VERSION 5.8 ;
BUSBITCHARS "[]" ;
DIVIDERCHAR "/" ;
UNITS
    DATABASE MICRONS 1000 ;
END UNITS

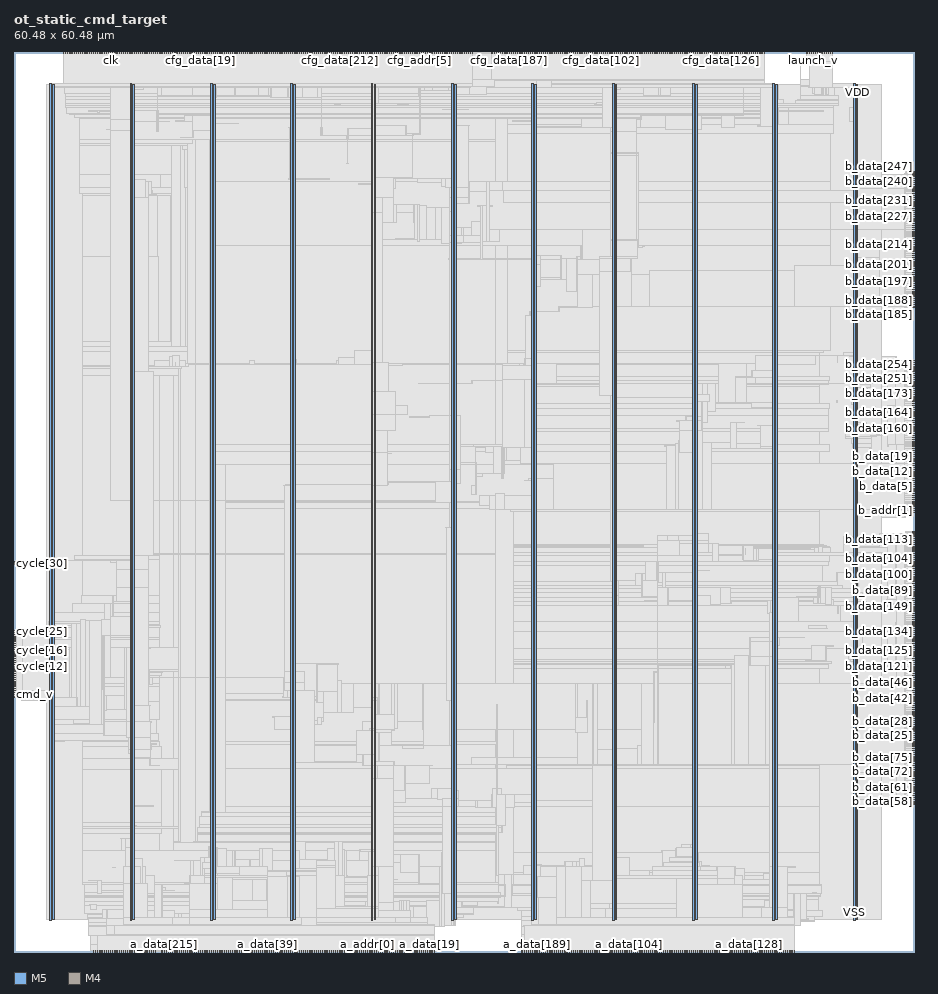
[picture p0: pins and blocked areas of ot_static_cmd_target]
MACRO ot_static_cmd_target
  FOREIGN ot_static_cmd_target 0 0 ;
  CLASS BLOCK ;
  SIZE 60.48 BY 60.48 ;
  PIN a_addr[0]
    DIRECTION OUTPUT ;
    USE SIGNAL ;
    PORT
      LAYER M5 ;
        RECT  23.76 0 23.784 0.084 ;
    END
  END a_addr[0]
  PIN a_addr[1]
    DIRECTION OUTPUT ;
    USE SIGNAL ;
    PORT
      LAYER M5 ;
        RECT  23.904 0 23.928 0.084 ;
    END
  END a_addr[1]
  PIN a_addr[2]
    DIRECTION OUTPUT ;
    USE SIGNAL ;
    PORT
      LAYER M5 ;
        RECT  24.048 0 24.072 0.084 ;
    END
  END a_addr[2]
  PIN a_addr[3]
    DIRECTION OUTPUT ;
    USE SIGNAL ;
    PORT
      LAYER M5 ;
        RECT  24.192 0 24.216 0.084 ;
    END
  END a_addr[3]
  PIN a_addr[4]
    DIRECTION OUTPUT ;
    USE SIGNAL ;
    PORT
      LAYER M5 ;
        RECT  24.336 0 24.36 0.084 ;
    END
  END a_addr[4]
  PIN a_addr[5]
    DIRECTION OUTPUT ;
    USE SIGNAL ;
    PORT
      LAYER M5 ;
        RECT  24.48 0 24.504 0.084 ;
    END
  END a_addr[5]
  PIN a_addr[6]
    DIRECTION OUTPUT ;
    USE SIGNAL ;
    PORT
      LAYER M5 ;
        RECT  24.624 0 24.648 0.084 ;
    END
  END a_addr[6]
  PIN a_addr[7]
    DIRECTION OUTPUT ;
    USE SIGNAL ;
    PORT
      LAYER M5 ;
        RECT  24.768 0 24.792 0.084 ;
    END
  END a_addr[7]
  PIN a_addr[8]
    DIRECTION OUTPUT ;
    USE SIGNAL ;
    PORT
      LAYER M5 ;
        RECT  24.912 0 24.936 0.084 ;
    END
  END a_addr[8]
  PIN a_addr[9]
    DIRECTION OUTPUT ;
    USE SIGNAL ;
    PORT
      LAYER M5 ;
        RECT  25.056 0 25.08 0.084 ;
    END
  END a_addr[9]
  PIN a_data[0]
    DIRECTION OUTPUT ;
    USE SIGNAL ;
    PORT
      LAYER M5 ;
        RECT  25.2 0 25.224 0.084 ;
    END
  END a_data[0]
  PIN a_data[100]
    DIRECTION OUTPUT ;
    USE SIGNAL ;
    PORT
      LAYER M5 ;
        RECT  40.752 0 40.776 0.084 ;
    END
  END a_data[100]
  PIN a_data[101]
    DIRECTION OUTPUT ;
    USE SIGNAL ;
    PORT
      LAYER M5 ;
        RECT  40.896 0 40.92 0.084 ;
    END
  END a_data[101]
  PIN a_data[102]
    DIRECTION OUTPUT ;
    USE SIGNAL ;
    PORT
      LAYER M5 ;
        RECT  41.04 0 41.064 0.084 ;
    END
  END a_data[102]
  PIN a_data[103]
    DIRECTION OUTPUT ;
    USE SIGNAL ;
    PORT
      LAYER M5 ;
        RECT  41.184 0 41.208 0.084 ;
    END
  END a_data[103]
  PIN a_data[104]
    DIRECTION OUTPUT ;
    USE SIGNAL ;
    PORT
      LAYER M5 ;
        RECT  41.328 0 41.352 0.084 ;
    END
  END a_data[104]
  PIN a_data[105]
    DIRECTION OUTPUT ;
    USE SIGNAL ;
    PORT
      LAYER M5 ;
        RECT  41.472 0 41.496 0.084 ;
    END
  END a_data[105]
  PIN a_data[106]
    DIRECTION OUTPUT ;
    USE SIGNAL ;
    PORT
      LAYER M5 ;
        RECT  41.616 0 41.64 0.084 ;
    END
  END a_data[106]
  PIN a_data[107]
    DIRECTION OUTPUT ;
    USE SIGNAL ;
    PORT
      LAYER M5 ;
        RECT  41.76 0 41.784 0.084 ;
    END
  END a_data[107]
  PIN a_data[108]
    DIRECTION OUTPUT ;
    USE SIGNAL ;
    PORT
      LAYER M5 ;
        RECT  41.904 0 41.928 0.084 ;
    END
  END a_data[108]
  PIN a_data[109]
    DIRECTION OUTPUT ;
    USE SIGNAL ;
    PORT
      LAYER M5 ;
        RECT  42.048 0 42.072 0.084 ;
    END
  END a_data[109]
  PIN a_data[10]
    DIRECTION OUTPUT ;
    USE SIGNAL ;
    PORT
      LAYER M5 ;
        RECT  26.64 0 26.664 0.084 ;
    END
  END a_data[10]
  PIN a_data[110]
    DIRECTION OUTPUT ;
    USE SIGNAL ;
    PORT
      LAYER M5 ;
        RECT  42.192 0 42.216 0.084 ;
    END
  END a_data[110]
  PIN a_data[111]
    DIRECTION OUTPUT ;
    USE SIGNAL ;
    PORT
      LAYER M5 ;
        RECT  42.336 0 42.36 0.084 ;
    END
  END a_data[111]
  PIN a_data[112]
    DIRECTION OUTPUT ;
    USE SIGNAL ;
    PORT
      LAYER M5 ;
        RECT  42.48 0 42.504 0.084 ;
    END
  END a_data[112]
  PIN a_data[113]
    DIRECTION OUTPUT ;
    USE SIGNAL ;
    PORT
      LAYER M5 ;
        RECT  42.624 0 42.648 0.084 ;
    END
  END a_data[113]
  PIN a_data[114]
    DIRECTION OUTPUT ;
    USE SIGNAL ;
    PORT
      LAYER M5 ;
        RECT  42.768 0 42.792 0.084 ;
    END
  END a_data[114]
  PIN a_data[115]
    DIRECTION OUTPUT ;
    USE SIGNAL ;
    PORT
      LAYER M5 ;
        RECT  42.912 0 42.936 0.084 ;
    END
  END a_data[115]
  PIN a_data[116]
    DIRECTION OUTPUT ;
    USE SIGNAL ;
    PORT
      LAYER M5 ;
        RECT  43.056 0 43.08 0.084 ;
    END
  END a_data[116]
  PIN a_data[117]
    DIRECTION OUTPUT ;
    USE SIGNAL ;
    PORT
      LAYER M5 ;
        RECT  43.2 0 43.224 0.084 ;
    END
  END a_data[117]
  PIN a_data[118]
    DIRECTION OUTPUT ;
    USE SIGNAL ;
    PORT
      LAYER M5 ;
        RECT  47.952 0 47.976 0.084 ;
    END
  END a_data[118]
  PIN a_data[119]
    DIRECTION OUTPUT ;
    USE SIGNAL ;
    PORT
      LAYER M5 ;
        RECT  48.096 0 48.12 0.084 ;
    END
  END a_data[119]
  PIN a_data[11]
    DIRECTION OUTPUT ;
    USE SIGNAL ;
    PORT
      LAYER M5 ;
        RECT  26.784 0 26.808 0.084 ;
    END
  END a_data[11]
  PIN a_data[120]
    DIRECTION OUTPUT ;
    USE SIGNAL ;
    PORT
      LAYER M5 ;
        RECT  48.24 0 48.264 0.084 ;
    END
  END a_data[120]
  PIN a_data[121]
    DIRECTION OUTPUT ;
    USE SIGNAL ;
    PORT
      LAYER M5 ;
        RECT  48.384 0 48.408 0.084 ;
    END
  END a_data[121]
  PIN a_data[122]
    DIRECTION OUTPUT ;
    USE SIGNAL ;
    PORT
      LAYER M5 ;
        RECT  48.528 0 48.552 0.084 ;
    END
  END a_data[122]
  PIN a_data[123]
    DIRECTION OUTPUT ;
    USE SIGNAL ;
    PORT
      LAYER M5 ;
        RECT  48.672 0 48.696 0.084 ;
    END
  END a_data[123]
  PIN a_data[124]
    DIRECTION OUTPUT ;
    USE SIGNAL ;
    PORT
      LAYER M5 ;
        RECT  48.816 0 48.84 0.084 ;
    END
  END a_data[124]
  PIN a_data[125]
    DIRECTION OUTPUT ;
    USE SIGNAL ;
    PORT
      LAYER M5 ;
        RECT  48.96 0 48.984 0.084 ;
    END
  END a_data[125]
  PIN a_data[126]
    DIRECTION OUTPUT ;
    USE SIGNAL ;
    PORT
      LAYER M5 ;
        RECT  49.104 0 49.128 0.084 ;
    END
  END a_data[126]
  PIN a_data[127]
    DIRECTION OUTPUT ;
    USE SIGNAL ;
    PORT
      LAYER M5 ;
        RECT  49.248 0 49.272 0.084 ;
    END
  END a_data[127]
  PIN a_data[128]
    DIRECTION OUTPUT ;
    USE SIGNAL ;
    PORT
      LAYER M5 ;
        RECT  49.392 0 49.416 0.084 ;
    END
  END a_data[128]
  PIN a_data[129]
    DIRECTION OUTPUT ;
    USE SIGNAL ;
    PORT
      LAYER M5 ;
        RECT  49.536 0 49.56 0.084 ;
    END
  END a_data[129]
  PIN a_data[12]
    DIRECTION OUTPUT ;
    USE SIGNAL ;
    PORT
      LAYER M5 ;
        RECT  26.928 0 26.952 0.084 ;
    END
  END a_data[12]
  PIN a_data[130]
    DIRECTION OUTPUT ;
    USE SIGNAL ;
    PORT
      LAYER M5 ;
        RECT  49.68 0 49.704 0.084 ;
    END
  END a_data[130]
  PIN a_data[131]
    DIRECTION OUTPUT ;
    USE SIGNAL ;
    PORT
      LAYER M5 ;
        RECT  49.824 0 49.848 0.084 ;
    END
  END a_data[131]
  PIN a_data[132]
    DIRECTION OUTPUT ;
    USE SIGNAL ;
    PORT
      LAYER M5 ;
        RECT  49.968 0 49.992 0.084 ;
    END
  END a_data[132]
  PIN a_data[133]
    DIRECTION OUTPUT ;
    USE SIGNAL ;
    PORT
      LAYER M5 ;
        RECT  50.112 0 50.136 0.084 ;
    END
  END a_data[133]
  PIN a_data[134]
    DIRECTION OUTPUT ;
    USE SIGNAL ;
    PORT
      LAYER M5 ;
        RECT  50.256 0 50.28 0.084 ;
    END
  END a_data[134]
  PIN a_data[135]
    DIRECTION OUTPUT ;
    USE SIGNAL ;
    PORT
      LAYER M5 ;
        RECT  50.4 0 50.424 0.084 ;
    END
  END a_data[135]
  PIN a_data[136]
    DIRECTION OUTPUT ;
    USE SIGNAL ;
    PORT
      LAYER M5 ;
        RECT  50.544 0 50.568 0.084 ;
    END
  END a_data[136]
  PIN a_data[137]
    DIRECTION OUTPUT ;
    USE SIGNAL ;
    PORT
      LAYER M5 ;
        RECT  50.688 0 50.712 0.084 ;
    END
  END a_data[137]
  PIN a_data[138]
    DIRECTION OUTPUT ;
    USE SIGNAL ;
    PORT
      LAYER M5 ;
        RECT  50.832 0 50.856 0.084 ;
    END
  END a_data[138]
  PIN a_data[139]
    DIRECTION OUTPUT ;
    USE SIGNAL ;
    PORT
      LAYER M5 ;
        RECT  50.976 0 51 0.084 ;
    END
  END a_data[139]
  PIN a_data[13]
    DIRECTION OUTPUT ;
    USE SIGNAL ;
    PORT
      LAYER M5 ;
        RECT  27.072 0 27.096 0.084 ;
    END
  END a_data[13]
  PIN a_data[140]
    DIRECTION OUTPUT ;
    USE SIGNAL ;
    PORT
      LAYER M5 ;
        RECT  51.12 0 51.144 0.084 ;
    END
  END a_data[140]
  PIN a_data[141]
    DIRECTION OUTPUT ;
    USE SIGNAL ;
    PORT
      LAYER M5 ;
        RECT  51.264 0 51.288 0.084 ;
    END
  END a_data[141]
  PIN a_data[142]
    DIRECTION OUTPUT ;
    USE SIGNAL ;
    PORT
      LAYER M5 ;
        RECT  51.408 0 51.432 0.084 ;
    END
  END a_data[142]
  PIN a_data[143]
    DIRECTION OUTPUT ;
    USE SIGNAL ;
    PORT
      LAYER M5 ;
        RECT  51.552 0 51.576 0.084 ;
    END
  END a_data[143]
  PIN a_data[144]
    DIRECTION OUTPUT ;
    USE SIGNAL ;
    PORT
      LAYER M5 ;
        RECT  51.696 0 51.72 0.084 ;
    END
  END a_data[144]
  PIN a_data[145]
    DIRECTION OUTPUT ;
    USE SIGNAL ;
    PORT
      LAYER M5 ;
        RECT  51.84 0 51.864 0.084 ;
    END
  END a_data[145]
  PIN a_data[146]
    DIRECTION OUTPUT ;
    USE SIGNAL ;
    PORT
      LAYER M5 ;
        RECT  51.984 0 52.008 0.084 ;
    END
  END a_data[146]
  PIN a_data[147]
    DIRECTION OUTPUT ;
    USE SIGNAL ;
    PORT
      LAYER M5 ;
        RECT  52.128 0 52.152 0.084 ;
    END
  END a_data[147]
  PIN a_data[148]
    DIRECTION OUTPUT ;
    USE SIGNAL ;
    PORT
      LAYER M5 ;
        RECT  52.272 0 52.296 0.084 ;
    END
  END a_data[148]
  PIN a_data[149]
    DIRECTION OUTPUT ;
    USE SIGNAL ;
    PORT
      LAYER M5 ;
        RECT  52.416 0 52.44 0.084 ;
    END
  END a_data[149]
  PIN a_data[14]
    DIRECTION OUTPUT ;
    USE SIGNAL ;
    PORT
      LAYER M5 ;
        RECT  27.216 0 27.24 0.084 ;
    END
  END a_data[14]
  PIN a_data[150]
    DIRECTION OUTPUT ;
    USE SIGNAL ;
    PORT
      LAYER M5 ;
        RECT  43.344 0 43.368 0.084 ;
    END
  END a_data[150]
  PIN a_data[151]
    DIRECTION OUTPUT ;
    USE SIGNAL ;
    PORT
      LAYER M5 ;
        RECT  43.488 0 43.512 0.084 ;
    END
  END a_data[151]
  PIN a_data[152]
    DIRECTION OUTPUT ;
    USE SIGNAL ;
    PORT
      LAYER M5 ;
        RECT  43.632 0 43.656 0.084 ;
    END
  END a_data[152]
  PIN a_data[153]
    DIRECTION OUTPUT ;
    USE SIGNAL ;
    PORT
      LAYER M5 ;
        RECT  43.776 0 43.8 0.084 ;
    END
  END a_data[153]
  PIN a_data[154]
    DIRECTION OUTPUT ;
    USE SIGNAL ;
    PORT
      LAYER M5 ;
        RECT  43.92 0 43.944 0.084 ;
    END
  END a_data[154]
  PIN a_data[155]
    DIRECTION OUTPUT ;
    USE SIGNAL ;
    PORT
      LAYER M5 ;
        RECT  44.064 0 44.088 0.084 ;
    END
  END a_data[155]
  PIN a_data[156]
    DIRECTION OUTPUT ;
    USE SIGNAL ;
    PORT
      LAYER M5 ;
        RECT  44.208 0 44.232 0.084 ;
    END
  END a_data[156]
  PIN a_data[157]
    DIRECTION OUTPUT ;
    USE SIGNAL ;
    PORT
      LAYER M5 ;
        RECT  44.352 0 44.376 0.084 ;
    END
  END a_data[157]
  PIN a_data[158]
    DIRECTION OUTPUT ;
    USE SIGNAL ;
    PORT
      LAYER M5 ;
        RECT  44.496 0 44.52 0.084 ;
    END
  END a_data[158]
  PIN a_data[159]
    DIRECTION OUTPUT ;
    USE SIGNAL ;
    PORT
      LAYER M5 ;
        RECT  44.64 0 44.664 0.084 ;
    END
  END a_data[159]
  PIN a_data[15]
    DIRECTION OUTPUT ;
    USE SIGNAL ;
    PORT
      LAYER M5 ;
        RECT  27.36 0 27.384 0.084 ;
    END
  END a_data[15]
  PIN a_data[160]
    DIRECTION OUTPUT ;
    USE SIGNAL ;
    PORT
      LAYER M5 ;
        RECT  44.784 0 44.808 0.084 ;
    END
  END a_data[160]
  PIN a_data[161]
    DIRECTION OUTPUT ;
    USE SIGNAL ;
    PORT
      LAYER M5 ;
        RECT  44.928 0 44.952 0.084 ;
    END
  END a_data[161]
  PIN a_data[162]
    DIRECTION OUTPUT ;
    USE SIGNAL ;
    PORT
      LAYER M5 ;
        RECT  45.072 0 45.096 0.084 ;
    END
  END a_data[162]
  PIN a_data[163]
    DIRECTION OUTPUT ;
    USE SIGNAL ;
    PORT
      LAYER M5 ;
        RECT  45.216 0 45.24 0.084 ;
    END
  END a_data[163]
  PIN a_data[164]
    DIRECTION OUTPUT ;
    USE SIGNAL ;
    PORT
      LAYER M5 ;
        RECT  45.36 0 45.384 0.084 ;
    END
  END a_data[164]
  PIN a_data[165]
    DIRECTION OUTPUT ;
    USE SIGNAL ;
    PORT
      LAYER M5 ;
        RECT  45.504 0 45.528 0.084 ;
    END
  END a_data[165]
  PIN a_data[166]
    DIRECTION OUTPUT ;
    USE SIGNAL ;
    PORT
      LAYER M5 ;
        RECT  45.648 0 45.672 0.084 ;
    END
  END a_data[166]
  PIN a_data[167]
    DIRECTION OUTPUT ;
    USE SIGNAL ;
    PORT
      LAYER M5 ;
        RECT  45.792 0 45.816 0.084 ;
    END
  END a_data[167]
  PIN a_data[168]
    DIRECTION OUTPUT ;
    USE SIGNAL ;
    PORT
      LAYER M5 ;
        RECT  45.936 0 45.96 0.084 ;
    END
  END a_data[168]
  PIN a_data[169]
    DIRECTION OUTPUT ;
    USE SIGNAL ;
    PORT
      LAYER M5 ;
        RECT  46.08 0 46.104 0.084 ;
    END
  END a_data[169]
  PIN a_data[16]
    DIRECTION OUTPUT ;
    USE SIGNAL ;
    PORT
      LAYER M5 ;
        RECT  27.504 0 27.528 0.084 ;
    END
  END a_data[16]
  PIN a_data[170]
    DIRECTION OUTPUT ;
    USE SIGNAL ;
    PORT
      LAYER M5 ;
        RECT  46.224 0 46.248 0.084 ;
    END
  END a_data[170]
  PIN a_data[171]
    DIRECTION OUTPUT ;
    USE SIGNAL ;
    PORT
      LAYER M5 ;
        RECT  46.368 0 46.392 0.084 ;
    END
  END a_data[171]
  PIN a_data[172]
    DIRECTION OUTPUT ;
    USE SIGNAL ;
    PORT
      LAYER M5 ;
        RECT  46.512 0 46.536 0.084 ;
    END
  END a_data[172]
  PIN a_data[173]
    DIRECTION OUTPUT ;
    USE SIGNAL ;
    PORT
      LAYER M5 ;
        RECT  46.656 0 46.68 0.084 ;
    END
  END a_data[173]
  PIN a_data[174]
    DIRECTION OUTPUT ;
    USE SIGNAL ;
    PORT
      LAYER M5 ;
        RECT  46.8 0 46.824 0.084 ;
    END
  END a_data[174]
  PIN a_data[175]
    DIRECTION OUTPUT ;
    USE SIGNAL ;
    PORT
      LAYER M5 ;
        RECT  46.944 0 46.968 0.084 ;
    END
  END a_data[175]
  PIN a_data[176]
    DIRECTION OUTPUT ;
    USE SIGNAL ;
    PORT
      LAYER M5 ;
        RECT  47.088 0 47.112 0.084 ;
    END
  END a_data[176]
  PIN a_data[177]
    DIRECTION OUTPUT ;
    USE SIGNAL ;
    PORT
      LAYER M5 ;
        RECT  47.232 0 47.256 0.084 ;
    END
  END a_data[177]
  PIN a_data[178]
    DIRECTION OUTPUT ;
    USE SIGNAL ;
    PORT
      LAYER M5 ;
        RECT  47.376 0 47.4 0.084 ;
    END
  END a_data[178]
  PIN a_data[179]
    DIRECTION OUTPUT ;
    USE SIGNAL ;
    PORT
      LAYER M5 ;
        RECT  47.52 0 47.544 0.084 ;
    END
  END a_data[179]
  PIN a_data[17]
    DIRECTION OUTPUT ;
    USE SIGNAL ;
    PORT
      LAYER M5 ;
        RECT  27.648 0 27.672 0.084 ;
    END
  END a_data[17]
  PIN a_data[180]
    DIRECTION OUTPUT ;
    USE SIGNAL ;
    PORT
      LAYER M5 ;
        RECT  47.664 0 47.688 0.084 ;
    END
  END a_data[180]
  PIN a_data[181]
    DIRECTION OUTPUT ;
    USE SIGNAL ;
    PORT
      LAYER M5 ;
        RECT  47.808 0 47.832 0.084 ;
    END
  END a_data[181]
  PIN a_data[182]
    DIRECTION OUTPUT ;
    USE SIGNAL ;
    PORT
      LAYER M5 ;
        RECT  34.128 0 34.152 0.084 ;
    END
  END a_data[182]
  PIN a_data[183]
    DIRECTION OUTPUT ;
    USE SIGNAL ;
    PORT
      LAYER M5 ;
        RECT  34.272 0 34.296 0.084 ;
    END
  END a_data[183]
  PIN a_data[184]
    DIRECTION OUTPUT ;
    USE SIGNAL ;
    PORT
      LAYER M5 ;
        RECT  34.416 0 34.44 0.084 ;
    END
  END a_data[184]
  PIN a_data[185]
    DIRECTION OUTPUT ;
    USE SIGNAL ;
    PORT
      LAYER M5 ;
        RECT  34.56 0 34.584 0.084 ;
    END
  END a_data[185]
  PIN a_data[186]
    DIRECTION OUTPUT ;
    USE SIGNAL ;
    PORT
      LAYER M5 ;
        RECT  34.704 0 34.728 0.084 ;
    END
  END a_data[186]
  PIN a_data[187]
    DIRECTION OUTPUT ;
    USE SIGNAL ;
    PORT
      LAYER M5 ;
        RECT  34.848 0 34.872 0.084 ;
    END
  END a_data[187]
  PIN a_data[188]
    DIRECTION OUTPUT ;
    USE SIGNAL ;
    PORT
      LAYER M5 ;
        RECT  34.992 0 35.016 0.084 ;
    END
  END a_data[188]
  PIN a_data[189]
    DIRECTION OUTPUT ;
    USE SIGNAL ;
    PORT
      LAYER M5 ;
        RECT  35.136 0 35.16 0.084 ;
    END
  END a_data[189]
  PIN a_data[18]
    DIRECTION OUTPUT ;
    USE SIGNAL ;
    PORT
      LAYER M5 ;
        RECT  27.792 0 27.816 0.084 ;
    END
  END a_data[18]
  PIN a_data[190]
    DIRECTION OUTPUT ;
    USE SIGNAL ;
    PORT
      LAYER M5 ;
        RECT  35.28 0 35.304 0.084 ;
    END
  END a_data[190]
  PIN a_data[191]
    DIRECTION OUTPUT ;
    USE SIGNAL ;
    PORT
      LAYER M5 ;
        RECT  35.424 0 35.448 0.084 ;
    END
  END a_data[191]
  PIN a_data[192]
    DIRECTION OUTPUT ;
    USE SIGNAL ;
    PORT
      LAYER M5 ;
        RECT  35.568 0 35.592 0.084 ;
    END
  END a_data[192]
  PIN a_data[193]
    DIRECTION OUTPUT ;
    USE SIGNAL ;
    PORT
      LAYER M5 ;
        RECT  35.712 0 35.736 0.084 ;
    END
  END a_data[193]
  PIN a_data[194]
    DIRECTION OUTPUT ;
    USE SIGNAL ;
    PORT
      LAYER M5 ;
        RECT  35.856 0 35.88 0.084 ;
    END
  END a_data[194]
  PIN a_data[195]
    DIRECTION OUTPUT ;
    USE SIGNAL ;
    PORT
      LAYER M5 ;
        RECT  36 0 36.024 0.084 ;
    END
  END a_data[195]
  PIN a_data[196]
    DIRECTION OUTPUT ;
    USE SIGNAL ;
    PORT
      LAYER M5 ;
        RECT  36.144 0 36.168 0.084 ;
    END
  END a_data[196]
  PIN a_data[197]
    DIRECTION OUTPUT ;
    USE SIGNAL ;
    PORT
      LAYER M5 ;
        RECT  36.288 0 36.312 0.084 ;
    END
  END a_data[197]
  PIN a_data[198]
    DIRECTION OUTPUT ;
    USE SIGNAL ;
    PORT
      LAYER M5 ;
        RECT  36.432 0 36.456 0.084 ;
    END
  END a_data[198]
  PIN a_data[199]
    DIRECTION OUTPUT ;
    USE SIGNAL ;
    PORT
      LAYER M5 ;
        RECT  36.576 0 36.6 0.084 ;
    END
  END a_data[199]
  PIN a_data[19]
    DIRECTION OUTPUT ;
    USE SIGNAL ;
    PORT
      LAYER M5 ;
        RECT  27.936 0 27.96 0.084 ;
    END
  END a_data[19]
  PIN a_data[1]
    DIRECTION OUTPUT ;
    USE SIGNAL ;
    PORT
      LAYER M5 ;
        RECT  25.344 0 25.368 0.084 ;
    END
  END a_data[1]
  PIN a_data[200]
    DIRECTION OUTPUT ;
    USE SIGNAL ;
    PORT
      LAYER M5 ;
        RECT  36.72 0 36.744 0.084 ;
    END
  END a_data[200]
  PIN a_data[201]
    DIRECTION OUTPUT ;
    USE SIGNAL ;
    PORT
      LAYER M5 ;
        RECT  36.864 0 36.888 0.084 ;
    END
  END a_data[201]
  PIN a_data[202]
    DIRECTION OUTPUT ;
    USE SIGNAL ;
    PORT
      LAYER M5 ;
        RECT  37.008 0 37.032 0.084 ;
    END
  END a_data[202]
  PIN a_data[203]
    DIRECTION OUTPUT ;
    USE SIGNAL ;
    PORT
      LAYER M5 ;
        RECT  37.152 0 37.176 0.084 ;
    END
  END a_data[203]
  PIN a_data[204]
    DIRECTION OUTPUT ;
    USE SIGNAL ;
    PORT
      LAYER M5 ;
        RECT  37.296 0 37.32 0.084 ;
    END
  END a_data[204]
  PIN a_data[205]
    DIRECTION OUTPUT ;
    USE SIGNAL ;
    PORT
      LAYER M5 ;
        RECT  37.44 0 37.464 0.084 ;
    END
  END a_data[205]
  PIN a_data[206]
    DIRECTION OUTPUT ;
    USE SIGNAL ;
    PORT
      LAYER M5 ;
        RECT  37.584 0 37.608 0.084 ;
    END
  END a_data[206]
  PIN a_data[207]
    DIRECTION OUTPUT ;
    USE SIGNAL ;
    PORT
      LAYER M5 ;
        RECT  37.728 0 37.752 0.084 ;
    END
  END a_data[207]
  PIN a_data[208]
    DIRECTION OUTPUT ;
    USE SIGNAL ;
    PORT
      LAYER M5 ;
        RECT  37.872 0 37.896 0.084 ;
    END
  END a_data[208]
  PIN a_data[209]
    DIRECTION OUTPUT ;
    USE SIGNAL ;
    PORT
      LAYER M5 ;
        RECT  38.016 0 38.04 0.084 ;
    END
  END a_data[209]
  PIN a_data[20]
    DIRECTION OUTPUT ;
    USE SIGNAL ;
    PORT
      LAYER M5 ;
        RECT  28.08 0 28.104 0.084 ;
    END
  END a_data[20]
  PIN a_data[210]
    DIRECTION OUTPUT ;
    USE SIGNAL ;
    PORT
      LAYER M5 ;
        RECT  38.16 0 38.184 0.084 ;
    END
  END a_data[210]
  PIN a_data[211]
    DIRECTION OUTPUT ;
    USE SIGNAL ;
    PORT
      LAYER M5 ;
        RECT  38.304 0 38.328 0.084 ;
    END
  END a_data[211]
  PIN a_data[212]
    DIRECTION OUTPUT ;
    USE SIGNAL ;
    PORT
      LAYER M5 ;
        RECT  38.448 0 38.472 0.084 ;
    END
  END a_data[212]
  PIN a_data[213]
    DIRECTION OUTPUT ;
    USE SIGNAL ;
    PORT
      LAYER M5 ;
        RECT  38.592 0 38.616 0.084 ;
    END
  END a_data[213]
  PIN a_data[214]
    DIRECTION OUTPUT ;
    USE SIGNAL ;
    PORT
      LAYER M5 ;
        RECT  9.936 0 9.96 0.084 ;
    END
  END a_data[214]
  PIN a_data[215]
    DIRECTION OUTPUT ;
    USE SIGNAL ;
    PORT
      LAYER M5 ;
        RECT  10.08 0 10.104 0.084 ;
    END
  END a_data[215]
  PIN a_data[216]
    DIRECTION OUTPUT ;
    USE SIGNAL ;
    PORT
      LAYER M5 ;
        RECT  10.224 0 10.248 0.084 ;
    END
  END a_data[216]
  PIN a_data[217]
    DIRECTION OUTPUT ;
    USE SIGNAL ;
    PORT
      LAYER M5 ;
        RECT  10.368 0 10.392 0.084 ;
    END
  END a_data[217]
  PIN a_data[218]
    DIRECTION OUTPUT ;
    USE SIGNAL ;
    PORT
      LAYER M5 ;
        RECT  10.512 0 10.536 0.084 ;
    END
  END a_data[218]
  PIN a_data[219]
    DIRECTION OUTPUT ;
    USE SIGNAL ;
    PORT
      LAYER M5 ;
        RECT  10.656 0 10.68 0.084 ;
    END
  END a_data[219]
  PIN a_data[21]
    DIRECTION OUTPUT ;
    USE SIGNAL ;
    PORT
      LAYER M5 ;
        RECT  28.224 0 28.248 0.084 ;
    END
  END a_data[21]
  PIN a_data[220]
    DIRECTION OUTPUT ;
    USE SIGNAL ;
    PORT
      LAYER M5 ;
        RECT  10.8 0 10.824 0.084 ;
    END
  END a_data[220]
  PIN a_data[221]
    DIRECTION OUTPUT ;
    USE SIGNAL ;
    PORT
      LAYER M5 ;
        RECT  10.944 0 10.968 0.084 ;
    END
  END a_data[221]
  PIN a_data[222]
    DIRECTION OUTPUT ;
    USE SIGNAL ;
    PORT
      LAYER M5 ;
        RECT  11.088 0 11.112 0.084 ;
    END
  END a_data[222]
  PIN a_data[223]
    DIRECTION OUTPUT ;
    USE SIGNAL ;
    PORT
      LAYER M5 ;
        RECT  11.232 0 11.256 0.084 ;
    END
  END a_data[223]
  PIN a_data[224]
    DIRECTION OUTPUT ;
    USE SIGNAL ;
    PORT
      LAYER M5 ;
        RECT  11.376 0 11.4 0.084 ;
    END
  END a_data[224]
  PIN a_data[225]
    DIRECTION OUTPUT ;
    USE SIGNAL ;
    PORT
      LAYER M5 ;
        RECT  11.52 0 11.544 0.084 ;
    END
  END a_data[225]
  PIN a_data[226]
    DIRECTION OUTPUT ;
    USE SIGNAL ;
    PORT
      LAYER M5 ;
        RECT  11.664 0 11.688 0.084 ;
    END
  END a_data[226]
  PIN a_data[227]
    DIRECTION OUTPUT ;
    USE SIGNAL ;
    PORT
      LAYER M5 ;
        RECT  11.808 0 11.832 0.084 ;
    END
  END a_data[227]
  PIN a_data[228]
    DIRECTION OUTPUT ;
    USE SIGNAL ;
    PORT
      LAYER M5 ;
        RECT  11.952 0 11.976 0.084 ;
    END
  END a_data[228]
  PIN a_data[229]
    DIRECTION OUTPUT ;
    USE SIGNAL ;
    PORT
      LAYER M5 ;
        RECT  12.096 0 12.12 0.084 ;
    END
  END a_data[229]
  PIN a_data[22]
    DIRECTION OUTPUT ;
    USE SIGNAL ;
    PORT
      LAYER M5 ;
        RECT  14.544 0 14.568 0.084 ;
    END
  END a_data[22]
  PIN a_data[230]
    DIRECTION OUTPUT ;
    USE SIGNAL ;
    PORT
      LAYER M5 ;
        RECT  12.24 0 12.264 0.084 ;
    END
  END a_data[230]
  PIN a_data[231]
    DIRECTION OUTPUT ;
    USE SIGNAL ;
    PORT
      LAYER M5 ;
        RECT  12.384 0 12.408 0.084 ;
    END
  END a_data[231]
  PIN a_data[232]
    DIRECTION OUTPUT ;
    USE SIGNAL ;
    PORT
      LAYER M5 ;
        RECT  12.528 0 12.552 0.084 ;
    END
  END a_data[232]
  PIN a_data[233]
    DIRECTION OUTPUT ;
    USE SIGNAL ;
    PORT
      LAYER M5 ;
        RECT  12.672 0 12.696 0.084 ;
    END
  END a_data[233]
  PIN a_data[234]
    DIRECTION OUTPUT ;
    USE SIGNAL ;
    PORT
      LAYER M5 ;
        RECT  12.816 0 12.84 0.084 ;
    END
  END a_data[234]
  PIN a_data[235]
    DIRECTION OUTPUT ;
    USE SIGNAL ;
    PORT
      LAYER M5 ;
        RECT  12.96 0 12.984 0.084 ;
    END
  END a_data[235]
  PIN a_data[236]
    DIRECTION OUTPUT ;
    USE SIGNAL ;
    PORT
      LAYER M5 ;
        RECT  13.104 0 13.128 0.084 ;
    END
  END a_data[236]
  PIN a_data[237]
    DIRECTION OUTPUT ;
    USE SIGNAL ;
    PORT
      LAYER M5 ;
        RECT  13.248 0 13.272 0.084 ;
    END
  END a_data[237]
  PIN a_data[238]
    DIRECTION OUTPUT ;
    USE SIGNAL ;
    PORT
      LAYER M5 ;
        RECT  13.392 0 13.416 0.084 ;
    END
  END a_data[238]
  PIN a_data[239]
    DIRECTION OUTPUT ;
    USE SIGNAL ;
    PORT
      LAYER M5 ;
        RECT  13.536 0 13.56 0.084 ;
    END
  END a_data[239]
  PIN a_data[23]
    DIRECTION OUTPUT ;
    USE SIGNAL ;
    PORT
      LAYER M5 ;
        RECT  14.688 0 14.712 0.084 ;
    END
  END a_data[23]
  PIN a_data[240]
    DIRECTION OUTPUT ;
    USE SIGNAL ;
    PORT
      LAYER M5 ;
        RECT  13.68 0 13.704 0.084 ;
    END
  END a_data[240]
  PIN a_data[241]
    DIRECTION OUTPUT ;
    USE SIGNAL ;
    PORT
      LAYER M5 ;
        RECT  13.824 0 13.848 0.084 ;
    END
  END a_data[241]
  PIN a_data[242]
    DIRECTION OUTPUT ;
    USE SIGNAL ;
    PORT
      LAYER M5 ;
        RECT  13.968 0 13.992 0.084 ;
    END
  END a_data[242]
  PIN a_data[243]
    DIRECTION OUTPUT ;
    USE SIGNAL ;
    PORT
      LAYER M5 ;
        RECT  14.112 0 14.136 0.084 ;
    END
  END a_data[243]
  PIN a_data[244]
    DIRECTION OUTPUT ;
    USE SIGNAL ;
    PORT
      LAYER M5 ;
        RECT  14.256 0 14.28 0.084 ;
    END
  END a_data[244]
  PIN a_data[245]
    DIRECTION OUTPUT ;
    USE SIGNAL ;
    PORT
      LAYER M5 ;
        RECT  14.4 0 14.424 0.084 ;
    END
  END a_data[245]
  PIN a_data[246]
    DIRECTION OUTPUT ;
    USE SIGNAL ;
    PORT
      LAYER M5 ;
        RECT  5.328 0 5.352 0.084 ;
    END
  END a_data[246]
  PIN a_data[247]
    DIRECTION OUTPUT ;
    USE SIGNAL ;
    PORT
      LAYER M5 ;
        RECT  5.472 0 5.496 0.084 ;
    END
  END a_data[247]
  PIN a_data[248]
    DIRECTION OUTPUT ;
    USE SIGNAL ;
    PORT
      LAYER M5 ;
        RECT  5.616 0 5.64 0.084 ;
    END
  END a_data[248]
  PIN a_data[249]
    DIRECTION OUTPUT ;
    USE SIGNAL ;
    PORT
      LAYER M5 ;
        RECT  5.76 0 5.784 0.084 ;
    END
  END a_data[249]
  PIN a_data[24]
    DIRECTION OUTPUT ;
    USE SIGNAL ;
    PORT
      LAYER M5 ;
        RECT  14.832 0 14.856 0.084 ;
    END
  END a_data[24]
  PIN a_data[250]
    DIRECTION OUTPUT ;
    USE SIGNAL ;
    PORT
      LAYER M5 ;
        RECT  5.904 0 5.928 0.084 ;
    END
  END a_data[250]
  PIN a_data[251]
    DIRECTION OUTPUT ;
    USE SIGNAL ;
    PORT
      LAYER M5 ;
        RECT  6.048 0 6.072 0.084 ;
    END
  END a_data[251]
  PIN a_data[252]
    DIRECTION OUTPUT ;
    USE SIGNAL ;
    PORT
      LAYER M5 ;
        RECT  6.192 0 6.216 0.084 ;
    END
  END a_data[252]
  PIN a_data[253]
    DIRECTION OUTPUT ;
    USE SIGNAL ;
    PORT
      LAYER M5 ;
        RECT  6.336 0 6.36 0.084 ;
    END
  END a_data[253]
  PIN a_data[254]
    DIRECTION OUTPUT ;
    USE SIGNAL ;
    PORT
      LAYER M5 ;
        RECT  6.48 0 6.504 0.084 ;
    END
  END a_data[254]
  PIN a_data[255]
    DIRECTION OUTPUT ;
    USE SIGNAL ;
    PORT
      LAYER M5 ;
        RECT  6.624 0 6.648 0.084 ;
    END
  END a_data[255]
  PIN a_data[25]
    DIRECTION OUTPUT ;
    USE SIGNAL ;
    PORT
      LAYER M5 ;
        RECT  14.976 0 15 0.084 ;
    END
  END a_data[25]
  PIN a_data[26]
    DIRECTION OUTPUT ;
    USE SIGNAL ;
    PORT
      LAYER M5 ;
        RECT  15.12 0 15.144 0.084 ;
    END
  END a_data[26]
  PIN a_data[27]
    DIRECTION OUTPUT ;
    USE SIGNAL ;
    PORT
      LAYER M5 ;
        RECT  15.264 0 15.288 0.084 ;
    END
  END a_data[27]
  PIN a_data[28]
    DIRECTION OUTPUT ;
    USE SIGNAL ;
    PORT
      LAYER M5 ;
        RECT  15.408 0 15.432 0.084 ;
    END
  END a_data[28]
  PIN a_data[29]
    DIRECTION OUTPUT ;
    USE SIGNAL ;
    PORT
      LAYER M5 ;
        RECT  15.552 0 15.576 0.084 ;
    END
  END a_data[29]
  PIN a_data[2]
    DIRECTION OUTPUT ;
    USE SIGNAL ;
    PORT
      LAYER M5 ;
        RECT  25.488 0 25.512 0.084 ;
    END
  END a_data[2]
  PIN a_data[30]
    DIRECTION OUTPUT ;
    USE SIGNAL ;
    PORT
      LAYER M5 ;
        RECT  15.696 0 15.72 0.084 ;
    END
  END a_data[30]
  PIN a_data[31]
    DIRECTION OUTPUT ;
    USE SIGNAL ;
    PORT
      LAYER M5 ;
        RECT  15.84 0 15.864 0.084 ;
    END
  END a_data[31]
  PIN a_data[32]
    DIRECTION OUTPUT ;
    USE SIGNAL ;
    PORT
      LAYER M5 ;
        RECT  15.984 0 16.008 0.084 ;
    END
  END a_data[32]
  PIN a_data[33]
    DIRECTION OUTPUT ;
    USE SIGNAL ;
    PORT
      LAYER M5 ;
        RECT  16.128 0 16.152 0.084 ;
    END
  END a_data[33]
  PIN a_data[34]
    DIRECTION OUTPUT ;
    USE SIGNAL ;
    PORT
      LAYER M5 ;
        RECT  16.272 0 16.296 0.084 ;
    END
  END a_data[34]
  PIN a_data[35]
    DIRECTION OUTPUT ;
    USE SIGNAL ;
    PORT
      LAYER M5 ;
        RECT  16.416 0 16.44 0.084 ;
    END
  END a_data[35]
  PIN a_data[36]
    DIRECTION OUTPUT ;
    USE SIGNAL ;
    PORT
      LAYER M5 ;
        RECT  16.56 0 16.584 0.084 ;
    END
  END a_data[36]
  PIN a_data[37]
    DIRECTION OUTPUT ;
    USE SIGNAL ;
    PORT
      LAYER M5 ;
        RECT  16.704 0 16.728 0.084 ;
    END
  END a_data[37]
  PIN a_data[38]
    DIRECTION OUTPUT ;
    USE SIGNAL ;
    PORT
      LAYER M5 ;
        RECT  16.848 0 16.872 0.084 ;
    END
  END a_data[38]
  PIN a_data[39]
    DIRECTION OUTPUT ;
    USE SIGNAL ;
    PORT
      LAYER M5 ;
        RECT  16.992 0 17.016 0.084 ;
    END
  END a_data[39]
  PIN a_data[3]
    DIRECTION OUTPUT ;
    USE SIGNAL ;
    PORT
      LAYER M5 ;
        RECT  25.632 0 25.656 0.084 ;
    END
  END a_data[3]
  PIN a_data[40]
    DIRECTION OUTPUT ;
    USE SIGNAL ;
    PORT
      LAYER M5 ;
        RECT  17.136 0 17.16 0.084 ;
    END
  END a_data[40]
  PIN a_data[41]
    DIRECTION OUTPUT ;
    USE SIGNAL ;
    PORT
      LAYER M5 ;
        RECT  17.28 0 17.304 0.084 ;
    END
  END a_data[41]
  PIN a_data[42]
    DIRECTION OUTPUT ;
    USE SIGNAL ;
    PORT
      LAYER M5 ;
        RECT  17.424 0 17.448 0.084 ;
    END
  END a_data[42]
  PIN a_data[43]
    DIRECTION OUTPUT ;
    USE SIGNAL ;
    PORT
      LAYER M5 ;
        RECT  17.568 0 17.592 0.084 ;
    END
  END a_data[43]
  PIN a_data[44]
    DIRECTION OUTPUT ;
    USE SIGNAL ;
    PORT
      LAYER M5 ;
        RECT  17.712 0 17.736 0.084 ;
    END
  END a_data[44]
  PIN a_data[45]
    DIRECTION OUTPUT ;
    USE SIGNAL ;
    PORT
      LAYER M5 ;
        RECT  17.856 0 17.88 0.084 ;
    END
  END a_data[45]
  PIN a_data[46]
    DIRECTION OUTPUT ;
    USE SIGNAL ;
    PORT
      LAYER M5 ;
        RECT  18 0 18.024 0.084 ;
    END
  END a_data[46]
  PIN a_data[47]
    DIRECTION OUTPUT ;
    USE SIGNAL ;
    PORT
      LAYER M5 ;
        RECT  18.144 0 18.168 0.084 ;
    END
  END a_data[47]
  PIN a_data[48]
    DIRECTION OUTPUT ;
    USE SIGNAL ;
    PORT
      LAYER M5 ;
        RECT  18.288 0 18.312 0.084 ;
    END
  END a_data[48]
  PIN a_data[49]
    DIRECTION OUTPUT ;
    USE SIGNAL ;
    PORT
      LAYER M5 ;
        RECT  18.432 0 18.456 0.084 ;
    END
  END a_data[49]
  PIN a_data[4]
    DIRECTION OUTPUT ;
    USE SIGNAL ;
    PORT
      LAYER M5 ;
        RECT  25.776 0 25.8 0.084 ;
    END
  END a_data[4]
  PIN a_data[50]
    DIRECTION OUTPUT ;
    USE SIGNAL ;
    PORT
      LAYER M5 ;
        RECT  18.576 0 18.6 0.084 ;
    END
  END a_data[50]
  PIN a_data[51]
    DIRECTION OUTPUT ;
    USE SIGNAL ;
    PORT
      LAYER M5 ;
        RECT  18.72 0 18.744 0.084 ;
    END
  END a_data[51]
  PIN a_data[52]
    DIRECTION OUTPUT ;
    USE SIGNAL ;
    PORT
      LAYER M5 ;
        RECT  18.864 0 18.888 0.084 ;
    END
  END a_data[52]
  PIN a_data[53]
    DIRECTION OUTPUT ;
    USE SIGNAL ;
    PORT
      LAYER M5 ;
        RECT  19.008 0 19.032 0.084 ;
    END
  END a_data[53]
  PIN a_data[54]
    DIRECTION OUTPUT ;
    USE SIGNAL ;
    PORT
      LAYER M5 ;
        RECT  19.152 0 19.176 0.084 ;
    END
  END a_data[54]
  PIN a_data[55]
    DIRECTION OUTPUT ;
    USE SIGNAL ;
    PORT
      LAYER M5 ;
        RECT  19.296 0 19.32 0.084 ;
    END
  END a_data[55]
  PIN a_data[56]
    DIRECTION OUTPUT ;
    USE SIGNAL ;
    PORT
      LAYER M5 ;
        RECT  19.44 0 19.464 0.084 ;
    END
  END a_data[56]
  PIN a_data[57]
    DIRECTION OUTPUT ;
    USE SIGNAL ;
    PORT
      LAYER M5 ;
        RECT  19.584 0 19.608 0.084 ;
    END
  END a_data[57]
  PIN a_data[58]
    DIRECTION OUTPUT ;
    USE SIGNAL ;
    PORT
      LAYER M5 ;
        RECT  19.728 0 19.752 0.084 ;
    END
  END a_data[58]
  PIN a_data[59]
    DIRECTION OUTPUT ;
    USE SIGNAL ;
    PORT
      LAYER M5 ;
        RECT  19.872 0 19.896 0.084 ;
    END
  END a_data[59]
  PIN a_data[5]
    DIRECTION OUTPUT ;
    USE SIGNAL ;
    PORT
      LAYER M5 ;
        RECT  25.92 0 25.944 0.084 ;
    END
  END a_data[5]
  PIN a_data[60]
    DIRECTION OUTPUT ;
    USE SIGNAL ;
    PORT
      LAYER M5 ;
        RECT  20.016 0 20.04 0.084 ;
    END
  END a_data[60]
  PIN a_data[61]
    DIRECTION OUTPUT ;
    USE SIGNAL ;
    PORT
      LAYER M5 ;
        RECT  20.16 0 20.184 0.084 ;
    END
  END a_data[61]
  PIN a_data[62]
    DIRECTION OUTPUT ;
    USE SIGNAL ;
    PORT
      LAYER M5 ;
        RECT  20.304 0 20.328 0.084 ;
    END
  END a_data[62]
  PIN a_data[63]
    DIRECTION OUTPUT ;
    USE SIGNAL ;
    PORT
      LAYER M5 ;
        RECT  20.448 0 20.472 0.084 ;
    END
  END a_data[63]
  PIN a_data[64]
    DIRECTION OUTPUT ;
    USE SIGNAL ;
    PORT
      LAYER M5 ;
        RECT  20.592 0 20.616 0.084 ;
    END
  END a_data[64]
  PIN a_data[65]
    DIRECTION OUTPUT ;
    USE SIGNAL ;
    PORT
      LAYER M5 ;
        RECT  20.736 0 20.76 0.084 ;
    END
  END a_data[65]
  PIN a_data[66]
    DIRECTION OUTPUT ;
    USE SIGNAL ;
    PORT
      LAYER M5 ;
        RECT  20.88 0 20.904 0.084 ;
    END
  END a_data[66]
  PIN a_data[67]
    DIRECTION OUTPUT ;
    USE SIGNAL ;
    PORT
      LAYER M5 ;
        RECT  21.024 0 21.048 0.084 ;
    END
  END a_data[67]
  PIN a_data[68]
    DIRECTION OUTPUT ;
    USE SIGNAL ;
    PORT
      LAYER M5 ;
        RECT  21.168 0 21.192 0.084 ;
    END
  END a_data[68]
  PIN a_data[69]
    DIRECTION OUTPUT ;
    USE SIGNAL ;
    PORT
      LAYER M5 ;
        RECT  21.312 0 21.336 0.084 ;
    END
  END a_data[69]
  PIN a_data[6]
    DIRECTION OUTPUT ;
    USE SIGNAL ;
    PORT
      LAYER M5 ;
        RECT  26.064 0 26.088 0.084 ;
    END
  END a_data[6]
  PIN a_data[70]
    DIRECTION OUTPUT ;
    USE SIGNAL ;
    PORT
      LAYER M5 ;
        RECT  21.456 0 21.48 0.084 ;
    END
  END a_data[70]
  PIN a_data[71]
    DIRECTION OUTPUT ;
    USE SIGNAL ;
    PORT
      LAYER M5 ;
        RECT  21.6 0 21.624 0.084 ;
    END
  END a_data[71]
  PIN a_data[72]
    DIRECTION OUTPUT ;
    USE SIGNAL ;
    PORT
      LAYER M5 ;
        RECT  21.744 0 21.768 0.084 ;
    END
  END a_data[72]
  PIN a_data[73]
    DIRECTION OUTPUT ;
    USE SIGNAL ;
    PORT
      LAYER M5 ;
        RECT  21.888 0 21.912 0.084 ;
    END
  END a_data[73]
  PIN a_data[74]
    DIRECTION OUTPUT ;
    USE SIGNAL ;
    PORT
      LAYER M5 ;
        RECT  22.032 0 22.056 0.084 ;
    END
  END a_data[74]
  PIN a_data[75]
    DIRECTION OUTPUT ;
    USE SIGNAL ;
    PORT
      LAYER M5 ;
        RECT  22.176 0 22.2 0.084 ;
    END
  END a_data[75]
  PIN a_data[76]
    DIRECTION OUTPUT ;
    USE SIGNAL ;
    PORT
      LAYER M5 ;
        RECT  22.32 0 22.344 0.084 ;
    END
  END a_data[76]
  PIN a_data[77]
    DIRECTION OUTPUT ;
    USE SIGNAL ;
    PORT
      LAYER M5 ;
        RECT  22.464 0 22.488 0.084 ;
    END
  END a_data[77]
  PIN a_data[78]
    DIRECTION OUTPUT ;
    USE SIGNAL ;
    PORT
      LAYER M5 ;
        RECT  22.608 0 22.632 0.084 ;
    END
  END a_data[78]
  PIN a_data[79]
    DIRECTION OUTPUT ;
    USE SIGNAL ;
    PORT
      LAYER M5 ;
        RECT  22.752 0 22.776 0.084 ;
    END
  END a_data[79]
  PIN a_data[7]
    DIRECTION OUTPUT ;
    USE SIGNAL ;
    PORT
      LAYER M5 ;
        RECT  26.208 0 26.232 0.084 ;
    END
  END a_data[7]
  PIN a_data[80]
    DIRECTION OUTPUT ;
    USE SIGNAL ;
    PORT
      LAYER M5 ;
        RECT  22.896 0 22.92 0.084 ;
    END
  END a_data[80]
  PIN a_data[81]
    DIRECTION OUTPUT ;
    USE SIGNAL ;
    PORT
      LAYER M5 ;
        RECT  23.04 0 23.064 0.084 ;
    END
  END a_data[81]
  PIN a_data[82]
    DIRECTION OUTPUT ;
    USE SIGNAL ;
    PORT
      LAYER M5 ;
        RECT  23.184 0 23.208 0.084 ;
    END
  END a_data[82]
  PIN a_data[83]
    DIRECTION OUTPUT ;
    USE SIGNAL ;
    PORT
      LAYER M5 ;
        RECT  23.328 0 23.352 0.084 ;
    END
  END a_data[83]
  PIN a_data[84]
    DIRECTION OUTPUT ;
    USE SIGNAL ;
    PORT
      LAYER M5 ;
        RECT  23.472 0 23.496 0.084 ;
    END
  END a_data[84]
  PIN a_data[85]
    DIRECTION OUTPUT ;
    USE SIGNAL ;
    PORT
      LAYER M5 ;
        RECT  23.616 0 23.64 0.084 ;
    END
  END a_data[85]
  PIN a_data[86]
    DIRECTION OUTPUT ;
    USE SIGNAL ;
    PORT
      LAYER M5 ;
        RECT  38.736 0 38.76 0.084 ;
    END
  END a_data[86]
  PIN a_data[87]
    DIRECTION OUTPUT ;
    USE SIGNAL ;
    PORT
      LAYER M5 ;
        RECT  38.88 0 38.904 0.084 ;
    END
  END a_data[87]
  PIN a_data[88]
    DIRECTION OUTPUT ;
    USE SIGNAL ;
    PORT
      LAYER M5 ;
        RECT  39.024 0 39.048 0.084 ;
    END
  END a_data[88]
  PIN a_data[89]
    DIRECTION OUTPUT ;
    USE SIGNAL ;
    PORT
      LAYER M5 ;
        RECT  39.168 0 39.192 0.084 ;
    END
  END a_data[89]
  PIN a_data[8]
    DIRECTION OUTPUT ;
    USE SIGNAL ;
    PORT
      LAYER M5 ;
        RECT  26.352 0 26.376 0.084 ;
    END
  END a_data[8]
  PIN a_data[90]
    DIRECTION OUTPUT ;
    USE SIGNAL ;
    PORT
      LAYER M5 ;
        RECT  39.312 0 39.336 0.084 ;
    END
  END a_data[90]
  PIN a_data[91]
    DIRECTION OUTPUT ;
    USE SIGNAL ;
    PORT
      LAYER M5 ;
        RECT  39.456 0 39.48 0.084 ;
    END
  END a_data[91]
  PIN a_data[92]
    DIRECTION OUTPUT ;
    USE SIGNAL ;
    PORT
      LAYER M5 ;
        RECT  39.6 0 39.624 0.084 ;
    END
  END a_data[92]
  PIN a_data[93]
    DIRECTION OUTPUT ;
    USE SIGNAL ;
    PORT
      LAYER M5 ;
        RECT  39.744 0 39.768 0.084 ;
    END
  END a_data[93]
  PIN a_data[94]
    DIRECTION OUTPUT ;
    USE SIGNAL ;
    PORT
      LAYER M5 ;
        RECT  39.888 0 39.912 0.084 ;
    END
  END a_data[94]
  PIN a_data[95]
    DIRECTION OUTPUT ;
    USE SIGNAL ;
    PORT
      LAYER M5 ;
        RECT  40.032 0 40.056 0.084 ;
    END
  END a_data[95]
  PIN a_data[96]
    DIRECTION OUTPUT ;
    USE SIGNAL ;
    PORT
      LAYER M5 ;
        RECT  40.176 0 40.2 0.084 ;
    END
  END a_data[96]
  PIN a_data[97]
    DIRECTION OUTPUT ;
    USE SIGNAL ;
    PORT
      LAYER M5 ;
        RECT  40.32 0 40.344 0.084 ;
    END
  END a_data[97]
  PIN a_data[98]
    DIRECTION OUTPUT ;
    USE SIGNAL ;
    PORT
      LAYER M5 ;
        RECT  40.464 0 40.488 0.084 ;
    END
  END a_data[98]
  PIN a_data[99]
    DIRECTION OUTPUT ;
    USE SIGNAL ;
    PORT
      LAYER M5 ;
        RECT  40.608 0 40.632 0.084 ;
    END
  END a_data[99]
  PIN a_data[9]
    DIRECTION OUTPUT ;
    USE SIGNAL ;
    PORT
      LAYER M5 ;
        RECT  26.496 0 26.52 0.084 ;
    END
  END a_data[9]
  PIN a_we
    DIRECTION OUTPUT ;
    USE SIGNAL ;
    PORT
      LAYER M5 ;
        RECT  6.768 0 6.792 0.084 ;
    END
  END a_we
  PIN active
    DIRECTION OUTPUT ;
    USE SIGNAL ;
    PORT
      LAYER M5 ;
        RECT  26.352 60.396 26.376 60.48 ;
    END
  END active
  PIN b_addr[0]
    DIRECTION OUTPUT ;
    USE SIGNAL ;
    PORT
      LAYER M4 ;
        RECT  60.396 29.52 60.48 29.544 ;
    END
  END b_addr[0]
  PIN b_addr[1]
    DIRECTION OUTPUT ;
    USE SIGNAL ;
    PORT
      LAYER M4 ;
        RECT  60.396 29.664 60.48 29.688 ;
    END
  END b_addr[1]
  PIN b_addr[2]
    DIRECTION OUTPUT ;
    USE SIGNAL ;
    PORT
      LAYER M4 ;
        RECT  60.396 29.808 60.48 29.832 ;
    END
  END b_addr[2]
  PIN b_addr[3]
    DIRECTION OUTPUT ;
    USE SIGNAL ;
    PORT
      LAYER M4 ;
        RECT  60.396 29.952 60.48 29.976 ;
    END
  END b_addr[3]
  PIN b_addr[4]
    DIRECTION OUTPUT ;
    USE SIGNAL ;
    PORT
      LAYER M4 ;
        RECT  60.396 30.096 60.48 30.12 ;
    END
  END b_addr[4]
  PIN b_addr[5]
    DIRECTION OUTPUT ;
    USE SIGNAL ;
    PORT
      LAYER M4 ;
        RECT  60.396 30.24 60.48 30.264 ;
    END
  END b_addr[5]
  PIN b_addr[6]
    DIRECTION OUTPUT ;
    USE SIGNAL ;
    PORT
      LAYER M4 ;
        RECT  60.396 30.384 60.48 30.408 ;
    END
  END b_addr[6]
  PIN b_data[0]
    DIRECTION OUTPUT ;
    USE SIGNAL ;
    PORT
      LAYER M4 ;
        RECT  60.396 30.528 60.48 30.552 ;
    END
  END b_data[0]
  PIN b_data[100]
    DIRECTION OUTPUT ;
    USE SIGNAL ;
    PORT
      LAYER M4 ;
        RECT  60.396 25.344 60.48 25.368 ;
    END
  END b_data[100]
  PIN b_data[101]
    DIRECTION OUTPUT ;
    USE SIGNAL ;
    PORT
      LAYER M4 ;
        RECT  60.396 25.488 60.48 25.512 ;
    END
  END b_data[101]
  PIN b_data[102]
    DIRECTION OUTPUT ;
    USE SIGNAL ;
    PORT
      LAYER M4 ;
        RECT  60.396 25.632 60.48 25.656 ;
    END
  END b_data[102]
  PIN b_data[103]
    DIRECTION OUTPUT ;
    USE SIGNAL ;
    PORT
      LAYER M4 ;
        RECT  60.396 25.776 60.48 25.8 ;
    END
  END b_data[103]
  PIN b_data[104]
    DIRECTION OUTPUT ;
    USE SIGNAL ;
    PORT
      LAYER M4 ;
        RECT  60.396 25.92 60.48 25.944 ;
    END
  END b_data[104]
  PIN b_data[105]
    DIRECTION OUTPUT ;
    USE SIGNAL ;
    PORT
      LAYER M4 ;
        RECT  60.396 26.064 60.48 26.088 ;
    END
  END b_data[105]
  PIN b_data[106]
    DIRECTION OUTPUT ;
    USE SIGNAL ;
    PORT
      LAYER M4 ;
        RECT  60.396 26.208 60.48 26.232 ;
    END
  END b_data[106]
  PIN b_data[107]
    DIRECTION OUTPUT ;
    USE SIGNAL ;
    PORT
      LAYER M4 ;
        RECT  60.396 26.352 60.48 26.376 ;
    END
  END b_data[107]
  PIN b_data[108]
    DIRECTION OUTPUT ;
    USE SIGNAL ;
    PORT
      LAYER M4 ;
        RECT  60.396 26.496 60.48 26.52 ;
    END
  END b_data[108]
  PIN b_data[109]
    DIRECTION OUTPUT ;
    USE SIGNAL ;
    PORT
      LAYER M4 ;
        RECT  60.396 26.64 60.48 26.664 ;
    END
  END b_data[109]
  PIN b_data[10]
    DIRECTION OUTPUT ;
    USE SIGNAL ;
    PORT
      LAYER M4 ;
        RECT  60.396 31.968 60.48 31.992 ;
    END
  END b_data[10]
  PIN b_data[110]
    DIRECTION OUTPUT ;
    USE SIGNAL ;
    PORT
      LAYER M4 ;
        RECT  60.396 26.784 60.48 26.808 ;
    END
  END b_data[110]
  PIN b_data[111]
    DIRECTION OUTPUT ;
    USE SIGNAL ;
    PORT
      LAYER M4 ;
        RECT  60.396 26.928 60.48 26.952 ;
    END
  END b_data[111]
  PIN b_data[112]
    DIRECTION OUTPUT ;
    USE SIGNAL ;
    PORT
      LAYER M4 ;
        RECT  60.396 27.072 60.48 27.096 ;
    END
  END b_data[112]
  PIN b_data[113]
    DIRECTION OUTPUT ;
    USE SIGNAL ;
    PORT
      LAYER M4 ;
        RECT  60.396 27.216 60.48 27.24 ;
    END
  END b_data[113]
  PIN b_data[114]
    DIRECTION OUTPUT ;
    USE SIGNAL ;
    PORT
      LAYER M4 ;
        RECT  60.396 27.36 60.48 27.384 ;
    END
  END b_data[114]
  PIN b_data[115]
    DIRECTION OUTPUT ;
    USE SIGNAL ;
    PORT
      LAYER M4 ;
        RECT  60.396 27.504 60.48 27.528 ;
    END
  END b_data[115]
  PIN b_data[116]
    DIRECTION OUTPUT ;
    USE SIGNAL ;
    PORT
      LAYER M4 ;
        RECT  60.396 27.648 60.48 27.672 ;
    END
  END b_data[116]
  PIN b_data[117]
    DIRECTION OUTPUT ;
    USE SIGNAL ;
    PORT
      LAYER M4 ;
        RECT  60.396 27.792 60.48 27.816 ;
    END
  END b_data[117]
  PIN b_data[118]
    DIRECTION OUTPUT ;
    USE SIGNAL ;
    PORT
      LAYER M4 ;
        RECT  60.396 27.936 60.48 27.96 ;
    END
  END b_data[118]
  PIN b_data[119]
    DIRECTION OUTPUT ;
    USE SIGNAL ;
    PORT
      LAYER M4 ;
        RECT  60.396 28.08 60.48 28.104 ;
    END
  END b_data[119]
  PIN b_data[11]
    DIRECTION OUTPUT ;
    USE SIGNAL ;
    PORT
      LAYER M4 ;
        RECT  60.396 32.112 60.48 32.136 ;
    END
  END b_data[11]
  PIN b_data[120]
    DIRECTION OUTPUT ;
    USE SIGNAL ;
    PORT
      LAYER M4 ;
        RECT  60.396 28.224 60.48 28.248 ;
    END
  END b_data[120]
  PIN b_data[121]
    DIRECTION OUTPUT ;
    USE SIGNAL ;
    PORT
      LAYER M4 ;
        RECT  60.396 19.152 60.48 19.176 ;
    END
  END b_data[121]
  PIN b_data[122]
    DIRECTION OUTPUT ;
    USE SIGNAL ;
    PORT
      LAYER M4 ;
        RECT  60.396 19.296 60.48 19.32 ;
    END
  END b_data[122]
  PIN b_data[123]
    DIRECTION OUTPUT ;
    USE SIGNAL ;
    PORT
      LAYER M4 ;
        RECT  60.396 19.44 60.48 19.464 ;
    END
  END b_data[123]
  PIN b_data[124]
    DIRECTION OUTPUT ;
    USE SIGNAL ;
    PORT
      LAYER M4 ;
        RECT  60.396 19.584 60.48 19.608 ;
    END
  END b_data[124]
  PIN b_data[125]
    DIRECTION OUTPUT ;
    USE SIGNAL ;
    PORT
      LAYER M4 ;
        RECT  60.396 19.728 60.48 19.752 ;
    END
  END b_data[125]
  PIN b_data[126]
    DIRECTION OUTPUT ;
    USE SIGNAL ;
    PORT
      LAYER M4 ;
        RECT  60.396 19.872 60.48 19.896 ;
    END
  END b_data[126]
  PIN b_data[127]
    DIRECTION OUTPUT ;
    USE SIGNAL ;
    PORT
      LAYER M4 ;
        RECT  60.396 20.016 60.48 20.04 ;
    END
  END b_data[127]
  PIN b_data[128]
    DIRECTION OUTPUT ;
    USE SIGNAL ;
    PORT
      LAYER M4 ;
        RECT  60.396 20.16 60.48 20.184 ;
    END
  END b_data[128]
  PIN b_data[129]
    DIRECTION OUTPUT ;
    USE SIGNAL ;
    PORT
      LAYER M4 ;
        RECT  60.396 20.304 60.48 20.328 ;
    END
  END b_data[129]
  PIN b_data[12]
    DIRECTION OUTPUT ;
    USE SIGNAL ;
    PORT
      LAYER M4 ;
        RECT  60.396 32.256 60.48 32.28 ;
    END
  END b_data[12]
  PIN b_data[130]
    DIRECTION OUTPUT ;
    USE SIGNAL ;
    PORT
      LAYER M4 ;
        RECT  60.396 20.448 60.48 20.472 ;
    END
  END b_data[130]
  PIN b_data[131]
    DIRECTION OUTPUT ;
    USE SIGNAL ;
    PORT
      LAYER M4 ;
        RECT  60.396 20.592 60.48 20.616 ;
    END
  END b_data[131]
  PIN b_data[132]
    DIRECTION OUTPUT ;
    USE SIGNAL ;
    PORT
      LAYER M4 ;
        RECT  60.396 20.736 60.48 20.76 ;
    END
  END b_data[132]
  PIN b_data[133]
    DIRECTION OUTPUT ;
    USE SIGNAL ;
    PORT
      LAYER M4 ;
        RECT  60.396 20.88 60.48 20.904 ;
    END
  END b_data[133]
  PIN b_data[134]
    DIRECTION OUTPUT ;
    USE SIGNAL ;
    PORT
      LAYER M4 ;
        RECT  60.396 21.024 60.48 21.048 ;
    END
  END b_data[134]
  PIN b_data[135]
    DIRECTION OUTPUT ;
    USE SIGNAL ;
    PORT
      LAYER M4 ;
        RECT  60.396 21.168 60.48 21.192 ;
    END
  END b_data[135]
  PIN b_data[136]
    DIRECTION OUTPUT ;
    USE SIGNAL ;
    PORT
      LAYER M4 ;
        RECT  60.396 21.312 60.48 21.336 ;
    END
  END b_data[136]
  PIN b_data[137]
    DIRECTION OUTPUT ;
    USE SIGNAL ;
    PORT
      LAYER M4 ;
        RECT  60.396 21.456 60.48 21.48 ;
    END
  END b_data[137]
  PIN b_data[138]
    DIRECTION OUTPUT ;
    USE SIGNAL ;
    PORT
      LAYER M4 ;
        RECT  60.396 21.6 60.48 21.624 ;
    END
  END b_data[138]
  PIN b_data[139]
    DIRECTION OUTPUT ;
    USE SIGNAL ;
    PORT
      LAYER M4 ;
        RECT  60.396 21.744 60.48 21.768 ;
    END
  END b_data[139]
  PIN b_data[13]
    DIRECTION OUTPUT ;
    USE SIGNAL ;
    PORT
      LAYER M4 ;
        RECT  60.396 32.4 60.48 32.424 ;
    END
  END b_data[13]
  PIN b_data[140]
    DIRECTION OUTPUT ;
    USE SIGNAL ;
    PORT
      LAYER M4 ;
        RECT  60.396 21.888 60.48 21.912 ;
    END
  END b_data[140]
  PIN b_data[141]
    DIRECTION OUTPUT ;
    USE SIGNAL ;
    PORT
      LAYER M4 ;
        RECT  60.396 22.032 60.48 22.056 ;
    END
  END b_data[141]
  PIN b_data[142]
    DIRECTION OUTPUT ;
    USE SIGNAL ;
    PORT
      LAYER M4 ;
        RECT  60.396 22.176 60.48 22.2 ;
    END
  END b_data[142]
  PIN b_data[143]
    DIRECTION OUTPUT ;
    USE SIGNAL ;
    PORT
      LAYER M4 ;
        RECT  60.396 22.32 60.48 22.344 ;
    END
  END b_data[143]
  PIN b_data[144]
    DIRECTION OUTPUT ;
    USE SIGNAL ;
    PORT
      LAYER M4 ;
        RECT  60.396 22.464 60.48 22.488 ;
    END
  END b_data[144]
  PIN b_data[145]
    DIRECTION OUTPUT ;
    USE SIGNAL ;
    PORT
      LAYER M4 ;
        RECT  60.396 22.608 60.48 22.632 ;
    END
  END b_data[145]
  PIN b_data[146]
    DIRECTION OUTPUT ;
    USE SIGNAL ;
    PORT
      LAYER M4 ;
        RECT  60.396 22.752 60.48 22.776 ;
    END
  END b_data[146]
  PIN b_data[147]
    DIRECTION OUTPUT ;
    USE SIGNAL ;
    PORT
      LAYER M4 ;
        RECT  60.396 22.896 60.48 22.92 ;
    END
  END b_data[147]
  PIN b_data[148]
    DIRECTION OUTPUT ;
    USE SIGNAL ;
    PORT
      LAYER M4 ;
        RECT  60.396 23.04 60.48 23.064 ;
    END
  END b_data[148]
  PIN b_data[149]
    DIRECTION OUTPUT ;
    USE SIGNAL ;
    PORT
      LAYER M4 ;
        RECT  60.396 23.184 60.48 23.208 ;
    END
  END b_data[149]
  PIN b_data[14]
    DIRECTION OUTPUT ;
    USE SIGNAL ;
    PORT
      LAYER M4 ;
        RECT  60.396 32.544 60.48 32.568 ;
    END
  END b_data[14]
  PIN b_data[150]
    DIRECTION OUTPUT ;
    USE SIGNAL ;
    PORT
      LAYER M4 ;
        RECT  60.396 23.328 60.48 23.352 ;
    END
  END b_data[150]
  PIN b_data[151]
    DIRECTION OUTPUT ;
    USE SIGNAL ;
    PORT
      LAYER M4 ;
        RECT  60.396 23.472 60.48 23.496 ;
    END
  END b_data[151]
  PIN b_data[152]
    DIRECTION OUTPUT ;
    USE SIGNAL ;
    PORT
      LAYER M4 ;
        RECT  60.396 23.616 60.48 23.64 ;
    END
  END b_data[152]
  PIN b_data[153]
    DIRECTION OUTPUT ;
    USE SIGNAL ;
    PORT
      LAYER M4 ;
        RECT  60.396 34.128 60.48 34.152 ;
    END
  END b_data[153]
  PIN b_data[154]
    DIRECTION OUTPUT ;
    USE SIGNAL ;
    PORT
      LAYER M4 ;
        RECT  60.396 34.272 60.48 34.296 ;
    END
  END b_data[154]
  PIN b_data[155]
    DIRECTION OUTPUT ;
    USE SIGNAL ;
    PORT
      LAYER M4 ;
        RECT  60.396 34.416 60.48 34.44 ;
    END
  END b_data[155]
  PIN b_data[156]
    DIRECTION OUTPUT ;
    USE SIGNAL ;
    PORT
      LAYER M4 ;
        RECT  60.396 34.56 60.48 34.584 ;
    END
  END b_data[156]
  PIN b_data[157]
    DIRECTION OUTPUT ;
    USE SIGNAL ;
    PORT
      LAYER M4 ;
        RECT  60.396 34.704 60.48 34.728 ;
    END
  END b_data[157]
  PIN b_data[158]
    DIRECTION OUTPUT ;
    USE SIGNAL ;
    PORT
      LAYER M4 ;
        RECT  60.396 34.848 60.48 34.872 ;
    END
  END b_data[158]
  PIN b_data[159]
    DIRECTION OUTPUT ;
    USE SIGNAL ;
    PORT
      LAYER M4 ;
        RECT  60.396 34.992 60.48 35.016 ;
    END
  END b_data[159]
  PIN b_data[15]
    DIRECTION OUTPUT ;
    USE SIGNAL ;
    PORT
      LAYER M4 ;
        RECT  60.396 32.688 60.48 32.712 ;
    END
  END b_data[15]
  PIN b_data[160]
    DIRECTION OUTPUT ;
    USE SIGNAL ;
    PORT
      LAYER M4 ;
        RECT  60.396 35.136 60.48 35.16 ;
    END
  END b_data[160]
  PIN b_data[161]
    DIRECTION OUTPUT ;
    USE SIGNAL ;
    PORT
      LAYER M4 ;
        RECT  60.396 35.28 60.48 35.304 ;
    END
  END b_data[161]
  PIN b_data[162]
    DIRECTION OUTPUT ;
    USE SIGNAL ;
    PORT
      LAYER M4 ;
        RECT  60.396 35.424 60.48 35.448 ;
    END
  END b_data[162]
  PIN b_data[163]
    DIRECTION OUTPUT ;
    USE SIGNAL ;
    PORT
      LAYER M4 ;
        RECT  60.396 35.568 60.48 35.592 ;
    END
  END b_data[163]
  PIN b_data[164]
    DIRECTION OUTPUT ;
    USE SIGNAL ;
    PORT
      LAYER M4 ;
        RECT  60.396 35.712 60.48 35.736 ;
    END
  END b_data[164]
  PIN b_data[165]
    DIRECTION OUTPUT ;
    USE SIGNAL ;
    PORT
      LAYER M4 ;
        RECT  60.396 35.856 60.48 35.88 ;
    END
  END b_data[165]
  PIN b_data[166]
    DIRECTION OUTPUT ;
    USE SIGNAL ;
    PORT
      LAYER M4 ;
        RECT  60.396 36 60.48 36.024 ;
    END
  END b_data[166]
  PIN b_data[167]
    DIRECTION OUTPUT ;
    USE SIGNAL ;
    PORT
      LAYER M4 ;
        RECT  60.396 36.144 60.48 36.168 ;
    END
  END b_data[167]
  PIN b_data[168]
    DIRECTION OUTPUT ;
    USE SIGNAL ;
    PORT
      LAYER M4 ;
        RECT  60.396 36.288 60.48 36.312 ;
    END
  END b_data[168]
  PIN b_data[169]
    DIRECTION OUTPUT ;
    USE SIGNAL ;
    PORT
      LAYER M4 ;
        RECT  60.396 36.432 60.48 36.456 ;
    END
  END b_data[169]
  PIN b_data[16]
    DIRECTION OUTPUT ;
    USE SIGNAL ;
    PORT
      LAYER M4 ;
        RECT  60.396 32.832 60.48 32.856 ;
    END
  END b_data[16]
  PIN b_data[170]
    DIRECTION OUTPUT ;
    USE SIGNAL ;
    PORT
      LAYER M4 ;
        RECT  60.396 36.576 60.48 36.6 ;
    END
  END b_data[170]
  PIN b_data[171]
    DIRECTION OUTPUT ;
    USE SIGNAL ;
    PORT
      LAYER M4 ;
        RECT  60.396 36.72 60.48 36.744 ;
    END
  END b_data[171]
  PIN b_data[172]
    DIRECTION OUTPUT ;
    USE SIGNAL ;
    PORT
      LAYER M4 ;
        RECT  60.396 36.864 60.48 36.888 ;
    END
  END b_data[172]
  PIN b_data[173]
    DIRECTION OUTPUT ;
    USE SIGNAL ;
    PORT
      LAYER M4 ;
        RECT  60.396 37.008 60.48 37.032 ;
    END
  END b_data[173]
  PIN b_data[174]
    DIRECTION OUTPUT ;
    USE SIGNAL ;
    PORT
      LAYER M4 ;
        RECT  60.396 37.152 60.48 37.176 ;
    END
  END b_data[174]
  PIN b_data[175]
    DIRECTION OUTPUT ;
    USE SIGNAL ;
    PORT
      LAYER M4 ;
        RECT  60.396 37.296 60.48 37.32 ;
    END
  END b_data[175]
  PIN b_data[176]
    DIRECTION OUTPUT ;
    USE SIGNAL ;
    PORT
      LAYER M4 ;
        RECT  60.396 37.44 60.48 37.464 ;
    END
  END b_data[176]
  PIN b_data[177]
    DIRECTION OUTPUT ;
    USE SIGNAL ;
    PORT
      LAYER M4 ;
        RECT  60.396 37.584 60.48 37.608 ;
    END
  END b_data[177]
  PIN b_data[178]
    DIRECTION OUTPUT ;
    USE SIGNAL ;
    PORT
      LAYER M4 ;
        RECT  60.396 37.728 60.48 37.752 ;
    END
  END b_data[178]
  PIN b_data[179]
    DIRECTION OUTPUT ;
    USE SIGNAL ;
    PORT
      LAYER M4 ;
        RECT  60.396 37.872 60.48 37.896 ;
    END
  END b_data[179]
  PIN b_data[17]
    DIRECTION OUTPUT ;
    USE SIGNAL ;
    PORT
      LAYER M4 ;
        RECT  60.396 32.976 60.48 33 ;
    END
  END b_data[17]
  PIN b_data[180]
    DIRECTION OUTPUT ;
    USE SIGNAL ;
    PORT
      LAYER M4 ;
        RECT  60.396 38.016 60.48 38.04 ;
    END
  END b_data[180]
  PIN b_data[181]
    DIRECTION OUTPUT ;
    USE SIGNAL ;
    PORT
      LAYER M4 ;
        RECT  60.396 38.16 60.48 38.184 ;
    END
  END b_data[181]
  PIN b_data[182]
    DIRECTION OUTPUT ;
    USE SIGNAL ;
    PORT
      LAYER M4 ;
        RECT  60.396 38.304 60.48 38.328 ;
    END
  END b_data[182]
  PIN b_data[183]
    DIRECTION OUTPUT ;
    USE SIGNAL ;
    PORT
      LAYER M4 ;
        RECT  60.396 38.448 60.48 38.472 ;
    END
  END b_data[183]
  PIN b_data[184]
    DIRECTION OUTPUT ;
    USE SIGNAL ;
    PORT
      LAYER M4 ;
        RECT  60.396 38.592 60.48 38.616 ;
    END
  END b_data[184]
  PIN b_data[185]
    DIRECTION OUTPUT ;
    USE SIGNAL ;
    PORT
      LAYER M4 ;
        RECT  60.396 43.344 60.48 43.368 ;
    END
  END b_data[185]
  PIN b_data[186]
    DIRECTION OUTPUT ;
    USE SIGNAL ;
    PORT
      LAYER M4 ;
        RECT  60.396 43.488 60.48 43.512 ;
    END
  END b_data[186]
  PIN b_data[187]
    DIRECTION OUTPUT ;
    USE SIGNAL ;
    PORT
      LAYER M4 ;
        RECT  60.396 43.632 60.48 43.656 ;
    END
  END b_data[187]
  PIN b_data[188]
    DIRECTION OUTPUT ;
    USE SIGNAL ;
    PORT
      LAYER M4 ;
        RECT  60.396 43.776 60.48 43.8 ;
    END
  END b_data[188]
  PIN b_data[189]
    DIRECTION OUTPUT ;
    USE SIGNAL ;
    PORT
      LAYER M4 ;
        RECT  60.396 43.92 60.48 43.944 ;
    END
  END b_data[189]
  PIN b_data[18]
    DIRECTION OUTPUT ;
    USE SIGNAL ;
    PORT
      LAYER M4 ;
        RECT  60.396 33.12 60.48 33.144 ;
    END
  END b_data[18]
  PIN b_data[190]
    DIRECTION OUTPUT ;
    USE SIGNAL ;
    PORT
      LAYER M4 ;
        RECT  60.396 44.064 60.48 44.088 ;
    END
  END b_data[190]
  PIN b_data[191]
    DIRECTION OUTPUT ;
    USE SIGNAL ;
    PORT
      LAYER M4 ;
        RECT  60.396 44.208 60.48 44.232 ;
    END
  END b_data[191]
  PIN b_data[192]
    DIRECTION OUTPUT ;
    USE SIGNAL ;
    PORT
      LAYER M4 ;
        RECT  60.396 44.352 60.48 44.376 ;
    END
  END b_data[192]
  PIN b_data[193]
    DIRECTION OUTPUT ;
    USE SIGNAL ;
    PORT
      LAYER M4 ;
        RECT  60.396 44.496 60.48 44.52 ;
    END
  END b_data[193]
  PIN b_data[194]
    DIRECTION OUTPUT ;
    USE SIGNAL ;
    PORT
      LAYER M4 ;
        RECT  60.396 44.64 60.48 44.664 ;
    END
  END b_data[194]
  PIN b_data[195]
    DIRECTION OUTPUT ;
    USE SIGNAL ;
    PORT
      LAYER M4 ;
        RECT  60.396 44.784 60.48 44.808 ;
    END
  END b_data[195]
  PIN b_data[196]
    DIRECTION OUTPUT ;
    USE SIGNAL ;
    PORT
      LAYER M4 ;
        RECT  60.396 44.928 60.48 44.952 ;
    END
  END b_data[196]
  PIN b_data[197]
    DIRECTION OUTPUT ;
    USE SIGNAL ;
    PORT
      LAYER M4 ;
        RECT  60.396 45.072 60.48 45.096 ;
    END
  END b_data[197]
  PIN b_data[198]
    DIRECTION OUTPUT ;
    USE SIGNAL ;
    PORT
      LAYER M4 ;
        RECT  60.396 45.216 60.48 45.24 ;
    END
  END b_data[198]
  PIN b_data[199]
    DIRECTION OUTPUT ;
    USE SIGNAL ;
    PORT
      LAYER M4 ;
        RECT  60.396 45.36 60.48 45.384 ;
    END
  END b_data[199]
  PIN b_data[19]
    DIRECTION OUTPUT ;
    USE SIGNAL ;
    PORT
      LAYER M4 ;
        RECT  60.396 33.264 60.48 33.288 ;
    END
  END b_data[19]
  PIN b_data[1]
    DIRECTION OUTPUT ;
    USE SIGNAL ;
    PORT
      LAYER M4 ;
        RECT  60.396 30.672 60.48 30.696 ;
    END
  END b_data[1]
  PIN b_data[200]
    DIRECTION OUTPUT ;
    USE SIGNAL ;
    PORT
      LAYER M4 ;
        RECT  60.396 45.504 60.48 45.528 ;
    END
  END b_data[200]
  PIN b_data[201]
    DIRECTION OUTPUT ;
    USE SIGNAL ;
    PORT
      LAYER M4 ;
        RECT  60.396 45.648 60.48 45.672 ;
    END
  END b_data[201]
  PIN b_data[202]
    DIRECTION OUTPUT ;
    USE SIGNAL ;
    PORT
      LAYER M4 ;
        RECT  60.396 45.792 60.48 45.816 ;
    END
  END b_data[202]
  PIN b_data[203]
    DIRECTION OUTPUT ;
    USE SIGNAL ;
    PORT
      LAYER M4 ;
        RECT  60.396 45.936 60.48 45.96 ;
    END
  END b_data[203]
  PIN b_data[204]
    DIRECTION OUTPUT ;
    USE SIGNAL ;
    PORT
      LAYER M4 ;
        RECT  60.396 46.08 60.48 46.104 ;
    END
  END b_data[204]
  PIN b_data[205]
    DIRECTION OUTPUT ;
    USE SIGNAL ;
    PORT
      LAYER M4 ;
        RECT  60.396 46.224 60.48 46.248 ;
    END
  END b_data[205]
  PIN b_data[206]
    DIRECTION OUTPUT ;
    USE SIGNAL ;
    PORT
      LAYER M4 ;
        RECT  60.396 46.368 60.48 46.392 ;
    END
  END b_data[206]
  PIN b_data[207]
    DIRECTION OUTPUT ;
    USE SIGNAL ;
    PORT
      LAYER M4 ;
        RECT  60.396 46.512 60.48 46.536 ;
    END
  END b_data[207]
  PIN b_data[208]
    DIRECTION OUTPUT ;
    USE SIGNAL ;
    PORT
      LAYER M4 ;
        RECT  60.396 46.656 60.48 46.68 ;
    END
  END b_data[208]
  PIN b_data[209]
    DIRECTION OUTPUT ;
    USE SIGNAL ;
    PORT
      LAYER M4 ;
        RECT  60.396 46.8 60.48 46.824 ;
    END
  END b_data[209]
  PIN b_data[20]
    DIRECTION OUTPUT ;
    USE SIGNAL ;
    PORT
      LAYER M4 ;
        RECT  60.396 33.408 60.48 33.432 ;
    END
  END b_data[20]
  PIN b_data[210]
    DIRECTION OUTPUT ;
    USE SIGNAL ;
    PORT
      LAYER M4 ;
        RECT  60.396 46.944 60.48 46.968 ;
    END
  END b_data[210]
  PIN b_data[211]
    DIRECTION OUTPUT ;
    USE SIGNAL ;
    PORT
      LAYER M4 ;
        RECT  60.396 47.088 60.48 47.112 ;
    END
  END b_data[211]
  PIN b_data[212]
    DIRECTION OUTPUT ;
    USE SIGNAL ;
    PORT
      LAYER M4 ;
        RECT  60.396 47.232 60.48 47.256 ;
    END
  END b_data[212]
  PIN b_data[213]
    DIRECTION OUTPUT ;
    USE SIGNAL ;
    PORT
      LAYER M4 ;
        RECT  60.396 47.376 60.48 47.4 ;
    END
  END b_data[213]
  PIN b_data[214]
    DIRECTION OUTPUT ;
    USE SIGNAL ;
    PORT
      LAYER M4 ;
        RECT  60.396 47.52 60.48 47.544 ;
    END
  END b_data[214]
  PIN b_data[215]
    DIRECTION OUTPUT ;
    USE SIGNAL ;
    PORT
      LAYER M4 ;
        RECT  60.396 47.664 60.48 47.688 ;
    END
  END b_data[215]
  PIN b_data[216]
    DIRECTION OUTPUT ;
    USE SIGNAL ;
    PORT
      LAYER M4 ;
        RECT  60.396 47.808 60.48 47.832 ;
    END
  END b_data[216]
  PIN b_data[217]
    DIRECTION OUTPUT ;
    USE SIGNAL ;
    PORT
      LAYER M4 ;
        RECT  60.396 47.952 60.48 47.976 ;
    END
  END b_data[217]
  PIN b_data[218]
    DIRECTION OUTPUT ;
    USE SIGNAL ;
    PORT
      LAYER M4 ;
        RECT  60.396 48.096 60.48 48.12 ;
    END
  END b_data[218]
  PIN b_data[219]
    DIRECTION OUTPUT ;
    USE SIGNAL ;
    PORT
      LAYER M4 ;
        RECT  60.396 48.24 60.48 48.264 ;
    END
  END b_data[219]
  PIN b_data[21]
    DIRECTION OUTPUT ;
    USE SIGNAL ;
    PORT
      LAYER M4 ;
        RECT  60.396 33.552 60.48 33.576 ;
    END
  END b_data[21]
  PIN b_data[220]
    DIRECTION OUTPUT ;
    USE SIGNAL ;
    PORT
      LAYER M4 ;
        RECT  60.396 48.384 60.48 48.408 ;
    END
  END b_data[220]
  PIN b_data[221]
    DIRECTION OUTPUT ;
    USE SIGNAL ;
    PORT
      LAYER M4 ;
        RECT  60.396 48.528 60.48 48.552 ;
    END
  END b_data[221]
  PIN b_data[222]
    DIRECTION OUTPUT ;
    USE SIGNAL ;
    PORT
      LAYER M4 ;
        RECT  60.396 48.672 60.48 48.696 ;
    END
  END b_data[222]
  PIN b_data[223]
    DIRECTION OUTPUT ;
    USE SIGNAL ;
    PORT
      LAYER M4 ;
        RECT  60.396 48.816 60.48 48.84 ;
    END
  END b_data[223]
  PIN b_data[224]
    DIRECTION OUTPUT ;
    USE SIGNAL ;
    PORT
      LAYER M4 ;
        RECT  60.396 48.96 60.48 48.984 ;
    END
  END b_data[224]
  PIN b_data[225]
    DIRECTION OUTPUT ;
    USE SIGNAL ;
    PORT
      LAYER M4 ;
        RECT  60.396 49.104 60.48 49.128 ;
    END
  END b_data[225]
  PIN b_data[226]
    DIRECTION OUTPUT ;
    USE SIGNAL ;
    PORT
      LAYER M4 ;
        RECT  60.396 49.248 60.48 49.272 ;
    END
  END b_data[226]
  PIN b_data[227]
    DIRECTION OUTPUT ;
    USE SIGNAL ;
    PORT
      LAYER M4 ;
        RECT  60.396 49.392 60.48 49.416 ;
    END
  END b_data[227]
  PIN b_data[228]
    DIRECTION OUTPUT ;
    USE SIGNAL ;
    PORT
      LAYER M4 ;
        RECT  60.396 49.536 60.48 49.56 ;
    END
  END b_data[228]
  PIN b_data[229]
    DIRECTION OUTPUT ;
    USE SIGNAL ;
    PORT
      LAYER M4 ;
        RECT  60.396 49.68 60.48 49.704 ;
    END
  END b_data[229]
  PIN b_data[22]
    DIRECTION OUTPUT ;
    USE SIGNAL ;
    PORT
      LAYER M4 ;
        RECT  60.396 33.696 60.48 33.72 ;
    END
  END b_data[22]
  PIN b_data[230]
    DIRECTION OUTPUT ;
    USE SIGNAL ;
    PORT
      LAYER M4 ;
        RECT  60.396 49.824 60.48 49.848 ;
    END
  END b_data[230]
  PIN b_data[231]
    DIRECTION OUTPUT ;
    USE SIGNAL ;
    PORT
      LAYER M4 ;
        RECT  60.396 49.968 60.48 49.992 ;
    END
  END b_data[231]
  PIN b_data[232]
    DIRECTION OUTPUT ;
    USE SIGNAL ;
    PORT
      LAYER M4 ;
        RECT  60.396 50.112 60.48 50.136 ;
    END
  END b_data[232]
  PIN b_data[233]
    DIRECTION OUTPUT ;
    USE SIGNAL ;
    PORT
      LAYER M4 ;
        RECT  60.396 50.256 60.48 50.28 ;
    END
  END b_data[233]
  PIN b_data[234]
    DIRECTION OUTPUT ;
    USE SIGNAL ;
    PORT
      LAYER M4 ;
        RECT  60.396 50.4 60.48 50.424 ;
    END
  END b_data[234]
  PIN b_data[235]
    DIRECTION OUTPUT ;
    USE SIGNAL ;
    PORT
      LAYER M4 ;
        RECT  60.396 50.544 60.48 50.568 ;
    END
  END b_data[235]
  PIN b_data[236]
    DIRECTION OUTPUT ;
    USE SIGNAL ;
    PORT
      LAYER M4 ;
        RECT  60.396 50.688 60.48 50.712 ;
    END
  END b_data[236]
  PIN b_data[237]
    DIRECTION OUTPUT ;
    USE SIGNAL ;
    PORT
      LAYER M4 ;
        RECT  60.396 50.832 60.48 50.856 ;
    END
  END b_data[237]
  PIN b_data[238]
    DIRECTION OUTPUT ;
    USE SIGNAL ;
    PORT
      LAYER M4 ;
        RECT  60.396 50.976 60.48 51 ;
    END
  END b_data[238]
  PIN b_data[239]
    DIRECTION OUTPUT ;
    USE SIGNAL ;
    PORT
      LAYER M4 ;
        RECT  60.396 51.12 60.48 51.144 ;
    END
  END b_data[239]
  PIN b_data[23]
    DIRECTION OUTPUT ;
    USE SIGNAL ;
    PORT
      LAYER M4 ;
        RECT  60.396 33.84 60.48 33.864 ;
    END
  END b_data[23]
  PIN b_data[240]
    DIRECTION OUTPUT ;
    USE SIGNAL ;
    PORT
      LAYER M4 ;
        RECT  60.396 51.264 60.48 51.288 ;
    END
  END b_data[240]
  PIN b_data[241]
    DIRECTION OUTPUT ;
    USE SIGNAL ;
    PORT
      LAYER M4 ;
        RECT  60.396 51.408 60.48 51.432 ;
    END
  END b_data[241]
  PIN b_data[242]
    DIRECTION OUTPUT ;
    USE SIGNAL ;
    PORT
      LAYER M4 ;
        RECT  60.396 51.552 60.48 51.576 ;
    END
  END b_data[242]
  PIN b_data[243]
    DIRECTION OUTPUT ;
    USE SIGNAL ;
    PORT
      LAYER M4 ;
        RECT  60.396 51.696 60.48 51.72 ;
    END
  END b_data[243]
  PIN b_data[244]
    DIRECTION OUTPUT ;
    USE SIGNAL ;
    PORT
      LAYER M4 ;
        RECT  60.396 51.84 60.48 51.864 ;
    END
  END b_data[244]
  PIN b_data[245]
    DIRECTION OUTPUT ;
    USE SIGNAL ;
    PORT
      LAYER M4 ;
        RECT  60.396 51.984 60.48 52.008 ;
    END
  END b_data[245]
  PIN b_data[246]
    DIRECTION OUTPUT ;
    USE SIGNAL ;
    PORT
      LAYER M4 ;
        RECT  60.396 52.128 60.48 52.152 ;
    END
  END b_data[246]
  PIN b_data[247]
    DIRECTION OUTPUT ;
    USE SIGNAL ;
    PORT
      LAYER M4 ;
        RECT  60.396 52.272 60.48 52.296 ;
    END
  END b_data[247]
  PIN b_data[248]
    DIRECTION OUTPUT ;
    USE SIGNAL ;
    PORT
      LAYER M4 ;
        RECT  60.396 52.416 60.48 52.44 ;
    END
  END b_data[248]
  PIN b_data[249]
    DIRECTION OUTPUT ;
    USE SIGNAL ;
    PORT
      LAYER M4 ;
        RECT  60.396 38.736 60.48 38.76 ;
    END
  END b_data[249]
  PIN b_data[24]
    DIRECTION OUTPUT ;
    USE SIGNAL ;
    PORT
      LAYER M4 ;
        RECT  60.396 33.984 60.48 34.008 ;
    END
  END b_data[24]
  PIN b_data[250]
    DIRECTION OUTPUT ;
    USE SIGNAL ;
    PORT
      LAYER M4 ;
        RECT  60.396 38.88 60.48 38.904 ;
    END
  END b_data[250]
  PIN b_data[251]
    DIRECTION OUTPUT ;
    USE SIGNAL ;
    PORT
      LAYER M4 ;
        RECT  60.396 39.024 60.48 39.048 ;
    END
  END b_data[251]
  PIN b_data[252]
    DIRECTION OUTPUT ;
    USE SIGNAL ;
    PORT
      LAYER M4 ;
        RECT  60.396 39.168 60.48 39.192 ;
    END
  END b_data[252]
  PIN b_data[253]
    DIRECTION OUTPUT ;
    USE SIGNAL ;
    PORT
      LAYER M4 ;
        RECT  60.396 39.312 60.48 39.336 ;
    END
  END b_data[253]
  PIN b_data[254]
    DIRECTION OUTPUT ;
    USE SIGNAL ;
    PORT
      LAYER M4 ;
        RECT  60.396 39.456 60.48 39.48 ;
    END
  END b_data[254]
  PIN b_data[255]
    DIRECTION OUTPUT ;
    USE SIGNAL ;
    PORT
      LAYER M4 ;
        RECT  60.396 39.6 60.48 39.624 ;
    END
  END b_data[255]
  PIN b_data[25]
    DIRECTION OUTPUT ;
    USE SIGNAL ;
    PORT
      LAYER M4 ;
        RECT  60.396 14.544 60.48 14.568 ;
    END
  END b_data[25]
  PIN b_data[26]
    DIRECTION OUTPUT ;
    USE SIGNAL ;
    PORT
      LAYER M4 ;
        RECT  60.396 14.688 60.48 14.712 ;
    END
  END b_data[26]
  PIN b_data[27]
    DIRECTION OUTPUT ;
    USE SIGNAL ;
    PORT
      LAYER M4 ;
        RECT  60.396 14.832 60.48 14.856 ;
    END
  END b_data[27]
  PIN b_data[28]
    DIRECTION OUTPUT ;
    USE SIGNAL ;
    PORT
      LAYER M4 ;
        RECT  60.396 14.976 60.48 15 ;
    END
  END b_data[28]
  PIN b_data[29]
    DIRECTION OUTPUT ;
    USE SIGNAL ;
    PORT
      LAYER M4 ;
        RECT  60.396 15.12 60.48 15.144 ;
    END
  END b_data[29]
  PIN b_data[2]
    DIRECTION OUTPUT ;
    USE SIGNAL ;
    PORT
      LAYER M4 ;
        RECT  60.396 30.816 60.48 30.84 ;
    END
  END b_data[2]
  PIN b_data[30]
    DIRECTION OUTPUT ;
    USE SIGNAL ;
    PORT
      LAYER M4 ;
        RECT  60.396 15.264 60.48 15.288 ;
    END
  END b_data[30]
  PIN b_data[31]
    DIRECTION OUTPUT ;
    USE SIGNAL ;
    PORT
      LAYER M4 ;
        RECT  60.396 15.408 60.48 15.432 ;
    END
  END b_data[31]
  PIN b_data[32]
    DIRECTION OUTPUT ;
    USE SIGNAL ;
    PORT
      LAYER M4 ;
        RECT  60.396 15.552 60.48 15.576 ;
    END
  END b_data[32]
  PIN b_data[33]
    DIRECTION OUTPUT ;
    USE SIGNAL ;
    PORT
      LAYER M4 ;
        RECT  60.396 15.696 60.48 15.72 ;
    END
  END b_data[33]
  PIN b_data[34]
    DIRECTION OUTPUT ;
    USE SIGNAL ;
    PORT
      LAYER M4 ;
        RECT  60.396 15.84 60.48 15.864 ;
    END
  END b_data[34]
  PIN b_data[35]
    DIRECTION OUTPUT ;
    USE SIGNAL ;
    PORT
      LAYER M4 ;
        RECT  60.396 15.984 60.48 16.008 ;
    END
  END b_data[35]
  PIN b_data[36]
    DIRECTION OUTPUT ;
    USE SIGNAL ;
    PORT
      LAYER M4 ;
        RECT  60.396 16.128 60.48 16.152 ;
    END
  END b_data[36]
  PIN b_data[37]
    DIRECTION OUTPUT ;
    USE SIGNAL ;
    PORT
      LAYER M4 ;
        RECT  60.396 16.272 60.48 16.296 ;
    END
  END b_data[37]
  PIN b_data[38]
    DIRECTION OUTPUT ;
    USE SIGNAL ;
    PORT
      LAYER M4 ;
        RECT  60.396 16.416 60.48 16.44 ;
    END
  END b_data[38]
  PIN b_data[39]
    DIRECTION OUTPUT ;
    USE SIGNAL ;
    PORT
      LAYER M4 ;
        RECT  60.396 16.56 60.48 16.584 ;
    END
  END b_data[39]
  PIN b_data[3]
    DIRECTION OUTPUT ;
    USE SIGNAL ;
    PORT
      LAYER M4 ;
        RECT  60.396 30.96 60.48 30.984 ;
    END
  END b_data[3]
  PIN b_data[40]
    DIRECTION OUTPUT ;
    USE SIGNAL ;
    PORT
      LAYER M4 ;
        RECT  60.396 16.704 60.48 16.728 ;
    END
  END b_data[40]
  PIN b_data[41]
    DIRECTION OUTPUT ;
    USE SIGNAL ;
    PORT
      LAYER M4 ;
        RECT  60.396 16.848 60.48 16.872 ;
    END
  END b_data[41]
  PIN b_data[42]
    DIRECTION OUTPUT ;
    USE SIGNAL ;
    PORT
      LAYER M4 ;
        RECT  60.396 16.992 60.48 17.016 ;
    END
  END b_data[42]
  PIN b_data[43]
    DIRECTION OUTPUT ;
    USE SIGNAL ;
    PORT
      LAYER M4 ;
        RECT  60.396 17.136 60.48 17.16 ;
    END
  END b_data[43]
  PIN b_data[44]
    DIRECTION OUTPUT ;
    USE SIGNAL ;
    PORT
      LAYER M4 ;
        RECT  60.396 17.28 60.48 17.304 ;
    END
  END b_data[44]
  PIN b_data[45]
    DIRECTION OUTPUT ;
    USE SIGNAL ;
    PORT
      LAYER M4 ;
        RECT  60.396 17.424 60.48 17.448 ;
    END
  END b_data[45]
  PIN b_data[46]
    DIRECTION OUTPUT ;
    USE SIGNAL ;
    PORT
      LAYER M4 ;
        RECT  60.396 17.568 60.48 17.592 ;
    END
  END b_data[46]
  PIN b_data[47]
    DIRECTION OUTPUT ;
    USE SIGNAL ;
    PORT
      LAYER M4 ;
        RECT  60.396 17.712 60.48 17.736 ;
    END
  END b_data[47]
  PIN b_data[48]
    DIRECTION OUTPUT ;
    USE SIGNAL ;
    PORT
      LAYER M4 ;
        RECT  60.396 17.856 60.48 17.88 ;
    END
  END b_data[48]
  PIN b_data[49]
    DIRECTION OUTPUT ;
    USE SIGNAL ;
    PORT
      LAYER M4 ;
        RECT  60.396 18 60.48 18.024 ;
    END
  END b_data[49]
  PIN b_data[4]
    DIRECTION OUTPUT ;
    USE SIGNAL ;
    PORT
      LAYER M4 ;
        RECT  60.396 31.104 60.48 31.128 ;
    END
  END b_data[4]
  PIN b_data[50]
    DIRECTION OUTPUT ;
    USE SIGNAL ;
    PORT
      LAYER M4 ;
        RECT  60.396 18.144 60.48 18.168 ;
    END
  END b_data[50]
  PIN b_data[51]
    DIRECTION OUTPUT ;
    USE SIGNAL ;
    PORT
      LAYER M4 ;
        RECT  60.396 18.288 60.48 18.312 ;
    END
  END b_data[51]
  PIN b_data[52]
    DIRECTION OUTPUT ;
    USE SIGNAL ;
    PORT
      LAYER M4 ;
        RECT  60.396 18.432 60.48 18.456 ;
    END
  END b_data[52]
  PIN b_data[53]
    DIRECTION OUTPUT ;
    USE SIGNAL ;
    PORT
      LAYER M4 ;
        RECT  60.396 18.576 60.48 18.6 ;
    END
  END b_data[53]
  PIN b_data[54]
    DIRECTION OUTPUT ;
    USE SIGNAL ;
    PORT
      LAYER M4 ;
        RECT  60.396 18.72 60.48 18.744 ;
    END
  END b_data[54]
  PIN b_data[55]
    DIRECTION OUTPUT ;
    USE SIGNAL ;
    PORT
      LAYER M4 ;
        RECT  60.396 18.864 60.48 18.888 ;
    END
  END b_data[55]
  PIN b_data[56]
    DIRECTION OUTPUT ;
    USE SIGNAL ;
    PORT
      LAYER M4 ;
        RECT  60.396 19.008 60.48 19.032 ;
    END
  END b_data[56]
  PIN b_data[57]
    DIRECTION OUTPUT ;
    USE SIGNAL ;
    PORT
      LAYER M4 ;
        RECT  60.396 9.936 60.48 9.96 ;
    END
  END b_data[57]
  PIN b_data[58]
    DIRECTION OUTPUT ;
    USE SIGNAL ;
    PORT
      LAYER M4 ;
        RECT  60.396 10.08 60.48 10.104 ;
    END
  END b_data[58]
  PIN b_data[59]
    DIRECTION OUTPUT ;
    USE SIGNAL ;
    PORT
      LAYER M4 ;
        RECT  60.396 10.224 60.48 10.248 ;
    END
  END b_data[59]
  PIN b_data[5]
    DIRECTION OUTPUT ;
    USE SIGNAL ;
    PORT
      LAYER M4 ;
        RECT  60.396 31.248 60.48 31.272 ;
    END
  END b_data[5]
  PIN b_data[60]
    DIRECTION OUTPUT ;
    USE SIGNAL ;
    PORT
      LAYER M4 ;
        RECT  60.396 10.368 60.48 10.392 ;
    END
  END b_data[60]
  PIN b_data[61]
    DIRECTION OUTPUT ;
    USE SIGNAL ;
    PORT
      LAYER M4 ;
        RECT  60.396 10.512 60.48 10.536 ;
    END
  END b_data[61]
  PIN b_data[62]
    DIRECTION OUTPUT ;
    USE SIGNAL ;
    PORT
      LAYER M4 ;
        RECT  60.396 10.656 60.48 10.68 ;
    END
  END b_data[62]
  PIN b_data[63]
    DIRECTION OUTPUT ;
    USE SIGNAL ;
    PORT
      LAYER M4 ;
        RECT  60.396 10.8 60.48 10.824 ;
    END
  END b_data[63]
  PIN b_data[64]
    DIRECTION OUTPUT ;
    USE SIGNAL ;
    PORT
      LAYER M4 ;
        RECT  60.396 10.944 60.48 10.968 ;
    END
  END b_data[64]
  PIN b_data[65]
    DIRECTION OUTPUT ;
    USE SIGNAL ;
    PORT
      LAYER M4 ;
        RECT  60.396 11.088 60.48 11.112 ;
    END
  END b_data[65]
  PIN b_data[66]
    DIRECTION OUTPUT ;
    USE SIGNAL ;
    PORT
      LAYER M4 ;
        RECT  60.396 11.232 60.48 11.256 ;
    END
  END b_data[66]
  PIN b_data[67]
    DIRECTION OUTPUT ;
    USE SIGNAL ;
    PORT
      LAYER M4 ;
        RECT  60.396 11.376 60.48 11.4 ;
    END
  END b_data[67]
  PIN b_data[68]
    DIRECTION OUTPUT ;
    USE SIGNAL ;
    PORT
      LAYER M4 ;
        RECT  60.396 11.52 60.48 11.544 ;
    END
  END b_data[68]
  PIN b_data[69]
    DIRECTION OUTPUT ;
    USE SIGNAL ;
    PORT
      LAYER M4 ;
        RECT  60.396 11.664 60.48 11.688 ;
    END
  END b_data[69]
  PIN b_data[6]
    DIRECTION OUTPUT ;
    USE SIGNAL ;
    PORT
      LAYER M4 ;
        RECT  60.396 31.392 60.48 31.416 ;
    END
  END b_data[6]
  PIN b_data[70]
    DIRECTION OUTPUT ;
    USE SIGNAL ;
    PORT
      LAYER M4 ;
        RECT  60.396 11.808 60.48 11.832 ;
    END
  END b_data[70]
  PIN b_data[71]
    DIRECTION OUTPUT ;
    USE SIGNAL ;
    PORT
      LAYER M4 ;
        RECT  60.396 11.952 60.48 11.976 ;
    END
  END b_data[71]
  PIN b_data[72]
    DIRECTION OUTPUT ;
    USE SIGNAL ;
    PORT
      LAYER M4 ;
        RECT  60.396 12.096 60.48 12.12 ;
    END
  END b_data[72]
  PIN b_data[73]
    DIRECTION OUTPUT ;
    USE SIGNAL ;
    PORT
      LAYER M4 ;
        RECT  60.396 12.24 60.48 12.264 ;
    END
  END b_data[73]
  PIN b_data[74]
    DIRECTION OUTPUT ;
    USE SIGNAL ;
    PORT
      LAYER M4 ;
        RECT  60.396 12.384 60.48 12.408 ;
    END
  END b_data[74]
  PIN b_data[75]
    DIRECTION OUTPUT ;
    USE SIGNAL ;
    PORT
      LAYER M4 ;
        RECT  60.396 12.528 60.48 12.552 ;
    END
  END b_data[75]
  PIN b_data[76]
    DIRECTION OUTPUT ;
    USE SIGNAL ;
    PORT
      LAYER M4 ;
        RECT  60.396 12.672 60.48 12.696 ;
    END
  END b_data[76]
  PIN b_data[77]
    DIRECTION OUTPUT ;
    USE SIGNAL ;
    PORT
      LAYER M4 ;
        RECT  60.396 12.816 60.48 12.84 ;
    END
  END b_data[77]
  PIN b_data[78]
    DIRECTION OUTPUT ;
    USE SIGNAL ;
    PORT
      LAYER M4 ;
        RECT  60.396 12.96 60.48 12.984 ;
    END
  END b_data[78]
  PIN b_data[79]
    DIRECTION OUTPUT ;
    USE SIGNAL ;
    PORT
      LAYER M4 ;
        RECT  60.396 13.104 60.48 13.128 ;
    END
  END b_data[79]
  PIN b_data[7]
    DIRECTION OUTPUT ;
    USE SIGNAL ;
    PORT
      LAYER M4 ;
        RECT  60.396 31.536 60.48 31.56 ;
    END
  END b_data[7]
  PIN b_data[80]
    DIRECTION OUTPUT ;
    USE SIGNAL ;
    PORT
      LAYER M4 ;
        RECT  60.396 13.248 60.48 13.272 ;
    END
  END b_data[80]
  PIN b_data[81]
    DIRECTION OUTPUT ;
    USE SIGNAL ;
    PORT
      LAYER M4 ;
        RECT  60.396 13.392 60.48 13.416 ;
    END
  END b_data[81]
  PIN b_data[82]
    DIRECTION OUTPUT ;
    USE SIGNAL ;
    PORT
      LAYER M4 ;
        RECT  60.396 13.536 60.48 13.56 ;
    END
  END b_data[82]
  PIN b_data[83]
    DIRECTION OUTPUT ;
    USE SIGNAL ;
    PORT
      LAYER M4 ;
        RECT  60.396 13.68 60.48 13.704 ;
    END
  END b_data[83]
  PIN b_data[84]
    DIRECTION OUTPUT ;
    USE SIGNAL ;
    PORT
      LAYER M4 ;
        RECT  60.396 13.824 60.48 13.848 ;
    END
  END b_data[84]
  PIN b_data[85]
    DIRECTION OUTPUT ;
    USE SIGNAL ;
    PORT
      LAYER M4 ;
        RECT  60.396 13.968 60.48 13.992 ;
    END
  END b_data[85]
  PIN b_data[86]
    DIRECTION OUTPUT ;
    USE SIGNAL ;
    PORT
      LAYER M4 ;
        RECT  60.396 14.112 60.48 14.136 ;
    END
  END b_data[86]
  PIN b_data[87]
    DIRECTION OUTPUT ;
    USE SIGNAL ;
    PORT
      LAYER M4 ;
        RECT  60.396 14.256 60.48 14.28 ;
    END
  END b_data[87]
  PIN b_data[88]
    DIRECTION OUTPUT ;
    USE SIGNAL ;
    PORT
      LAYER M4 ;
        RECT  60.396 14.4 60.48 14.424 ;
    END
  END b_data[88]
  PIN b_data[89]
    DIRECTION OUTPUT ;
    USE SIGNAL ;
    PORT
      LAYER M4 ;
        RECT  60.396 23.76 60.48 23.784 ;
    END
  END b_data[89]
  PIN b_data[8]
    DIRECTION OUTPUT ;
    USE SIGNAL ;
    PORT
      LAYER M4 ;
        RECT  60.396 31.68 60.48 31.704 ;
    END
  END b_data[8]
  PIN b_data[90]
    DIRECTION OUTPUT ;
    USE SIGNAL ;
    PORT
      LAYER M4 ;
        RECT  60.396 23.904 60.48 23.928 ;
    END
  END b_data[90]
  PIN b_data[91]
    DIRECTION OUTPUT ;
    USE SIGNAL ;
    PORT
      LAYER M4 ;
        RECT  60.396 24.048 60.48 24.072 ;
    END
  END b_data[91]
  PIN b_data[92]
    DIRECTION OUTPUT ;
    USE SIGNAL ;
    PORT
      LAYER M4 ;
        RECT  60.396 24.192 60.48 24.216 ;
    END
  END b_data[92]
  PIN b_data[93]
    DIRECTION OUTPUT ;
    USE SIGNAL ;
    PORT
      LAYER M4 ;
        RECT  60.396 24.336 60.48 24.36 ;
    END
  END b_data[93]
  PIN b_data[94]
    DIRECTION OUTPUT ;
    USE SIGNAL ;
    PORT
      LAYER M4 ;
        RECT  60.396 24.48 60.48 24.504 ;
    END
  END b_data[94]
  PIN b_data[95]
    DIRECTION OUTPUT ;
    USE SIGNAL ;
    PORT
      LAYER M4 ;
        RECT  60.396 24.624 60.48 24.648 ;
    END
  END b_data[95]
  PIN b_data[96]
    DIRECTION OUTPUT ;
    USE SIGNAL ;
    PORT
      LAYER M4 ;
        RECT  60.396 24.768 60.48 24.792 ;
    END
  END b_data[96]
  PIN b_data[97]
    DIRECTION OUTPUT ;
    USE SIGNAL ;
    PORT
      LAYER M4 ;
        RECT  60.396 24.912 60.48 24.936 ;
    END
  END b_data[97]
  PIN b_data[98]
    DIRECTION OUTPUT ;
    USE SIGNAL ;
    PORT
      LAYER M4 ;
        RECT  60.396 25.056 60.48 25.08 ;
    END
  END b_data[98]
  PIN b_data[99]
    DIRECTION OUTPUT ;
    USE SIGNAL ;
    PORT
      LAYER M4 ;
        RECT  60.396 25.2 60.48 25.224 ;
    END
  END b_data[99]
  PIN b_data[9]
    DIRECTION OUTPUT ;
    USE SIGNAL ;
    PORT
      LAYER M4 ;
        RECT  60.396 31.824 60.48 31.848 ;
    END
  END b_data[9]
  PIN b_we
    DIRECTION OUTPUT ;
    USE SIGNAL ;
    PORT
      LAYER M4 ;
        RECT  60.396 39.744 60.48 39.768 ;
    END
  END b_we
  PIN cfg_addr[0]
    DIRECTION INPUT ;
    USE SIGNAL ;
    PORT
      LAYER M5 ;
        RECT  26.496 60.396 26.52 60.48 ;
    END
  END cfg_addr[0]
  PIN cfg_addr[10]
    DIRECTION INPUT ;
    USE SIGNAL ;
    PORT
      LAYER M5 ;
        RECT  27.936 60.396 27.96 60.48 ;
    END
  END cfg_addr[10]
  PIN cfg_addr[11]
    DIRECTION INPUT ;
    USE SIGNAL ;
    PORT
      LAYER M5 ;
        RECT  28.08 60.396 28.104 60.48 ;
    END
  END cfg_addr[11]
  PIN cfg_addr[1]
    DIRECTION INPUT ;
    USE SIGNAL ;
    PORT
      LAYER M5 ;
        RECT  26.64 60.396 26.664 60.48 ;
    END
  END cfg_addr[1]
  PIN cfg_addr[2]
    DIRECTION INPUT ;
    USE SIGNAL ;
    PORT
      LAYER M5 ;
        RECT  26.784 60.396 26.808 60.48 ;
    END
  END cfg_addr[2]
  PIN cfg_addr[3]
    DIRECTION INPUT ;
    USE SIGNAL ;
    PORT
      LAYER M5 ;
        RECT  26.928 60.396 26.952 60.48 ;
    END
  END cfg_addr[3]
  PIN cfg_addr[4]
    DIRECTION INPUT ;
    USE SIGNAL ;
    PORT
      LAYER M5 ;
        RECT  27.072 60.396 27.096 60.48 ;
    END
  END cfg_addr[4]
  PIN cfg_addr[5]
    DIRECTION INPUT ;
    USE SIGNAL ;
    PORT
      LAYER M5 ;
        RECT  27.216 60.396 27.24 60.48 ;
    END
  END cfg_addr[5]
  PIN cfg_addr[6]
    DIRECTION INPUT ;
    USE SIGNAL ;
    PORT
      LAYER M5 ;
        RECT  27.36 60.396 27.384 60.48 ;
    END
  END cfg_addr[6]
  PIN cfg_addr[7]
    DIRECTION INPUT ;
    USE SIGNAL ;
    PORT
      LAYER M5 ;
        RECT  27.504 60.396 27.528 60.48 ;
    END
  END cfg_addr[7]
  PIN cfg_addr[8]
    DIRECTION INPUT ;
    USE SIGNAL ;
    PORT
      LAYER M5 ;
        RECT  27.648 60.396 27.672 60.48 ;
    END
  END cfg_addr[8]
  PIN cfg_addr[9]
    DIRECTION INPUT ;
    USE SIGNAL ;
    PORT
      LAYER M5 ;
        RECT  27.792 60.396 27.816 60.48 ;
    END
  END cfg_addr[9]
  PIN cfg_data[0]
    DIRECTION INPUT ;
    USE SIGNAL ;
    PORT
      LAYER M5 ;
        RECT  28.224 60.396 28.248 60.48 ;
    END
  END cfg_data[0]
  PIN cfg_data[100]
    DIRECTION INPUT ;
    USE SIGNAL ;
    PORT
      LAYER M5 ;
        RECT  39.168 60.396 39.192 60.48 ;
    END
  END cfg_data[100]
  PIN cfg_data[101]
    DIRECTION INPUT ;
    USE SIGNAL ;
    PORT
      LAYER M5 ;
        RECT  39.312 60.396 39.336 60.48 ;
    END
  END cfg_data[101]
  PIN cfg_data[102]
    DIRECTION INPUT ;
    USE SIGNAL ;
    PORT
      LAYER M5 ;
        RECT  39.456 60.396 39.48 60.48 ;
    END
  END cfg_data[102]
  PIN cfg_data[103]
    DIRECTION INPUT ;
    USE SIGNAL ;
    PORT
      LAYER M5 ;
        RECT  39.6 60.396 39.624 60.48 ;
    END
  END cfg_data[103]
  PIN cfg_data[104]
    DIRECTION INPUT ;
    USE SIGNAL ;
    PORT
      LAYER M5 ;
        RECT  39.744 60.396 39.768 60.48 ;
    END
  END cfg_data[104]
  PIN cfg_data[105]
    DIRECTION INPUT ;
    USE SIGNAL ;
    PORT
      LAYER M5 ;
        RECT  39.888 60.396 39.912 60.48 ;
    END
  END cfg_data[105]
  PIN cfg_data[106]
    DIRECTION INPUT ;
    USE SIGNAL ;
    PORT
      LAYER M5 ;
        RECT  40.032 60.396 40.056 60.48 ;
    END
  END cfg_data[106]
  PIN cfg_data[107]
    DIRECTION INPUT ;
    USE SIGNAL ;
    PORT
      LAYER M5 ;
        RECT  40.176 60.396 40.2 60.48 ;
    END
  END cfg_data[107]
  PIN cfg_data[108]
    DIRECTION INPUT ;
    USE SIGNAL ;
    PORT
      LAYER M5 ;
        RECT  40.32 60.396 40.344 60.48 ;
    END
  END cfg_data[108]
  PIN cfg_data[109]
    DIRECTION INPUT ;
    USE SIGNAL ;
    PORT
      LAYER M5 ;
        RECT  40.464 60.396 40.488 60.48 ;
    END
  END cfg_data[109]
  PIN cfg_data[10]
    DIRECTION INPUT ;
    USE SIGNAL ;
    PORT
      LAYER M5 ;
        RECT  29.664 60.396 29.688 60.48 ;
    END
  END cfg_data[10]
  PIN cfg_data[110]
    DIRECTION INPUT ;
    USE SIGNAL ;
    PORT
      LAYER M5 ;
        RECT  40.608 60.396 40.632 60.48 ;
    END
  END cfg_data[110]
  PIN cfg_data[111]
    DIRECTION INPUT ;
    USE SIGNAL ;
    PORT
      LAYER M5 ;
        RECT  40.752 60.396 40.776 60.48 ;
    END
  END cfg_data[111]
  PIN cfg_data[112]
    DIRECTION INPUT ;
    USE SIGNAL ;
    PORT
      LAYER M5 ;
        RECT  40.896 60.396 40.92 60.48 ;
    END
  END cfg_data[112]
  PIN cfg_data[113]
    DIRECTION INPUT ;
    USE SIGNAL ;
    PORT
      LAYER M5 ;
        RECT  41.04 60.396 41.064 60.48 ;
    END
  END cfg_data[113]
  PIN cfg_data[114]
    DIRECTION INPUT ;
    USE SIGNAL ;
    PORT
      LAYER M5 ;
        RECT  41.184 60.396 41.208 60.48 ;
    END
  END cfg_data[114]
  PIN cfg_data[115]
    DIRECTION INPUT ;
    USE SIGNAL ;
    PORT
      LAYER M5 ;
        RECT  45.936 60.396 45.96 60.48 ;
    END
  END cfg_data[115]
  PIN cfg_data[116]
    DIRECTION INPUT ;
    USE SIGNAL ;
    PORT
      LAYER M5 ;
        RECT  46.08 60.396 46.104 60.48 ;
    END
  END cfg_data[116]
  PIN cfg_data[117]
    DIRECTION INPUT ;
    USE SIGNAL ;
    PORT
      LAYER M5 ;
        RECT  46.224 60.396 46.248 60.48 ;
    END
  END cfg_data[117]
  PIN cfg_data[118]
    DIRECTION INPUT ;
    USE SIGNAL ;
    PORT
      LAYER M5 ;
        RECT  46.368 60.396 46.392 60.48 ;
    END
  END cfg_data[118]
  PIN cfg_data[119]
    DIRECTION INPUT ;
    USE SIGNAL ;
    PORT
      LAYER M5 ;
        RECT  46.512 60.396 46.536 60.48 ;
    END
  END cfg_data[119]
  PIN cfg_data[11]
    DIRECTION INPUT ;
    USE SIGNAL ;
    PORT
      LAYER M5 ;
        RECT  29.808 60.396 29.832 60.48 ;
    END
  END cfg_data[11]
  PIN cfg_data[120]
    DIRECTION INPUT ;
    USE SIGNAL ;
    PORT
      LAYER M5 ;
        RECT  46.656 60.396 46.68 60.48 ;
    END
  END cfg_data[120]
  PIN cfg_data[121]
    DIRECTION INPUT ;
    USE SIGNAL ;
    PORT
      LAYER M5 ;
        RECT  46.8 60.396 46.824 60.48 ;
    END
  END cfg_data[121]
  PIN cfg_data[122]
    DIRECTION INPUT ;
    USE SIGNAL ;
    PORT
      LAYER M5 ;
        RECT  46.944 60.396 46.968 60.48 ;
    END
  END cfg_data[122]
  PIN cfg_data[123]
    DIRECTION INPUT ;
    USE SIGNAL ;
    PORT
      LAYER M5 ;
        RECT  47.088 60.396 47.112 60.48 ;
    END
  END cfg_data[123]
  PIN cfg_data[124]
    DIRECTION INPUT ;
    USE SIGNAL ;
    PORT
      LAYER M5 ;
        RECT  47.232 60.396 47.256 60.48 ;
    END
  END cfg_data[124]
  PIN cfg_data[125]
    DIRECTION INPUT ;
    USE SIGNAL ;
    PORT
      LAYER M5 ;
        RECT  47.376 60.396 47.4 60.48 ;
    END
  END cfg_data[125]
  PIN cfg_data[126]
    DIRECTION INPUT ;
    USE SIGNAL ;
    PORT
      LAYER M5 ;
        RECT  47.52 60.396 47.544 60.48 ;
    END
  END cfg_data[126]
  PIN cfg_data[127]
    DIRECTION INPUT ;
    USE SIGNAL ;
    PORT
      LAYER M5 ;
        RECT  47.664 60.396 47.688 60.48 ;
    END
  END cfg_data[127]
  PIN cfg_data[128]
    DIRECTION INPUT ;
    USE SIGNAL ;
    PORT
      LAYER M5 ;
        RECT  47.808 60.396 47.832 60.48 ;
    END
  END cfg_data[128]
  PIN cfg_data[129]
    DIRECTION INPUT ;
    USE SIGNAL ;
    PORT
      LAYER M5 ;
        RECT  47.952 60.396 47.976 60.48 ;
    END
  END cfg_data[129]
  PIN cfg_data[12]
    DIRECTION INPUT ;
    USE SIGNAL ;
    PORT
      LAYER M5 ;
        RECT  29.952 60.396 29.976 60.48 ;
    END
  END cfg_data[12]
  PIN cfg_data[130]
    DIRECTION INPUT ;
    USE SIGNAL ;
    PORT
      LAYER M5 ;
        RECT  48.096 60.396 48.12 60.48 ;
    END
  END cfg_data[130]
  PIN cfg_data[131]
    DIRECTION INPUT ;
    USE SIGNAL ;
    PORT
      LAYER M5 ;
        RECT  48.24 60.396 48.264 60.48 ;
    END
  END cfg_data[131]
  PIN cfg_data[132]
    DIRECTION INPUT ;
    USE SIGNAL ;
    PORT
      LAYER M5 ;
        RECT  48.384 60.396 48.408 60.48 ;
    END
  END cfg_data[132]
  PIN cfg_data[133]
    DIRECTION INPUT ;
    USE SIGNAL ;
    PORT
      LAYER M5 ;
        RECT  48.528 60.396 48.552 60.48 ;
    END
  END cfg_data[133]
  PIN cfg_data[134]
    DIRECTION INPUT ;
    USE SIGNAL ;
    PORT
      LAYER M5 ;
        RECT  48.672 60.396 48.696 60.48 ;
    END
  END cfg_data[134]
  PIN cfg_data[135]
    DIRECTION INPUT ;
    USE SIGNAL ;
    PORT
      LAYER M5 ;
        RECT  48.816 60.396 48.84 60.48 ;
    END
  END cfg_data[135]
  PIN cfg_data[136]
    DIRECTION INPUT ;
    USE SIGNAL ;
    PORT
      LAYER M5 ;
        RECT  48.96 60.396 48.984 60.48 ;
    END
  END cfg_data[136]
  PIN cfg_data[137]
    DIRECTION INPUT ;
    USE SIGNAL ;
    PORT
      LAYER M5 ;
        RECT  49.104 60.396 49.128 60.48 ;
    END
  END cfg_data[137]
  PIN cfg_data[138]
    DIRECTION INPUT ;
    USE SIGNAL ;
    PORT
      LAYER M5 ;
        RECT  49.248 60.396 49.272 60.48 ;
    END
  END cfg_data[138]
  PIN cfg_data[139]
    DIRECTION INPUT ;
    USE SIGNAL ;
    PORT
      LAYER M5 ;
        RECT  49.392 60.396 49.416 60.48 ;
    END
  END cfg_data[139]
  PIN cfg_data[13]
    DIRECTION INPUT ;
    USE SIGNAL ;
    PORT
      LAYER M5 ;
        RECT  30.096 60.396 30.12 60.48 ;
    END
  END cfg_data[13]
  PIN cfg_data[140]
    DIRECTION INPUT ;
    USE SIGNAL ;
    PORT
      LAYER M5 ;
        RECT  49.536 60.396 49.56 60.48 ;
    END
  END cfg_data[140]
  PIN cfg_data[141]
    DIRECTION INPUT ;
    USE SIGNAL ;
    PORT
      LAYER M5 ;
        RECT  49.68 60.396 49.704 60.48 ;
    END
  END cfg_data[141]
  PIN cfg_data[142]
    DIRECTION INPUT ;
    USE SIGNAL ;
    PORT
      LAYER M5 ;
        RECT  49.824 60.396 49.848 60.48 ;
    END
  END cfg_data[142]
  PIN cfg_data[143]
    DIRECTION INPUT ;
    USE SIGNAL ;
    PORT
      LAYER M5 ;
        RECT  49.968 60.396 49.992 60.48 ;
    END
  END cfg_data[143]
  PIN cfg_data[144]
    DIRECTION INPUT ;
    USE SIGNAL ;
    PORT
      LAYER M5 ;
        RECT  50.112 60.396 50.136 60.48 ;
    END
  END cfg_data[144]
  PIN cfg_data[145]
    DIRECTION INPUT ;
    USE SIGNAL ;
    PORT
      LAYER M5 ;
        RECT  50.256 60.396 50.28 60.48 ;
    END
  END cfg_data[145]
  PIN cfg_data[146]
    DIRECTION INPUT ;
    USE SIGNAL ;
    PORT
      LAYER M5 ;
        RECT  50.4 60.396 50.424 60.48 ;
    END
  END cfg_data[146]
  PIN cfg_data[147]
    DIRECTION INPUT ;
    USE SIGNAL ;
    PORT
      LAYER M5 ;
        RECT  41.328 60.396 41.352 60.48 ;
    END
  END cfg_data[147]
  PIN cfg_data[148]
    DIRECTION INPUT ;
    USE SIGNAL ;
    PORT
      LAYER M5 ;
        RECT  41.472 60.396 41.496 60.48 ;
    END
  END cfg_data[148]
  PIN cfg_data[149]
    DIRECTION INPUT ;
    USE SIGNAL ;
    PORT
      LAYER M5 ;
        RECT  41.616 60.396 41.64 60.48 ;
    END
  END cfg_data[149]
  PIN cfg_data[14]
    DIRECTION INPUT ;
    USE SIGNAL ;
    PORT
      LAYER M5 ;
        RECT  30.24 60.396 30.264 60.48 ;
    END
  END cfg_data[14]
  PIN cfg_data[150]
    DIRECTION INPUT ;
    USE SIGNAL ;
    PORT
      LAYER M5 ;
        RECT  41.76 60.396 41.784 60.48 ;
    END
  END cfg_data[150]
  PIN cfg_data[151]
    DIRECTION INPUT ;
    USE SIGNAL ;
    PORT
      LAYER M5 ;
        RECT  41.904 60.396 41.928 60.48 ;
    END
  END cfg_data[151]
  PIN cfg_data[152]
    DIRECTION INPUT ;
    USE SIGNAL ;
    PORT
      LAYER M5 ;
        RECT  42.048 60.396 42.072 60.48 ;
    END
  END cfg_data[152]
  PIN cfg_data[153]
    DIRECTION INPUT ;
    USE SIGNAL ;
    PORT
      LAYER M5 ;
        RECT  42.192 60.396 42.216 60.48 ;
    END
  END cfg_data[153]
  PIN cfg_data[154]
    DIRECTION INPUT ;
    USE SIGNAL ;
    PORT
      LAYER M5 ;
        RECT  42.336 60.396 42.36 60.48 ;
    END
  END cfg_data[154]
  PIN cfg_data[155]
    DIRECTION INPUT ;
    USE SIGNAL ;
    PORT
      LAYER M5 ;
        RECT  42.48 60.396 42.504 60.48 ;
    END
  END cfg_data[155]
  PIN cfg_data[156]
    DIRECTION INPUT ;
    USE SIGNAL ;
    PORT
      LAYER M5 ;
        RECT  42.624 60.396 42.648 60.48 ;
    END
  END cfg_data[156]
  PIN cfg_data[157]
    DIRECTION INPUT ;
    USE SIGNAL ;
    PORT
      LAYER M5 ;
        RECT  42.768 60.396 42.792 60.48 ;
    END
  END cfg_data[157]
  PIN cfg_data[158]
    DIRECTION INPUT ;
    USE SIGNAL ;
    PORT
      LAYER M5 ;
        RECT  42.912 60.396 42.936 60.48 ;
    END
  END cfg_data[158]
  PIN cfg_data[159]
    DIRECTION INPUT ;
    USE SIGNAL ;
    PORT
      LAYER M5 ;
        RECT  43.056 60.396 43.08 60.48 ;
    END
  END cfg_data[159]
  PIN cfg_data[15]
    DIRECTION INPUT ;
    USE SIGNAL ;
    PORT
      LAYER M5 ;
        RECT  30.384 60.396 30.408 60.48 ;
    END
  END cfg_data[15]
  PIN cfg_data[160]
    DIRECTION INPUT ;
    USE SIGNAL ;
    PORT
      LAYER M5 ;
        RECT  43.2 60.396 43.224 60.48 ;
    END
  END cfg_data[160]
  PIN cfg_data[161]
    DIRECTION INPUT ;
    USE SIGNAL ;
    PORT
      LAYER M5 ;
        RECT  43.344 60.396 43.368 60.48 ;
    END
  END cfg_data[161]
  PIN cfg_data[162]
    DIRECTION INPUT ;
    USE SIGNAL ;
    PORT
      LAYER M5 ;
        RECT  43.488 60.396 43.512 60.48 ;
    END
  END cfg_data[162]
  PIN cfg_data[163]
    DIRECTION INPUT ;
    USE SIGNAL ;
    PORT
      LAYER M5 ;
        RECT  43.632 60.396 43.656 60.48 ;
    END
  END cfg_data[163]
  PIN cfg_data[164]
    DIRECTION INPUT ;
    USE SIGNAL ;
    PORT
      LAYER M5 ;
        RECT  43.776 60.396 43.8 60.48 ;
    END
  END cfg_data[164]
  PIN cfg_data[165]
    DIRECTION INPUT ;
    USE SIGNAL ;
    PORT
      LAYER M5 ;
        RECT  43.92 60.396 43.944 60.48 ;
    END
  END cfg_data[165]
  PIN cfg_data[166]
    DIRECTION INPUT ;
    USE SIGNAL ;
    PORT
      LAYER M5 ;
        RECT  44.064 60.396 44.088 60.48 ;
    END
  END cfg_data[166]
  PIN cfg_data[167]
    DIRECTION INPUT ;
    USE SIGNAL ;
    PORT
      LAYER M5 ;
        RECT  44.208 60.396 44.232 60.48 ;
    END
  END cfg_data[167]
  PIN cfg_data[168]
    DIRECTION INPUT ;
    USE SIGNAL ;
    PORT
      LAYER M5 ;
        RECT  44.352 60.396 44.376 60.48 ;
    END
  END cfg_data[168]
  PIN cfg_data[169]
    DIRECTION INPUT ;
    USE SIGNAL ;
    PORT
      LAYER M5 ;
        RECT  44.496 60.396 44.52 60.48 ;
    END
  END cfg_data[169]
  PIN cfg_data[16]
    DIRECTION INPUT ;
    USE SIGNAL ;
    PORT
      LAYER M5 ;
        RECT  30.528 60.396 30.552 60.48 ;
    END
  END cfg_data[16]
  PIN cfg_data[170]
    DIRECTION INPUT ;
    USE SIGNAL ;
    PORT
      LAYER M5 ;
        RECT  44.64 60.396 44.664 60.48 ;
    END
  END cfg_data[170]
  PIN cfg_data[171]
    DIRECTION INPUT ;
    USE SIGNAL ;
    PORT
      LAYER M5 ;
        RECT  44.784 60.396 44.808 60.48 ;
    END
  END cfg_data[171]
  PIN cfg_data[172]
    DIRECTION INPUT ;
    USE SIGNAL ;
    PORT
      LAYER M5 ;
        RECT  44.928 60.396 44.952 60.48 ;
    END
  END cfg_data[172]
  PIN cfg_data[173]
    DIRECTION INPUT ;
    USE SIGNAL ;
    PORT
      LAYER M5 ;
        RECT  45.072 60.396 45.096 60.48 ;
    END
  END cfg_data[173]
  PIN cfg_data[174]
    DIRECTION INPUT ;
    USE SIGNAL ;
    PORT
      LAYER M5 ;
        RECT  45.216 60.396 45.24 60.48 ;
    END
  END cfg_data[174]
  PIN cfg_data[175]
    DIRECTION INPUT ;
    USE SIGNAL ;
    PORT
      LAYER M5 ;
        RECT  45.36 60.396 45.384 60.48 ;
    END
  END cfg_data[175]
  PIN cfg_data[176]
    DIRECTION INPUT ;
    USE SIGNAL ;
    PORT
      LAYER M5 ;
        RECT  45.504 60.396 45.528 60.48 ;
    END
  END cfg_data[176]
  PIN cfg_data[177]
    DIRECTION INPUT ;
    USE SIGNAL ;
    PORT
      LAYER M5 ;
        RECT  45.648 60.396 45.672 60.48 ;
    END
  END cfg_data[177]
  PIN cfg_data[178]
    DIRECTION INPUT ;
    USE SIGNAL ;
    PORT
      LAYER M5 ;
        RECT  45.792 60.396 45.816 60.48 ;
    END
  END cfg_data[178]
  PIN cfg_data[179]
    DIRECTION INPUT ;
    USE SIGNAL ;
    PORT
      LAYER M5 ;
        RECT  32.112 60.396 32.136 60.48 ;
    END
  END cfg_data[179]
  PIN cfg_data[17]
    DIRECTION INPUT ;
    USE SIGNAL ;
    PORT
      LAYER M5 ;
        RECT  30.672 60.396 30.696 60.48 ;
    END
  END cfg_data[17]
  PIN cfg_data[180]
    DIRECTION INPUT ;
    USE SIGNAL ;
    PORT
      LAYER M5 ;
        RECT  32.256 60.396 32.28 60.48 ;
    END
  END cfg_data[180]
  PIN cfg_data[181]
    DIRECTION INPUT ;
    USE SIGNAL ;
    PORT
      LAYER M5 ;
        RECT  32.4 60.396 32.424 60.48 ;
    END
  END cfg_data[181]
  PIN cfg_data[182]
    DIRECTION INPUT ;
    USE SIGNAL ;
    PORT
      LAYER M5 ;
        RECT  32.544 60.396 32.568 60.48 ;
    END
  END cfg_data[182]
  PIN cfg_data[183]
    DIRECTION INPUT ;
    USE SIGNAL ;
    PORT
      LAYER M5 ;
        RECT  32.688 60.396 32.712 60.48 ;
    END
  END cfg_data[183]
  PIN cfg_data[184]
    DIRECTION INPUT ;
    USE SIGNAL ;
    PORT
      LAYER M5 ;
        RECT  32.832 60.396 32.856 60.48 ;
    END
  END cfg_data[184]
  PIN cfg_data[185]
    DIRECTION INPUT ;
    USE SIGNAL ;
    PORT
      LAYER M5 ;
        RECT  32.976 60.396 33 60.48 ;
    END
  END cfg_data[185]
  PIN cfg_data[186]
    DIRECTION INPUT ;
    USE SIGNAL ;
    PORT
      LAYER M5 ;
        RECT  33.12 60.396 33.144 60.48 ;
    END
  END cfg_data[186]
  PIN cfg_data[187]
    DIRECTION INPUT ;
    USE SIGNAL ;
    PORT
      LAYER M5 ;
        RECT  33.264 60.396 33.288 60.48 ;
    END
  END cfg_data[187]
  PIN cfg_data[188]
    DIRECTION INPUT ;
    USE SIGNAL ;
    PORT
      LAYER M5 ;
        RECT  33.408 60.396 33.432 60.48 ;
    END
  END cfg_data[188]
  PIN cfg_data[189]
    DIRECTION INPUT ;
    USE SIGNAL ;
    PORT
      LAYER M5 ;
        RECT  33.552 60.396 33.576 60.48 ;
    END
  END cfg_data[189]
  PIN cfg_data[18]
    DIRECTION INPUT ;
    USE SIGNAL ;
    PORT
      LAYER M5 ;
        RECT  30.816 60.396 30.84 60.48 ;
    END
  END cfg_data[18]
  PIN cfg_data[190]
    DIRECTION INPUT ;
    USE SIGNAL ;
    PORT
      LAYER M5 ;
        RECT  33.696 60.396 33.72 60.48 ;
    END
  END cfg_data[190]
  PIN cfg_data[191]
    DIRECTION INPUT ;
    USE SIGNAL ;
    PORT
      LAYER M5 ;
        RECT  33.84 60.396 33.864 60.48 ;
    END
  END cfg_data[191]
  PIN cfg_data[192]
    DIRECTION INPUT ;
    USE SIGNAL ;
    PORT
      LAYER M5 ;
        RECT  33.984 60.396 34.008 60.48 ;
    END
  END cfg_data[192]
  PIN cfg_data[193]
    DIRECTION INPUT ;
    USE SIGNAL ;
    PORT
      LAYER M5 ;
        RECT  34.128 60.396 34.152 60.48 ;
    END
  END cfg_data[193]
  PIN cfg_data[194]
    DIRECTION INPUT ;
    USE SIGNAL ;
    PORT
      LAYER M5 ;
        RECT  34.272 60.396 34.296 60.48 ;
    END
  END cfg_data[194]
  PIN cfg_data[195]
    DIRECTION INPUT ;
    USE SIGNAL ;
    PORT
      LAYER M5 ;
        RECT  34.416 60.396 34.44 60.48 ;
    END
  END cfg_data[195]
  PIN cfg_data[196]
    DIRECTION INPUT ;
    USE SIGNAL ;
    PORT
      LAYER M5 ;
        RECT  34.56 60.396 34.584 60.48 ;
    END
  END cfg_data[196]
  PIN cfg_data[197]
    DIRECTION INPUT ;
    USE SIGNAL ;
    PORT
      LAYER M5 ;
        RECT  34.704 60.396 34.728 60.48 ;
    END
  END cfg_data[197]
  PIN cfg_data[198]
    DIRECTION INPUT ;
    USE SIGNAL ;
    PORT
      LAYER M5 ;
        RECT  34.848 60.396 34.872 60.48 ;
    END
  END cfg_data[198]
  PIN cfg_data[199]
    DIRECTION INPUT ;
    USE SIGNAL ;
    PORT
      LAYER M5 ;
        RECT  34.992 60.396 35.016 60.48 ;
    END
  END cfg_data[199]
  PIN cfg_data[19]
    DIRECTION INPUT ;
    USE SIGNAL ;
    PORT
      LAYER M5 ;
        RECT  12.528 60.396 12.552 60.48 ;
    END
  END cfg_data[19]
  PIN cfg_data[1]
    DIRECTION INPUT ;
    USE SIGNAL ;
    PORT
      LAYER M5 ;
        RECT  28.368 60.396 28.392 60.48 ;
    END
  END cfg_data[1]
  PIN cfg_data[200]
    DIRECTION INPUT ;
    USE SIGNAL ;
    PORT
      LAYER M5 ;
        RECT  35.136 60.396 35.16 60.48 ;
    END
  END cfg_data[200]
  PIN cfg_data[201]
    DIRECTION INPUT ;
    USE SIGNAL ;
    PORT
      LAYER M5 ;
        RECT  35.28 60.396 35.304 60.48 ;
    END
  END cfg_data[201]
  PIN cfg_data[202]
    DIRECTION INPUT ;
    USE SIGNAL ;
    PORT
      LAYER M5 ;
        RECT  35.424 60.396 35.448 60.48 ;
    END
  END cfg_data[202]
  PIN cfg_data[203]
    DIRECTION INPUT ;
    USE SIGNAL ;
    PORT
      LAYER M5 ;
        RECT  35.568 60.396 35.592 60.48 ;
    END
  END cfg_data[203]
  PIN cfg_data[204]
    DIRECTION INPUT ;
    USE SIGNAL ;
    PORT
      LAYER M5 ;
        RECT  35.712 60.396 35.736 60.48 ;
    END
  END cfg_data[204]
  PIN cfg_data[205]
    DIRECTION INPUT ;
    USE SIGNAL ;
    PORT
      LAYER M5 ;
        RECT  35.856 60.396 35.88 60.48 ;
    END
  END cfg_data[205]
  PIN cfg_data[206]
    DIRECTION INPUT ;
    USE SIGNAL ;
    PORT
      LAYER M5 ;
        RECT  36 60.396 36.024 60.48 ;
    END
  END cfg_data[206]
  PIN cfg_data[207]
    DIRECTION INPUT ;
    USE SIGNAL ;
    PORT
      LAYER M5 ;
        RECT  36.144 60.396 36.168 60.48 ;
    END
  END cfg_data[207]
  PIN cfg_data[208]
    DIRECTION INPUT ;
    USE SIGNAL ;
    PORT
      LAYER M5 ;
        RECT  36.288 60.396 36.312 60.48 ;
    END
  END cfg_data[208]
  PIN cfg_data[209]
    DIRECTION INPUT ;
    USE SIGNAL ;
    PORT
      LAYER M5 ;
        RECT  36.432 60.396 36.456 60.48 ;
    END
  END cfg_data[209]
  PIN cfg_data[20]
    DIRECTION INPUT ;
    USE SIGNAL ;
    PORT
      LAYER M5 ;
        RECT  12.672 60.396 12.696 60.48 ;
    END
  END cfg_data[20]
  PIN cfg_data[210]
    DIRECTION INPUT ;
    USE SIGNAL ;
    PORT
      LAYER M5 ;
        RECT  36.576 60.396 36.6 60.48 ;
    END
  END cfg_data[210]
  PIN cfg_data[211]
    DIRECTION INPUT ;
    USE SIGNAL ;
    PORT
      LAYER M5 ;
        RECT  21.744 60.396 21.768 60.48 ;
    END
  END cfg_data[211]
  PIN cfg_data[212]
    DIRECTION INPUT ;
    USE SIGNAL ;
    PORT
      LAYER M5 ;
        RECT  21.888 60.396 21.912 60.48 ;
    END
  END cfg_data[212]
  PIN cfg_data[213]
    DIRECTION INPUT ;
    USE SIGNAL ;
    PORT
      LAYER M5 ;
        RECT  22.032 60.396 22.056 60.48 ;
    END
  END cfg_data[213]
  PIN cfg_data[214]
    DIRECTION INPUT ;
    USE SIGNAL ;
    PORT
      LAYER M5 ;
        RECT  22.176 60.396 22.2 60.48 ;
    END
  END cfg_data[214]
  PIN cfg_data[215]
    DIRECTION INPUT ;
    USE SIGNAL ;
    PORT
      LAYER M5 ;
        RECT  22.32 60.396 22.344 60.48 ;
    END
  END cfg_data[215]
  PIN cfg_data[216]
    DIRECTION INPUT ;
    USE SIGNAL ;
    PORT
      LAYER M5 ;
        RECT  22.464 60.396 22.488 60.48 ;
    END
  END cfg_data[216]
  PIN cfg_data[217]
    DIRECTION INPUT ;
    USE SIGNAL ;
    PORT
      LAYER M5 ;
        RECT  22.608 60.396 22.632 60.48 ;
    END
  END cfg_data[217]
  PIN cfg_data[218]
    DIRECTION INPUT ;
    USE SIGNAL ;
    PORT
      LAYER M5 ;
        RECT  22.752 60.396 22.776 60.48 ;
    END
  END cfg_data[218]
  PIN cfg_data[219]
    DIRECTION INPUT ;
    USE SIGNAL ;
    PORT
      LAYER M5 ;
        RECT  22.896 60.396 22.92 60.48 ;
    END
  END cfg_data[219]
  PIN cfg_data[21]
    DIRECTION INPUT ;
    USE SIGNAL ;
    PORT
      LAYER M5 ;
        RECT  12.816 60.396 12.84 60.48 ;
    END
  END cfg_data[21]
  PIN cfg_data[220]
    DIRECTION INPUT ;
    USE SIGNAL ;
    PORT
      LAYER M5 ;
        RECT  23.04 60.396 23.064 60.48 ;
    END
  END cfg_data[220]
  PIN cfg_data[221]
    DIRECTION INPUT ;
    USE SIGNAL ;
    PORT
      LAYER M5 ;
        RECT  23.184 60.396 23.208 60.48 ;
    END
  END cfg_data[221]
  PIN cfg_data[222]
    DIRECTION INPUT ;
    USE SIGNAL ;
    PORT
      LAYER M5 ;
        RECT  23.328 60.396 23.352 60.48 ;
    END
  END cfg_data[222]
  PIN cfg_data[223]
    DIRECTION INPUT ;
    USE SIGNAL ;
    PORT
      LAYER M5 ;
        RECT  23.472 60.396 23.496 60.48 ;
    END
  END cfg_data[223]
  PIN cfg_data[224]
    DIRECTION INPUT ;
    USE SIGNAL ;
    PORT
      LAYER M5 ;
        RECT  23.616 60.396 23.64 60.48 ;
    END
  END cfg_data[224]
  PIN cfg_data[225]
    DIRECTION INPUT ;
    USE SIGNAL ;
    PORT
      LAYER M5 ;
        RECT  23.76 60.396 23.784 60.48 ;
    END
  END cfg_data[225]
  PIN cfg_data[226]
    DIRECTION INPUT ;
    USE SIGNAL ;
    PORT
      LAYER M5 ;
        RECT  23.904 60.396 23.928 60.48 ;
    END
  END cfg_data[226]
  PIN cfg_data[227]
    DIRECTION INPUT ;
    USE SIGNAL ;
    PORT
      LAYER M5 ;
        RECT  24.048 60.396 24.072 60.48 ;
    END
  END cfg_data[227]
  PIN cfg_data[228]
    DIRECTION INPUT ;
    USE SIGNAL ;
    PORT
      LAYER M5 ;
        RECT  24.192 60.396 24.216 60.48 ;
    END
  END cfg_data[228]
  PIN cfg_data[229]
    DIRECTION INPUT ;
    USE SIGNAL ;
    PORT
      LAYER M5 ;
        RECT  24.336 60.396 24.36 60.48 ;
    END
  END cfg_data[229]
  PIN cfg_data[22]
    DIRECTION INPUT ;
    USE SIGNAL ;
    PORT
      LAYER M5 ;
        RECT  12.96 60.396 12.984 60.48 ;
    END
  END cfg_data[22]
  PIN cfg_data[230]
    DIRECTION INPUT ;
    USE SIGNAL ;
    PORT
      LAYER M5 ;
        RECT  24.48 60.396 24.504 60.48 ;
    END
  END cfg_data[230]
  PIN cfg_data[231]
    DIRECTION INPUT ;
    USE SIGNAL ;
    PORT
      LAYER M5 ;
        RECT  24.624 60.396 24.648 60.48 ;
    END
  END cfg_data[231]
  PIN cfg_data[232]
    DIRECTION INPUT ;
    USE SIGNAL ;
    PORT
      LAYER M5 ;
        RECT  24.768 60.396 24.792 60.48 ;
    END
  END cfg_data[232]
  PIN cfg_data[233]
    DIRECTION INPUT ;
    USE SIGNAL ;
    PORT
      LAYER M5 ;
        RECT  24.912 60.396 24.936 60.48 ;
    END
  END cfg_data[233]
  PIN cfg_data[234]
    DIRECTION INPUT ;
    USE SIGNAL ;
    PORT
      LAYER M5 ;
        RECT  25.056 60.396 25.08 60.48 ;
    END
  END cfg_data[234]
  PIN cfg_data[235]
    DIRECTION INPUT ;
    USE SIGNAL ;
    PORT
      LAYER M5 ;
        RECT  25.2 60.396 25.224 60.48 ;
    END
  END cfg_data[235]
  PIN cfg_data[236]
    DIRECTION INPUT ;
    USE SIGNAL ;
    PORT
      LAYER M5 ;
        RECT  25.344 60.396 25.368 60.48 ;
    END
  END cfg_data[236]
  PIN cfg_data[237]
    DIRECTION INPUT ;
    USE SIGNAL ;
    PORT
      LAYER M5 ;
        RECT  25.488 60.396 25.512 60.48 ;
    END
  END cfg_data[237]
  PIN cfg_data[238]
    DIRECTION INPUT ;
    USE SIGNAL ;
    PORT
      LAYER M5 ;
        RECT  25.632 60.396 25.656 60.48 ;
    END
  END cfg_data[238]
  PIN cfg_data[239]
    DIRECTION INPUT ;
    USE SIGNAL ;
    PORT
      LAYER M5 ;
        RECT  25.776 60.396 25.8 60.48 ;
    END
  END cfg_data[239]
  PIN cfg_data[23]
    DIRECTION INPUT ;
    USE SIGNAL ;
    PORT
      LAYER M5 ;
        RECT  13.104 60.396 13.128 60.48 ;
    END
  END cfg_data[23]
  PIN cfg_data[240]
    DIRECTION INPUT ;
    USE SIGNAL ;
    PORT
      LAYER M5 ;
        RECT  25.92 60.396 25.944 60.48 ;
    END
  END cfg_data[240]
  PIN cfg_data[241]
    DIRECTION INPUT ;
    USE SIGNAL ;
    PORT
      LAYER M5 ;
        RECT  26.064 60.396 26.088 60.48 ;
    END
  END cfg_data[241]
  PIN cfg_data[242]
    DIRECTION INPUT ;
    USE SIGNAL ;
    PORT
      LAYER M5 ;
        RECT  26.208 60.396 26.232 60.48 ;
    END
  END cfg_data[242]
  PIN cfg_data[243]
    DIRECTION INPUT ;
    USE SIGNAL ;
    PORT
      LAYER M5 ;
        RECT  3.312 60.396 3.336 60.48 ;
    END
  END cfg_data[243]
  PIN cfg_data[244]
    DIRECTION INPUT ;
    USE SIGNAL ;
    PORT
      LAYER M5 ;
        RECT  3.456 60.396 3.48 60.48 ;
    END
  END cfg_data[244]
  PIN cfg_data[245]
    DIRECTION INPUT ;
    USE SIGNAL ;
    PORT
      LAYER M5 ;
        RECT  3.6 60.396 3.624 60.48 ;
    END
  END cfg_data[245]
  PIN cfg_data[246]
    DIRECTION INPUT ;
    USE SIGNAL ;
    PORT
      LAYER M5 ;
        RECT  3.744 60.396 3.768 60.48 ;
    END
  END cfg_data[246]
  PIN cfg_data[247]
    DIRECTION INPUT ;
    USE SIGNAL ;
    PORT
      LAYER M5 ;
        RECT  3.888 60.396 3.912 60.48 ;
    END
  END cfg_data[247]
  PIN cfg_data[248]
    DIRECTION INPUT ;
    USE SIGNAL ;
    PORT
      LAYER M5 ;
        RECT  4.032 60.396 4.056 60.48 ;
    END
  END cfg_data[248]
  PIN cfg_data[249]
    DIRECTION INPUT ;
    USE SIGNAL ;
    PORT
      LAYER M5 ;
        RECT  4.176 60.396 4.2 60.48 ;
    END
  END cfg_data[249]
  PIN cfg_data[24]
    DIRECTION INPUT ;
    USE SIGNAL ;
    PORT
      LAYER M5 ;
        RECT  13.248 60.396 13.272 60.48 ;
    END
  END cfg_data[24]
  PIN cfg_data[250]
    DIRECTION INPUT ;
    USE SIGNAL ;
    PORT
      LAYER M5 ;
        RECT  4.32 60.396 4.344 60.48 ;
    END
  END cfg_data[250]
  PIN cfg_data[251]
    DIRECTION INPUT ;
    USE SIGNAL ;
    PORT
      LAYER M5 ;
        RECT  4.464 60.396 4.488 60.48 ;
    END
  END cfg_data[251]
  PIN cfg_data[252]
    DIRECTION INPUT ;
    USE SIGNAL ;
    PORT
      LAYER M5 ;
        RECT  4.608 60.396 4.632 60.48 ;
    END
  END cfg_data[252]
  PIN cfg_data[253]
    DIRECTION INPUT ;
    USE SIGNAL ;
    PORT
      LAYER M5 ;
        RECT  4.752 60.396 4.776 60.48 ;
    END
  END cfg_data[253]
  PIN cfg_data[254]
    DIRECTION INPUT ;
    USE SIGNAL ;
    PORT
      LAYER M5 ;
        RECT  4.896 60.396 4.92 60.48 ;
    END
  END cfg_data[254]
  PIN cfg_data[255]
    DIRECTION INPUT ;
    USE SIGNAL ;
    PORT
      LAYER M5 ;
        RECT  5.04 60.396 5.064 60.48 ;
    END
  END cfg_data[255]
  PIN cfg_data[25]
    DIRECTION INPUT ;
    USE SIGNAL ;
    PORT
      LAYER M5 ;
        RECT  13.392 60.396 13.416 60.48 ;
    END
  END cfg_data[25]
  PIN cfg_data[26]
    DIRECTION INPUT ;
    USE SIGNAL ;
    PORT
      LAYER M5 ;
        RECT  13.536 60.396 13.56 60.48 ;
    END
  END cfg_data[26]
  PIN cfg_data[27]
    DIRECTION INPUT ;
    USE SIGNAL ;
    PORT
      LAYER M5 ;
        RECT  13.68 60.396 13.704 60.48 ;
    END
  END cfg_data[27]
  PIN cfg_data[28]
    DIRECTION INPUT ;
    USE SIGNAL ;
    PORT
      LAYER M5 ;
        RECT  13.824 60.396 13.848 60.48 ;
    END
  END cfg_data[28]
  PIN cfg_data[29]
    DIRECTION INPUT ;
    USE SIGNAL ;
    PORT
      LAYER M5 ;
        RECT  13.968 60.396 13.992 60.48 ;
    END
  END cfg_data[29]
  PIN cfg_data[2]
    DIRECTION INPUT ;
    USE SIGNAL ;
    PORT
      LAYER M5 ;
        RECT  28.512 60.396 28.536 60.48 ;
    END
  END cfg_data[2]
  PIN cfg_data[30]
    DIRECTION INPUT ;
    USE SIGNAL ;
    PORT
      LAYER M5 ;
        RECT  14.112 60.396 14.136 60.48 ;
    END
  END cfg_data[30]
  PIN cfg_data[31]
    DIRECTION INPUT ;
    USE SIGNAL ;
    PORT
      LAYER M5 ;
        RECT  14.256 60.396 14.28 60.48 ;
    END
  END cfg_data[31]
  PIN cfg_data[32]
    DIRECTION INPUT ;
    USE SIGNAL ;
    PORT
      LAYER M5 ;
        RECT  14.4 60.396 14.424 60.48 ;
    END
  END cfg_data[32]
  PIN cfg_data[33]
    DIRECTION INPUT ;
    USE SIGNAL ;
    PORT
      LAYER M5 ;
        RECT  14.544 60.396 14.568 60.48 ;
    END
  END cfg_data[33]
  PIN cfg_data[34]
    DIRECTION INPUT ;
    USE SIGNAL ;
    PORT
      LAYER M5 ;
        RECT  14.688 60.396 14.712 60.48 ;
    END
  END cfg_data[34]
  PIN cfg_data[35]
    DIRECTION INPUT ;
    USE SIGNAL ;
    PORT
      LAYER M5 ;
        RECT  14.832 60.396 14.856 60.48 ;
    END
  END cfg_data[35]
  PIN cfg_data[36]
    DIRECTION INPUT ;
    USE SIGNAL ;
    PORT
      LAYER M5 ;
        RECT  14.976 60.396 15 60.48 ;
    END
  END cfg_data[36]
  PIN cfg_data[37]
    DIRECTION INPUT ;
    USE SIGNAL ;
    PORT
      LAYER M5 ;
        RECT  15.12 60.396 15.144 60.48 ;
    END
  END cfg_data[37]
  PIN cfg_data[38]
    DIRECTION INPUT ;
    USE SIGNAL ;
    PORT
      LAYER M5 ;
        RECT  15.264 60.396 15.288 60.48 ;
    END
  END cfg_data[38]
  PIN cfg_data[39]
    DIRECTION INPUT ;
    USE SIGNAL ;
    PORT
      LAYER M5 ;
        RECT  15.408 60.396 15.432 60.48 ;
    END
  END cfg_data[39]
  PIN cfg_data[3]
    DIRECTION INPUT ;
    USE SIGNAL ;
    PORT
      LAYER M5 ;
        RECT  28.656 60.396 28.68 60.48 ;
    END
  END cfg_data[3]
  PIN cfg_data[40]
    DIRECTION INPUT ;
    USE SIGNAL ;
    PORT
      LAYER M5 ;
        RECT  15.552 60.396 15.576 60.48 ;
    END
  END cfg_data[40]
  PIN cfg_data[41]
    DIRECTION INPUT ;
    USE SIGNAL ;
    PORT
      LAYER M5 ;
        RECT  15.696 60.396 15.72 60.48 ;
    END
  END cfg_data[41]
  PIN cfg_data[42]
    DIRECTION INPUT ;
    USE SIGNAL ;
    PORT
      LAYER M5 ;
        RECT  15.84 60.396 15.864 60.48 ;
    END
  END cfg_data[42]
  PIN cfg_data[43]
    DIRECTION INPUT ;
    USE SIGNAL ;
    PORT
      LAYER M5 ;
        RECT  15.984 60.396 16.008 60.48 ;
    END
  END cfg_data[43]
  PIN cfg_data[44]
    DIRECTION INPUT ;
    USE SIGNAL ;
    PORT
      LAYER M5 ;
        RECT  16.128 60.396 16.152 60.48 ;
    END
  END cfg_data[44]
  PIN cfg_data[45]
    DIRECTION INPUT ;
    USE SIGNAL ;
    PORT
      LAYER M5 ;
        RECT  16.272 60.396 16.296 60.48 ;
    END
  END cfg_data[45]
  PIN cfg_data[46]
    DIRECTION INPUT ;
    USE SIGNAL ;
    PORT
      LAYER M5 ;
        RECT  16.416 60.396 16.44 60.48 ;
    END
  END cfg_data[46]
  PIN cfg_data[47]
    DIRECTION INPUT ;
    USE SIGNAL ;
    PORT
      LAYER M5 ;
        RECT  16.56 60.396 16.584 60.48 ;
    END
  END cfg_data[47]
  PIN cfg_data[48]
    DIRECTION INPUT ;
    USE SIGNAL ;
    PORT
      LAYER M5 ;
        RECT  16.704 60.396 16.728 60.48 ;
    END
  END cfg_data[48]
  PIN cfg_data[49]
    DIRECTION INPUT ;
    USE SIGNAL ;
    PORT
      LAYER M5 ;
        RECT  16.848 60.396 16.872 60.48 ;
    END
  END cfg_data[49]
  PIN cfg_data[4]
    DIRECTION INPUT ;
    USE SIGNAL ;
    PORT
      LAYER M5 ;
        RECT  28.8 60.396 28.824 60.48 ;
    END
  END cfg_data[4]
  PIN cfg_data[50]
    DIRECTION INPUT ;
    USE SIGNAL ;
    PORT
      LAYER M5 ;
        RECT  16.992 60.396 17.016 60.48 ;
    END
  END cfg_data[50]
  PIN cfg_data[51]
    DIRECTION INPUT ;
    USE SIGNAL ;
    PORT
      LAYER M5 ;
        RECT  17.136 60.396 17.16 60.48 ;
    END
  END cfg_data[51]
  PIN cfg_data[52]
    DIRECTION INPUT ;
    USE SIGNAL ;
    PORT
      LAYER M5 ;
        RECT  17.28 60.396 17.304 60.48 ;
    END
  END cfg_data[52]
  PIN cfg_data[53]
    DIRECTION INPUT ;
    USE SIGNAL ;
    PORT
      LAYER M5 ;
        RECT  17.424 60.396 17.448 60.48 ;
    END
  END cfg_data[53]
  PIN cfg_data[54]
    DIRECTION INPUT ;
    USE SIGNAL ;
    PORT
      LAYER M5 ;
        RECT  17.568 60.396 17.592 60.48 ;
    END
  END cfg_data[54]
  PIN cfg_data[55]
    DIRECTION INPUT ;
    USE SIGNAL ;
    PORT
      LAYER M5 ;
        RECT  17.712 60.396 17.736 60.48 ;
    END
  END cfg_data[55]
  PIN cfg_data[56]
    DIRECTION INPUT ;
    USE SIGNAL ;
    PORT
      LAYER M5 ;
        RECT  17.856 60.396 17.88 60.48 ;
    END
  END cfg_data[56]
  PIN cfg_data[57]
    DIRECTION INPUT ;
    USE SIGNAL ;
    PORT
      LAYER M5 ;
        RECT  18 60.396 18.024 60.48 ;
    END
  END cfg_data[57]
  PIN cfg_data[58]
    DIRECTION INPUT ;
    USE SIGNAL ;
    PORT
      LAYER M5 ;
        RECT  18.144 60.396 18.168 60.48 ;
    END
  END cfg_data[58]
  PIN cfg_data[59]
    DIRECTION INPUT ;
    USE SIGNAL ;
    PORT
      LAYER M5 ;
        RECT  18.288 60.396 18.312 60.48 ;
    END
  END cfg_data[59]
  PIN cfg_data[5]
    DIRECTION INPUT ;
    USE SIGNAL ;
    PORT
      LAYER M5 ;
        RECT  28.944 60.396 28.968 60.48 ;
    END
  END cfg_data[5]
  PIN cfg_data[60]
    DIRECTION INPUT ;
    USE SIGNAL ;
    PORT
      LAYER M5 ;
        RECT  18.432 60.396 18.456 60.48 ;
    END
  END cfg_data[60]
  PIN cfg_data[61]
    DIRECTION INPUT ;
    USE SIGNAL ;
    PORT
      LAYER M5 ;
        RECT  18.576 60.396 18.6 60.48 ;
    END
  END cfg_data[61]
  PIN cfg_data[62]
    DIRECTION INPUT ;
    USE SIGNAL ;
    PORT
      LAYER M5 ;
        RECT  18.72 60.396 18.744 60.48 ;
    END
  END cfg_data[62]
  PIN cfg_data[63]
    DIRECTION INPUT ;
    USE SIGNAL ;
    PORT
      LAYER M5 ;
        RECT  18.864 60.396 18.888 60.48 ;
    END
  END cfg_data[63]
  PIN cfg_data[64]
    DIRECTION INPUT ;
    USE SIGNAL ;
    PORT
      LAYER M5 ;
        RECT  19.008 60.396 19.032 60.48 ;
    END
  END cfg_data[64]
  PIN cfg_data[65]
    DIRECTION INPUT ;
    USE SIGNAL ;
    PORT
      LAYER M5 ;
        RECT  19.152 60.396 19.176 60.48 ;
    END
  END cfg_data[65]
  PIN cfg_data[66]
    DIRECTION INPUT ;
    USE SIGNAL ;
    PORT
      LAYER M5 ;
        RECT  19.296 60.396 19.32 60.48 ;
    END
  END cfg_data[66]
  PIN cfg_data[67]
    DIRECTION INPUT ;
    USE SIGNAL ;
    PORT
      LAYER M5 ;
        RECT  19.44 60.396 19.464 60.48 ;
    END
  END cfg_data[67]
  PIN cfg_data[68]
    DIRECTION INPUT ;
    USE SIGNAL ;
    PORT
      LAYER M5 ;
        RECT  19.584 60.396 19.608 60.48 ;
    END
  END cfg_data[68]
  PIN cfg_data[69]
    DIRECTION INPUT ;
    USE SIGNAL ;
    PORT
      LAYER M5 ;
        RECT  19.728 60.396 19.752 60.48 ;
    END
  END cfg_data[69]
  PIN cfg_data[6]
    DIRECTION INPUT ;
    USE SIGNAL ;
    PORT
      LAYER M5 ;
        RECT  29.088 60.396 29.112 60.48 ;
    END
  END cfg_data[6]
  PIN cfg_data[70]
    DIRECTION INPUT ;
    USE SIGNAL ;
    PORT
      LAYER M5 ;
        RECT  19.872 60.396 19.896 60.48 ;
    END
  END cfg_data[70]
  PIN cfg_data[71]
    DIRECTION INPUT ;
    USE SIGNAL ;
    PORT
      LAYER M5 ;
        RECT  20.016 60.396 20.04 60.48 ;
    END
  END cfg_data[71]
  PIN cfg_data[72]
    DIRECTION INPUT ;
    USE SIGNAL ;
    PORT
      LAYER M5 ;
        RECT  20.16 60.396 20.184 60.48 ;
    END
  END cfg_data[72]
  PIN cfg_data[73]
    DIRECTION INPUT ;
    USE SIGNAL ;
    PORT
      LAYER M5 ;
        RECT  20.304 60.396 20.328 60.48 ;
    END
  END cfg_data[73]
  PIN cfg_data[74]
    DIRECTION INPUT ;
    USE SIGNAL ;
    PORT
      LAYER M5 ;
        RECT  20.448 60.396 20.472 60.48 ;
    END
  END cfg_data[74]
  PIN cfg_data[75]
    DIRECTION INPUT ;
    USE SIGNAL ;
    PORT
      LAYER M5 ;
        RECT  20.592 60.396 20.616 60.48 ;
    END
  END cfg_data[75]
  PIN cfg_data[76]
    DIRECTION INPUT ;
    USE SIGNAL ;
    PORT
      LAYER M5 ;
        RECT  20.736 60.396 20.76 60.48 ;
    END
  END cfg_data[76]
  PIN cfg_data[77]
    DIRECTION INPUT ;
    USE SIGNAL ;
    PORT
      LAYER M5 ;
        RECT  20.88 60.396 20.904 60.48 ;
    END
  END cfg_data[77]
  PIN cfg_data[78]
    DIRECTION INPUT ;
    USE SIGNAL ;
    PORT
      LAYER M5 ;
        RECT  21.024 60.396 21.048 60.48 ;
    END
  END cfg_data[78]
  PIN cfg_data[79]
    DIRECTION INPUT ;
    USE SIGNAL ;
    PORT
      LAYER M5 ;
        RECT  21.168 60.396 21.192 60.48 ;
    END
  END cfg_data[79]
  PIN cfg_data[7]
    DIRECTION INPUT ;
    USE SIGNAL ;
    PORT
      LAYER M5 ;
        RECT  29.232 60.396 29.256 60.48 ;
    END
  END cfg_data[7]
  PIN cfg_data[80]
    DIRECTION INPUT ;
    USE SIGNAL ;
    PORT
      LAYER M5 ;
        RECT  21.312 60.396 21.336 60.48 ;
    END
  END cfg_data[80]
  PIN cfg_data[81]
    DIRECTION INPUT ;
    USE SIGNAL ;
    PORT
      LAYER M5 ;
        RECT  21.456 60.396 21.48 60.48 ;
    END
  END cfg_data[81]
  PIN cfg_data[82]
    DIRECTION INPUT ;
    USE SIGNAL ;
    PORT
      LAYER M5 ;
        RECT  21.6 60.396 21.624 60.48 ;
    END
  END cfg_data[82]
  PIN cfg_data[83]
    DIRECTION INPUT ;
    USE SIGNAL ;
    PORT
      LAYER M5 ;
        RECT  36.72 60.396 36.744 60.48 ;
    END
  END cfg_data[83]
  PIN cfg_data[84]
    DIRECTION INPUT ;
    USE SIGNAL ;
    PORT
      LAYER M5 ;
        RECT  36.864 60.396 36.888 60.48 ;
    END
  END cfg_data[84]
  PIN cfg_data[85]
    DIRECTION INPUT ;
    USE SIGNAL ;
    PORT
      LAYER M5 ;
        RECT  37.008 60.396 37.032 60.48 ;
    END
  END cfg_data[85]
  PIN cfg_data[86]
    DIRECTION INPUT ;
    USE SIGNAL ;
    PORT
      LAYER M5 ;
        RECT  37.152 60.396 37.176 60.48 ;
    END
  END cfg_data[86]
  PIN cfg_data[87]
    DIRECTION INPUT ;
    USE SIGNAL ;
    PORT
      LAYER M5 ;
        RECT  37.296 60.396 37.32 60.48 ;
    END
  END cfg_data[87]
  PIN cfg_data[88]
    DIRECTION INPUT ;
    USE SIGNAL ;
    PORT
      LAYER M5 ;
        RECT  37.44 60.396 37.464 60.48 ;
    END
  END cfg_data[88]
  PIN cfg_data[89]
    DIRECTION INPUT ;
    USE SIGNAL ;
    PORT
      LAYER M5 ;
        RECT  37.584 60.396 37.608 60.48 ;
    END
  END cfg_data[89]
  PIN cfg_data[8]
    DIRECTION INPUT ;
    USE SIGNAL ;
    PORT
      LAYER M5 ;
        RECT  29.376 60.396 29.4 60.48 ;
    END
  END cfg_data[8]
  PIN cfg_data[90]
    DIRECTION INPUT ;
    USE SIGNAL ;
    PORT
      LAYER M5 ;
        RECT  37.728 60.396 37.752 60.48 ;
    END
  END cfg_data[90]
  PIN cfg_data[91]
    DIRECTION INPUT ;
    USE SIGNAL ;
    PORT
      LAYER M5 ;
        RECT  37.872 60.396 37.896 60.48 ;
    END
  END cfg_data[91]
  PIN cfg_data[92]
    DIRECTION INPUT ;
    USE SIGNAL ;
    PORT
      LAYER M5 ;
        RECT  38.016 60.396 38.04 60.48 ;
    END
  END cfg_data[92]
  PIN cfg_data[93]
    DIRECTION INPUT ;
    USE SIGNAL ;
    PORT
      LAYER M5 ;
        RECT  38.16 60.396 38.184 60.48 ;
    END
  END cfg_data[93]
  PIN cfg_data[94]
    DIRECTION INPUT ;
    USE SIGNAL ;
    PORT
      LAYER M5 ;
        RECT  38.304 60.396 38.328 60.48 ;
    END
  END cfg_data[94]
  PIN cfg_data[95]
    DIRECTION INPUT ;
    USE SIGNAL ;
    PORT
      LAYER M5 ;
        RECT  38.448 60.396 38.472 60.48 ;
    END
  END cfg_data[95]
  PIN cfg_data[96]
    DIRECTION INPUT ;
    USE SIGNAL ;
    PORT
      LAYER M5 ;
        RECT  38.592 60.396 38.616 60.48 ;
    END
  END cfg_data[96]
  PIN cfg_data[97]
    DIRECTION INPUT ;
    USE SIGNAL ;
    PORT
      LAYER M5 ;
        RECT  38.736 60.396 38.76 60.48 ;
    END
  END cfg_data[97]
  PIN cfg_data[98]
    DIRECTION INPUT ;
    USE SIGNAL ;
    PORT
      LAYER M5 ;
        RECT  38.88 60.396 38.904 60.48 ;
    END
  END cfg_data[98]
  PIN cfg_data[99]
    DIRECTION INPUT ;
    USE SIGNAL ;
    PORT
      LAYER M5 ;
        RECT  39.024 60.396 39.048 60.48 ;
    END
  END cfg_data[99]
  PIN cfg_data[9]
    DIRECTION INPUT ;
    USE SIGNAL ;
    PORT
      LAYER M5 ;
        RECT  29.52 60.396 29.544 60.48 ;
    END
  END cfg_data[9]
  PIN cfg_target[0]
    DIRECTION INPUT ;
    USE SIGNAL ;
    PORT
      LAYER M5 ;
        RECT  5.184 60.396 5.208 60.48 ;
    END
  END cfg_target[0]
  PIN cfg_target[1]
    DIRECTION INPUT ;
    USE SIGNAL ;
    PORT
      LAYER M5 ;
        RECT  5.328 60.396 5.352 60.48 ;
    END
  END cfg_target[1]
  PIN cfg_target[2]
    DIRECTION INPUT ;
    USE SIGNAL ;
    PORT
      LAYER M5 ;
        RECT  5.472 60.396 5.496 60.48 ;
    END
  END cfg_target[2]
  PIN cfg_target[3]
    DIRECTION INPUT ;
    USE SIGNAL ;
    PORT
      LAYER M5 ;
        RECT  5.616 60.396 5.64 60.48 ;
    END
  END cfg_target[3]
  PIN cfg_target[4]
    DIRECTION INPUT ;
    USE SIGNAL ;
    PORT
      LAYER M5 ;
        RECT  5.76 60.396 5.784 60.48 ;
    END
  END cfg_target[4]
  PIN cfg_target[5]
    DIRECTION INPUT ;
    USE SIGNAL ;
    PORT
      LAYER M5 ;
        RECT  5.904 60.396 5.928 60.48 ;
    END
  END cfg_target[5]
  PIN cfg_target[6]
    DIRECTION INPUT ;
    USE SIGNAL ;
    PORT
      LAYER M5 ;
        RECT  6.048 60.396 6.072 60.48 ;
    END
  END cfg_target[6]
  PIN cfg_target[7]
    DIRECTION INPUT ;
    USE SIGNAL ;
    PORT
      LAYER M5 ;
        RECT  6.192 60.396 6.216 60.48 ;
    END
  END cfg_target[7]
  PIN cfg_v
    DIRECTION INPUT ;
    USE SIGNAL ;
    PORT
      LAYER M5 ;
        RECT  6.336 60.396 6.36 60.48 ;
    END
  END cfg_v
  PIN clk
    DIRECTION INPUT ;
    USE SIGNAL ;
    PORT
      LAYER M5 ;
        RECT  6.48 60.396 6.504 60.48 ;
    END
  END clk
  PIN cmd[0]
    DIRECTION OUTPUT ;
    USE SIGNAL ;
    PORT
      LAYER M4 ;
        RECT  0 17.136 0.084 17.16 ;
    END
  END cmd[0]
  PIN cmd_v
    DIRECTION OUTPUT ;
    USE SIGNAL ;
    PORT
      LAYER M4 ;
        RECT  0 17.28 0.084 17.304 ;
    END
  END cmd_v
  PIN configured
    DIRECTION OUTPUT ;
    USE SIGNAL ;
    PORT
      LAYER M5 ;
        RECT  6.624 60.396 6.648 60.48 ;
    END
  END configured
  PIN cycle[0]
    DIRECTION OUTPUT ;
    USE SIGNAL ;
    PORT
      LAYER M4 ;
        RECT  0 17.424 0.084 17.448 ;
    END
  END cycle[0]
  PIN cycle[10]
    DIRECTION OUTPUT ;
    USE SIGNAL ;
    PORT
      LAYER M4 ;
        RECT  0 18.864 0.084 18.888 ;
    END
  END cycle[10]
  PIN cycle[11]
    DIRECTION OUTPUT ;
    USE SIGNAL ;
    PORT
      LAYER M4 ;
        RECT  0 19.008 0.084 19.032 ;
    END
  END cycle[11]
  PIN cycle[12]
    DIRECTION OUTPUT ;
    USE SIGNAL ;
    PORT
      LAYER M4 ;
        RECT  0 19.152 0.084 19.176 ;
    END
  END cycle[12]
  PIN cycle[13]
    DIRECTION OUTPUT ;
    USE SIGNAL ;
    PORT
      LAYER M4 ;
        RECT  0 19.296 0.084 19.32 ;
    END
  END cycle[13]
  PIN cycle[14]
    DIRECTION OUTPUT ;
    USE SIGNAL ;
    PORT
      LAYER M4 ;
        RECT  0 19.44 0.084 19.464 ;
    END
  END cycle[14]
  PIN cycle[15]
    DIRECTION OUTPUT ;
    USE SIGNAL ;
    PORT
      LAYER M4 ;
        RECT  0 19.584 0.084 19.608 ;
    END
  END cycle[15]
  PIN cycle[16]
    DIRECTION OUTPUT ;
    USE SIGNAL ;
    PORT
      LAYER M4 ;
        RECT  0 19.728 0.084 19.752 ;
    END
  END cycle[16]
  PIN cycle[17]
    DIRECTION OUTPUT ;
    USE SIGNAL ;
    PORT
      LAYER M4 ;
        RECT  0 19.872 0.084 19.896 ;
    END
  END cycle[17]
  PIN cycle[18]
    DIRECTION OUTPUT ;
    USE SIGNAL ;
    PORT
      LAYER M4 ;
        RECT  0 20.016 0.084 20.04 ;
    END
  END cycle[18]
  PIN cycle[19]
    DIRECTION OUTPUT ;
    USE SIGNAL ;
    PORT
      LAYER M4 ;
        RECT  0 20.16 0.084 20.184 ;
    END
  END cycle[19]
  PIN cycle[1]
    DIRECTION OUTPUT ;
    USE SIGNAL ;
    PORT
      LAYER M4 ;
        RECT  0 17.568 0.084 17.592 ;
    END
  END cycle[1]
  PIN cycle[20]
    DIRECTION OUTPUT ;
    USE SIGNAL ;
    PORT
      LAYER M4 ;
        RECT  0 20.304 0.084 20.328 ;
    END
  END cycle[20]
  PIN cycle[21]
    DIRECTION OUTPUT ;
    USE SIGNAL ;
    PORT
      LAYER M4 ;
        RECT  0 20.448 0.084 20.472 ;
    END
  END cycle[21]
  PIN cycle[22]
    DIRECTION OUTPUT ;
    USE SIGNAL ;
    PORT
      LAYER M4 ;
        RECT  0 20.592 0.084 20.616 ;
    END
  END cycle[22]
  PIN cycle[23]
    DIRECTION OUTPUT ;
    USE SIGNAL ;
    PORT
      LAYER M4 ;
        RECT  0 20.736 0.084 20.76 ;
    END
  END cycle[23]
  PIN cycle[24]
    DIRECTION OUTPUT ;
    USE SIGNAL ;
    PORT
      LAYER M4 ;
        RECT  0 20.88 0.084 20.904 ;
    END
  END cycle[24]
  PIN cycle[25]
    DIRECTION OUTPUT ;
    USE SIGNAL ;
    PORT
      LAYER M4 ;
        RECT  0 21.024 0.084 21.048 ;
    END
  END cycle[25]
  PIN cycle[26]
    DIRECTION OUTPUT ;
    USE SIGNAL ;
    PORT
      LAYER M4 ;
        RECT  0 21.168 0.084 21.192 ;
    END
  END cycle[26]
  PIN cycle[27]
    DIRECTION OUTPUT ;
    USE SIGNAL ;
    PORT
      LAYER M4 ;
        RECT  0 21.312 0.084 21.336 ;
    END
  END cycle[27]
  PIN cycle[28]
    DIRECTION OUTPUT ;
    USE SIGNAL ;
    PORT
      LAYER M4 ;
        RECT  0 21.456 0.084 21.48 ;
    END
  END cycle[28]
  PIN cycle[29]
    DIRECTION OUTPUT ;
    USE SIGNAL ;
    PORT
      LAYER M4 ;
        RECT  0 21.6 0.084 21.624 ;
    END
  END cycle[29]
  PIN cycle[2]
    DIRECTION OUTPUT ;
    USE SIGNAL ;
    PORT
      LAYER M4 ;
        RECT  0 17.712 0.084 17.736 ;
    END
  END cycle[2]
  PIN cycle[30]
    DIRECTION OUTPUT ;
    USE SIGNAL ;
    PORT
      LAYER M4 ;
        RECT  0 26.064 0.084 26.088 ;
    END
  END cycle[30]
  PIN cycle[31]
    DIRECTION OUTPUT ;
    USE SIGNAL ;
    PORT
      LAYER M4 ;
        RECT  0 26.208 0.084 26.232 ;
    END
  END cycle[31]
  PIN cycle[3]
    DIRECTION OUTPUT ;
    USE SIGNAL ;
    PORT
      LAYER M4 ;
        RECT  0 17.856 0.084 17.88 ;
    END
  END cycle[3]
  PIN cycle[4]
    DIRECTION OUTPUT ;
    USE SIGNAL ;
    PORT
      LAYER M4 ;
        RECT  0 18 0.084 18.024 ;
    END
  END cycle[4]
  PIN cycle[5]
    DIRECTION OUTPUT ;
    USE SIGNAL ;
    PORT
      LAYER M4 ;
        RECT  0 18.144 0.084 18.168 ;
    END
  END cycle[5]
  PIN cycle[6]
    DIRECTION OUTPUT ;
    USE SIGNAL ;
    PORT
      LAYER M4 ;
        RECT  0 18.288 0.084 18.312 ;
    END
  END cycle[6]
  PIN cycle[7]
    DIRECTION OUTPUT ;
    USE SIGNAL ;
    PORT
      LAYER M4 ;
        RECT  0 18.432 0.084 18.456 ;
    END
  END cycle[7]
  PIN cycle[8]
    DIRECTION OUTPUT ;
    USE SIGNAL ;
    PORT
      LAYER M4 ;
        RECT  0 18.576 0.084 18.6 ;
    END
  END cycle[8]
  PIN cycle[9]
    DIRECTION OUTPUT ;
    USE SIGNAL ;
    PORT
      LAYER M4 ;
        RECT  0 18.72 0.084 18.744 ;
    END
  END cycle[9]
  PIN desc_base[0]
    DIRECTION INPUT ;
    USE SIGNAL ;
    PORT
      LAYER M5 ;
        RECT  6.768 60.396 6.792 60.48 ;
    END
  END desc_base[0]
  PIN desc_base[10]
    DIRECTION INPUT ;
    USE SIGNAL ;
    PORT
      LAYER M5 ;
        RECT  8.208 60.396 8.232 60.48 ;
    END
  END desc_base[10]
  PIN desc_base[11]
    DIRECTION INPUT ;
    USE SIGNAL ;
    PORT
      LAYER M5 ;
        RECT  8.352 60.396 8.376 60.48 ;
    END
  END desc_base[11]
  PIN desc_base[1]
    DIRECTION INPUT ;
    USE SIGNAL ;
    PORT
      LAYER M5 ;
        RECT  6.912 60.396 6.936 60.48 ;
    END
  END desc_base[1]
  PIN desc_base[2]
    DIRECTION INPUT ;
    USE SIGNAL ;
    PORT
      LAYER M5 ;
        RECT  7.056 60.396 7.08 60.48 ;
    END
  END desc_base[2]
  PIN desc_base[3]
    DIRECTION INPUT ;
    USE SIGNAL ;
    PORT
      LAYER M5 ;
        RECT  7.2 60.396 7.224 60.48 ;
    END
  END desc_base[3]
  PIN desc_base[4]
    DIRECTION INPUT ;
    USE SIGNAL ;
    PORT
      LAYER M5 ;
        RECT  7.344 60.396 7.368 60.48 ;
    END
  END desc_base[4]
  PIN desc_base[5]
    DIRECTION INPUT ;
    USE SIGNAL ;
    PORT
      LAYER M5 ;
        RECT  7.488 60.396 7.512 60.48 ;
    END
  END desc_base[5]
  PIN desc_base[6]
    DIRECTION INPUT ;
    USE SIGNAL ;
    PORT
      LAYER M5 ;
        RECT  7.632 60.396 7.656 60.48 ;
    END
  END desc_base[6]
  PIN desc_base[7]
    DIRECTION INPUT ;
    USE SIGNAL ;
    PORT
      LAYER M5 ;
        RECT  7.776 60.396 7.8 60.48 ;
    END
  END desc_base[7]
  PIN desc_base[8]
    DIRECTION INPUT ;
    USE SIGNAL ;
    PORT
      LAYER M5 ;
        RECT  7.92 60.396 7.944 60.48 ;
    END
  END desc_base[8]
  PIN desc_base[9]
    DIRECTION INPUT ;
    USE SIGNAL ;
    PORT
      LAYER M5 ;
        RECT  8.064 60.396 8.088 60.48 ;
    END
  END desc_base[9]
  PIN desc_limit[0]
    DIRECTION INPUT ;
    USE SIGNAL ;
    PORT
      LAYER M5 ;
        RECT  8.496 60.396 8.52 60.48 ;
    END
  END desc_limit[0]
  PIN desc_limit[10]
    DIRECTION INPUT ;
    USE SIGNAL ;
    PORT
      LAYER M5 ;
        RECT  9.936 60.396 9.96 60.48 ;
    END
  END desc_limit[10]
  PIN desc_limit[11]
    DIRECTION INPUT ;
    USE SIGNAL ;
    PORT
      LAYER M5 ;
        RECT  10.08 60.396 10.104 60.48 ;
    END
  END desc_limit[11]
  PIN desc_limit[12]
    DIRECTION INPUT ;
    USE SIGNAL ;
    PORT
      LAYER M5 ;
        RECT  10.224 60.396 10.248 60.48 ;
    END
  END desc_limit[12]
  PIN desc_limit[1]
    DIRECTION INPUT ;
    USE SIGNAL ;
    PORT
      LAYER M5 ;
        RECT  8.64 60.396 8.664 60.48 ;
    END
  END desc_limit[1]
  PIN desc_limit[2]
    DIRECTION INPUT ;
    USE SIGNAL ;
    PORT
      LAYER M5 ;
        RECT  8.784 60.396 8.808 60.48 ;
    END
  END desc_limit[2]
  PIN desc_limit[3]
    DIRECTION INPUT ;
    USE SIGNAL ;
    PORT
      LAYER M5 ;
        RECT  8.928 60.396 8.952 60.48 ;
    END
  END desc_limit[3]
  PIN desc_limit[4]
    DIRECTION INPUT ;
    USE SIGNAL ;
    PORT
      LAYER M5 ;
        RECT  9.072 60.396 9.096 60.48 ;
    END
  END desc_limit[4]
  PIN desc_limit[5]
    DIRECTION INPUT ;
    USE SIGNAL ;
    PORT
      LAYER M5 ;
        RECT  9.216 60.396 9.24 60.48 ;
    END
  END desc_limit[5]
  PIN desc_limit[6]
    DIRECTION INPUT ;
    USE SIGNAL ;
    PORT
      LAYER M5 ;
        RECT  9.36 60.396 9.384 60.48 ;
    END
  END desc_limit[6]
  PIN desc_limit[7]
    DIRECTION INPUT ;
    USE SIGNAL ;
    PORT
      LAYER M5 ;
        RECT  9.504 60.396 9.528 60.48 ;
    END
  END desc_limit[7]
  PIN desc_limit[8]
    DIRECTION INPUT ;
    USE SIGNAL ;
    PORT
      LAYER M5 ;
        RECT  9.648 60.396 9.672 60.48 ;
    END
  END desc_limit[8]
  PIN desc_limit[9]
    DIRECTION INPUT ;
    USE SIGNAL ;
    PORT
      LAYER M5 ;
        RECT  9.792 60.396 9.816 60.48 ;
    END
  END desc_limit[9]
  PIN desc_loops[0]
    DIRECTION INPUT ;
    USE SIGNAL ;
    PORT
      LAYER M5 ;
        RECT  10.368 60.396 10.392 60.48 ;
    END
  END desc_loops[0]
  PIN desc_loops[10]
    DIRECTION INPUT ;
    USE SIGNAL ;
    PORT
      LAYER M5 ;
        RECT  11.808 60.396 11.832 60.48 ;
    END
  END desc_loops[10]
  PIN desc_loops[11]
    DIRECTION INPUT ;
    USE SIGNAL ;
    PORT
      LAYER M5 ;
        RECT  11.952 60.396 11.976 60.48 ;
    END
  END desc_loops[11]
  PIN desc_loops[12]
    DIRECTION INPUT ;
    USE SIGNAL ;
    PORT
      LAYER M5 ;
        RECT  12.096 60.396 12.12 60.48 ;
    END
  END desc_loops[12]
  PIN desc_loops[13]
    DIRECTION INPUT ;
    USE SIGNAL ;
    PORT
      LAYER M5 ;
        RECT  12.24 60.396 12.264 60.48 ;
    END
  END desc_loops[13]
  PIN desc_loops[14]
    DIRECTION INPUT ;
    USE SIGNAL ;
    PORT
      LAYER M5 ;
        RECT  12.384 60.396 12.408 60.48 ;
    END
  END desc_loops[14]
  PIN desc_loops[15]
    DIRECTION INPUT ;
    USE SIGNAL ;
    PORT
      LAYER M5 ;
        RECT  53.28 60.396 53.304 60.48 ;
    END
  END desc_loops[15]
  PIN desc_loops[1]
    DIRECTION INPUT ;
    USE SIGNAL ;
    PORT
      LAYER M5 ;
        RECT  10.512 60.396 10.536 60.48 ;
    END
  END desc_loops[1]
  PIN desc_loops[2]
    DIRECTION INPUT ;
    USE SIGNAL ;
    PORT
      LAYER M5 ;
        RECT  10.656 60.396 10.68 60.48 ;
    END
  END desc_loops[2]
  PIN desc_loops[3]
    DIRECTION INPUT ;
    USE SIGNAL ;
    PORT
      LAYER M5 ;
        RECT  10.8 60.396 10.824 60.48 ;
    END
  END desc_loops[3]
  PIN desc_loops[4]
    DIRECTION INPUT ;
    USE SIGNAL ;
    PORT
      LAYER M5 ;
        RECT  10.944 60.396 10.968 60.48 ;
    END
  END desc_loops[4]
  PIN desc_loops[5]
    DIRECTION INPUT ;
    USE SIGNAL ;
    PORT
      LAYER M5 ;
        RECT  11.088 60.396 11.112 60.48 ;
    END
  END desc_loops[5]
  PIN desc_loops[6]
    DIRECTION INPUT ;
    USE SIGNAL ;
    PORT
      LAYER M5 ;
        RECT  11.232 60.396 11.256 60.48 ;
    END
  END desc_loops[6]
  PIN desc_loops[7]
    DIRECTION INPUT ;
    USE SIGNAL ;
    PORT
      LAYER M5 ;
        RECT  11.376 60.396 11.4 60.48 ;
    END
  END desc_loops[7]
  PIN desc_loops[8]
    DIRECTION INPUT ;
    USE SIGNAL ;
    PORT
      LAYER M5 ;
        RECT  11.52 60.396 11.544 60.48 ;
    END
  END desc_loops[8]
  PIN desc_loops[9]
    DIRECTION INPUT ;
    USE SIGNAL ;
    PORT
      LAYER M5 ;
        RECT  11.664 60.396 11.688 60.48 ;
    END
  END desc_loops[9]
  PIN desc_v
    DIRECTION INPUT ;
    USE SIGNAL ;
    PORT
      LAYER M5 ;
        RECT  53.424 60.396 53.448 60.48 ;
    END
  END desc_v
  PIN fault
    DIRECTION OUTPUT ;
    USE SIGNAL ;
    PORT
      LAYER M5 ;
        RECT  53.568 60.396 53.592 60.48 ;
    END
  END fault
  PIN launch_v
    DIRECTION INPUT ;
    USE SIGNAL ;
    PORT
      LAYER M5 ;
        RECT  53.712 60.396 53.736 60.48 ;
    END
  END launch_v
  PIN rst_n
    DIRECTION INPUT ;
    USE SIGNAL ;
    PORT
      LAYER M5 ;
        RECT  53.856 60.396 53.88 60.48 ;
    END
  END rst_n
  PIN run_base[0]
    DIRECTION OUTPUT ;
    USE SIGNAL ;
    PORT
      LAYER M5 ;
        RECT  6.912 0 6.936 0.084 ;
    END
  END run_base[0]
  PIN run_base[1]
    DIRECTION OUTPUT ;
    USE SIGNAL ;
    PORT
      LAYER M5 ;
        RECT  7.056 0 7.08 0.084 ;
    END
  END run_base[1]
  PIN run_base[2]
    DIRECTION OUTPUT ;
    USE SIGNAL ;
    PORT
      LAYER M5 ;
        RECT  7.2 0 7.224 0.084 ;
    END
  END run_base[2]
  PIN run_base[3]
    DIRECTION OUTPUT ;
    USE SIGNAL ;
    PORT
      LAYER M5 ;
        RECT  7.344 0 7.368 0.084 ;
    END
  END run_base[3]
  PIN run_base[4]
    DIRECTION OUTPUT ;
    USE SIGNAL ;
    PORT
      LAYER M5 ;
        RECT  7.488 0 7.512 0.084 ;
    END
  END run_base[4]
  PIN run_base[5]
    DIRECTION OUTPUT ;
    USE SIGNAL ;
    PORT
      LAYER M5 ;
        RECT  7.632 0 7.656 0.084 ;
    END
  END run_base[5]
  PIN run_base[6]
    DIRECTION OUTPUT ;
    USE SIGNAL ;
    PORT
      LAYER M5 ;
        RECT  7.776 0 7.8 0.084 ;
    END
  END run_base[6]
  PIN run_count[0]
    DIRECTION OUTPUT ;
    USE SIGNAL ;
    PORT
      LAYER M5 ;
        RECT  7.92 0 7.944 0.084 ;
    END
  END run_count[0]
  PIN run_count[1]
    DIRECTION OUTPUT ;
    USE SIGNAL ;
    PORT
      LAYER M5 ;
        RECT  8.064 0 8.088 0.084 ;
    END
  END run_count[1]
  PIN run_count[2]
    DIRECTION OUTPUT ;
    USE SIGNAL ;
    PORT
      LAYER M5 ;
        RECT  8.208 0 8.232 0.084 ;
    END
  END run_count[2]
  PIN run_count[3]
    DIRECTION OUTPUT ;
    USE SIGNAL ;
    PORT
      LAYER M5 ;
        RECT  8.352 0 8.376 0.084 ;
    END
  END run_count[3]
  PIN run_count[4]
    DIRECTION OUTPUT ;
    USE SIGNAL ;
    PORT
      LAYER M5 ;
        RECT  8.496 0 8.52 0.084 ;
    END
  END run_count[4]
  PIN run_count[5]
    DIRECTION OUTPUT ;
    USE SIGNAL ;
    PORT
      LAYER M5 ;
        RECT  8.64 0 8.664 0.084 ;
    END
  END run_count[5]
  PIN run_count[6]
    DIRECTION OUTPUT ;
    USE SIGNAL ;
    PORT
      LAYER M5 ;
        RECT  8.784 0 8.808 0.084 ;
    END
  END run_count[6]
  PIN run_count[7]
    DIRECTION OUTPUT ;
    USE SIGNAL ;
    PORT
      LAYER M5 ;
        RECT  8.928 0 8.952 0.084 ;
    END
  END run_count[7]
  PIN run_v
    DIRECTION OUTPUT ;
    USE SIGNAL ;
    PORT
      LAYER M5 ;
        RECT  9.072 0 9.096 0.084 ;
    END
  END run_v
  PIN tgt[0]
    DIRECTION INPUT ;
    USE SIGNAL ;
    PORT
      LAYER M5 ;
        RECT  54 60.396 54.024 60.48 ;
    END
  END tgt[0]
  PIN tgt[1]
    DIRECTION INPUT ;
    USE SIGNAL ;
    PORT
      LAYER M5 ;
        RECT  54.144 60.396 54.168 60.48 ;
    END
  END tgt[1]
  PIN tgt[2]
    DIRECTION INPUT ;
    USE SIGNAL ;
    PORT
      LAYER M5 ;
        RECT  54.288 60.396 54.312 60.48 ;
    END
  END tgt[2]
  PIN tgt[3]
    DIRECTION INPUT ;
    USE SIGNAL ;
    PORT
      LAYER M5 ;
        RECT  54.432 60.396 54.456 60.48 ;
    END
  END tgt[3]
  PIN tgt[4]
    DIRECTION INPUT ;
    USE SIGNAL ;
    PORT
      LAYER M5 ;
        RECT  54.576 60.396 54.6 60.48 ;
    END
  END tgt[4]
  PIN tgt[5]
    DIRECTION INPUT ;
    USE SIGNAL ;
    PORT
      LAYER M5 ;
        RECT  54.72 60.396 54.744 60.48 ;
    END
  END tgt[5]
  PIN tgt[6]
    DIRECTION INPUT ;
    USE SIGNAL ;
    PORT
      LAYER M5 ;
        RECT  54.864 60.396 54.888 60.48 ;
    END
  END tgt[6]
  PIN tgt[7]
    DIRECTION INPUT ;
    USE SIGNAL ;
    PORT
      LAYER M5 ;
        RECT  55.008 60.396 55.032 60.48 ;
    END
  END tgt[7]
  PIN tgt_active[0]
    DIRECTION INPUT ;
    USE SIGNAL ;
    PORT
      LAYER M5 ;
        RECT  9.216 0 9.24 0.084 ;
    END
  END tgt_active[0]
  PIN tgt_active[1]
    DIRECTION INPUT ;
    USE SIGNAL ;
    PORT
      LAYER M5 ;
        RECT  9.36 0 9.384 0.084 ;
    END
  END tgt_active[1]
  PIN tgt_fault[0]
    DIRECTION INPUT ;
    USE SIGNAL ;
    PORT
      LAYER M5 ;
        RECT  9.504 0 9.528 0.084 ;
    END
  END tgt_fault[0]
  PIN VDD
    DIRECTION INOUT ;
    USE POWER ;
    PORT
      LAYER M5 ;
        RECT  56.592 2.151 56.712 58.329 ;
        RECT  51.192 2.151 51.312 58.329 ;
        RECT  45.792 2.151 45.912 58.329 ;
        RECT  40.392 2.151 40.512 58.329 ;
        RECT  34.992 2.151 35.112 58.329 ;
        RECT  29.592 2.151 29.712 58.329 ;
        RECT  24.192 2.151 24.312 58.329 ;
        RECT  18.792 2.151 18.912 58.329 ;
        RECT  13.392 2.151 13.512 58.329 ;
        RECT  7.992 2.151 8.112 58.329 ;
        RECT  2.592 2.151 2.712 58.329 ;
    END
  END VDD
  PIN VSS
    DIRECTION INOUT ;
    USE GROUND ;
    PORT
      LAYER M5 ;
        RECT  56.4 2.137 56.52 58.343 ;
        RECT  51 2.137 51.12 58.343 ;
        RECT  45.6 2.137 45.72 58.343 ;
        RECT  40.2 2.137 40.32 58.343 ;
        RECT  34.8 2.137 34.92 58.343 ;
        RECT  29.4 2.137 29.52 58.343 ;
        RECT  24 2.137 24.12 58.343 ;
        RECT  18.6 2.137 18.72 58.343 ;
        RECT  13.2 2.137 13.32 58.343 ;
        RECT  7.8 2.137 7.92 58.343 ;
        RECT  2.4 2.137 2.52 58.343 ;
    END
  END VSS
  # OT_OBS_CLOSED layer=M5 d_um=1.536 added=80
  OBS
    LAYER RVTN ;
     RECT  2.16 2.16 58.32 2.295 ;
     RECT  2.16 2.565 58.32 2.835 ;
     RECT  2.16 3.105 58.32 3.375 ;
     RECT  2.16 3.645 58.32 3.915 ;
     RECT  2.16 4.185 58.32 4.455 ;
     RECT  2.16 4.725 58.32 4.995 ;
     RECT  2.16 5.265 58.32 5.535 ;
     RECT  2.16 5.805 58.32 6.075 ;
     RECT  2.16 6.345 58.32 6.615 ;
     RECT  2.16 6.885 58.32 7.155 ;
     RECT  2.16 7.425 58.32 7.695 ;
     RECT  2.16 7.965 58.32 8.235 ;
     RECT  2.16 8.505 58.32 8.775 ;
     RECT  2.16 9.045 58.32 9.315 ;
     RECT  2.16 9.585 58.32 9.855 ;
     RECT  2.16 10.125 58.32 10.395 ;
     RECT  2.16 10.665 58.32 10.935 ;
     RECT  2.16 11.205 58.32 11.475 ;
     RECT  2.16 11.745 58.32 12.015 ;
     RECT  2.16 12.285 58.32 12.555 ;
     RECT  2.16 12.825 58.32 13.095 ;
     RECT  2.16 13.365 58.32 13.635 ;
     RECT  2.16 13.905 58.32 14.175 ;
     RECT  2.16 14.445 58.32 14.715 ;
     RECT  2.16 14.985 58.32 15.255 ;
     RECT  2.16 15.525 58.32 15.795 ;
     RECT  2.16 16.065 58.32 16.335 ;
     RECT  2.16 16.605 58.32 16.875 ;
     RECT  2.16 17.145 58.32 17.415 ;
     RECT  2.16 17.685 58.32 17.955 ;
     RECT  2.16 18.225 58.32 18.495 ;
     RECT  2.16 18.765 58.32 19.035 ;
     RECT  2.16 19.305 58.32 19.575 ;
     RECT  2.16 19.845 58.32 20.115 ;
     RECT  2.16 20.385 58.32 20.655 ;
     RECT  2.16 20.925 58.32 21.195 ;
     RECT  2.16 21.465 58.32 21.735 ;
     RECT  2.16 22.005 58.32 22.275 ;
     RECT  2.16 22.545 58.32 22.815 ;
     RECT  2.16 23.085 58.32 23.355 ;
     RECT  2.16 23.625 58.32 23.895 ;
     RECT  2.16 24.165 58.32 24.435 ;
     RECT  2.16 24.705 58.32 24.975 ;
     RECT  2.16 25.245 58.32 25.515 ;
     RECT  2.16 25.785 58.32 26.055 ;
     RECT  2.16 26.325 58.32 26.595 ;
     RECT  2.16 26.865 58.32 27.135 ;
     RECT  2.16 27.405 58.32 27.675 ;
     RECT  2.16 27.945 58.32 28.215 ;
     RECT  2.16 28.485 58.32 28.755 ;
     RECT  2.16 29.025 58.32 29.295 ;
     RECT  2.16 29.565 58.32 29.835 ;
     RECT  2.16 30.105 58.32 30.375 ;
     RECT  2.16 30.645 58.32 30.915 ;
     RECT  2.16 31.185 58.32 31.455 ;
     RECT  2.16 31.725 58.32 31.995 ;
     RECT  2.16 32.265 58.32 32.535 ;
     RECT  2.16 32.805 58.32 33.075 ;
     RECT  2.16 33.345 58.32 33.615 ;
     RECT  2.16 33.885 58.32 34.155 ;
     RECT  2.16 34.425 58.32 34.695 ;
     RECT  2.16 34.965 58.32 35.235 ;
     RECT  2.16 35.505 58.32 35.775 ;
     RECT  2.16 36.045 58.32 36.315 ;
     RECT  2.16 36.585 58.32 36.855 ;
     RECT  2.16 37.125 58.32 37.395 ;
     RECT  2.16 37.665 58.32 37.935 ;
     RECT  2.16 38.205 58.32 38.475 ;
     RECT  2.16 38.745 58.32 39.015 ;
     RECT  2.16 39.285 58.32 39.555 ;
     RECT  2.16 39.825 58.32 40.095 ;
     RECT  2.16 40.365 58.32 40.635 ;
     RECT  2.16 40.905 58.32 41.175 ;
     RECT  2.16 41.445 58.32 41.715 ;
     RECT  2.16 41.985 58.32 42.255 ;
     RECT  2.16 42.525 58.32 42.795 ;
     RECT  2.16 43.065 58.32 43.335 ;
     RECT  2.16 43.605 58.32 43.875 ;
     RECT  2.16 44.145 58.32 44.415 ;
     RECT  2.16 44.685 58.32 44.955 ;
     RECT  2.16 45.225 58.32 45.495 ;
     RECT  2.16 45.765 58.32 46.035 ;
     RECT  2.16 46.305 58.32 46.575 ;
     RECT  2.16 46.845 58.32 47.115 ;
     RECT  2.16 47.385 58.32 47.655 ;
     RECT  2.16 47.925 58.32 48.195 ;
     RECT  2.16 48.465 58.32 48.735 ;
     RECT  2.16 49.005 58.32 49.275 ;
     RECT  2.16 49.545 58.32 49.815 ;
     RECT  2.16 50.085 58.32 50.355 ;
     RECT  2.16 50.625 58.32 50.895 ;
     RECT  2.16 51.165 58.32 51.435 ;
     RECT  2.16 51.705 58.32 51.975 ;
     RECT  2.16 52.245 58.32 52.515 ;
     RECT  2.16 52.785 58.32 53.055 ;
     RECT  2.16 53.325 58.32 53.595 ;
     RECT  2.16 53.865 58.32 54.135 ;
     RECT  2.16 54.405 58.32 54.675 ;
     RECT  2.16 54.945 58.32 55.215 ;
     RECT  2.16 55.485 58.32 55.755 ;
     RECT  2.16 56.025 58.32 56.295 ;
     RECT  2.16 56.565 58.32 56.835 ;
     RECT  2.16 57.105 58.32 57.375 ;
     RECT  2.16 57.645 58.32 57.915 ;
     RECT  2.16 58.185 58.32 58.32 ;
    LAYER RVTP ;
     RECT  2.16 2.295 58.32 2.565 ;
     RECT  2.16 2.835 58.32 3.105 ;
     RECT  2.16 3.375 58.32 3.645 ;
     RECT  2.16 3.915 58.32 4.185 ;
     RECT  2.16 4.455 58.32 4.725 ;
     RECT  2.16 4.995 58.32 5.265 ;
     RECT  2.16 5.535 58.32 5.805 ;
     RECT  2.16 6.075 58.32 6.345 ;
     RECT  2.16 6.615 58.32 6.885 ;
     RECT  2.16 7.155 58.32 7.425 ;
     RECT  2.16 7.695 58.32 7.965 ;
     RECT  2.16 8.235 58.32 8.505 ;
     RECT  2.16 8.775 58.32 9.045 ;
     RECT  2.16 9.315 58.32 9.585 ;
     RECT  2.16 9.855 58.32 10.125 ;
     RECT  2.16 10.395 58.32 10.665 ;
     RECT  2.16 10.935 58.32 11.205 ;
     RECT  2.16 11.475 58.32 11.745 ;
     RECT  2.16 12.015 58.32 12.285 ;
     RECT  2.16 12.555 58.32 12.825 ;
     RECT  2.16 13.095 58.32 13.365 ;
     RECT  2.16 13.635 58.32 13.905 ;
     RECT  2.16 14.175 58.32 14.445 ;
     RECT  2.16 14.715 58.32 14.985 ;
     RECT  2.16 15.255 58.32 15.525 ;
     RECT  2.16 15.795 58.32 16.065 ;
     RECT  2.16 16.335 58.32 16.605 ;
     RECT  2.16 16.875 58.32 17.145 ;
     RECT  2.16 17.415 58.32 17.685 ;
     RECT  2.16 17.955 58.32 18.225 ;
     RECT  2.16 18.495 58.32 18.765 ;
     RECT  2.16 19.035 58.32 19.305 ;
     RECT  2.16 19.575 58.32 19.845 ;
     RECT  2.16 20.115 58.32 20.385 ;
     RECT  2.16 20.655 58.32 20.925 ;
     RECT  2.16 21.195 58.32 21.465 ;
     RECT  2.16 21.735 58.32 22.005 ;
     RECT  2.16 22.275 58.32 22.545 ;
     RECT  2.16 22.815 58.32 23.085 ;
     RECT  2.16 23.355 58.32 23.625 ;
     RECT  2.16 23.895 58.32 24.165 ;
     RECT  2.16 24.435 58.32 24.705 ;
     RECT  2.16 24.975 58.32 25.245 ;
     RECT  2.16 25.515 58.32 25.785 ;
     RECT  2.16 26.055 58.32 26.325 ;
     RECT  2.16 26.595 58.32 26.865 ;
     RECT  2.16 27.135 58.32 27.405 ;
     RECT  2.16 27.675 58.32 27.945 ;
     RECT  2.16 28.215 58.32 28.485 ;
     RECT  2.16 28.755 58.32 29.025 ;
     RECT  2.16 29.295 58.32 29.565 ;
     RECT  2.16 29.835 58.32 30.105 ;
     RECT  2.16 30.375 58.32 30.645 ;
     RECT  2.16 30.915 58.32 31.185 ;
     RECT  2.16 31.455 58.32 31.725 ;
     RECT  2.16 31.995 58.32 32.265 ;
     RECT  2.16 32.535 58.32 32.805 ;
     RECT  2.16 33.075 58.32 33.345 ;
     RECT  2.16 33.615 58.32 33.885 ;
     RECT  2.16 34.155 58.32 34.425 ;
     RECT  2.16 34.695 58.32 34.965 ;
     RECT  2.16 35.235 58.32 35.505 ;
     RECT  2.16 35.775 58.32 36.045 ;
     RECT  2.16 36.315 58.32 36.585 ;
     RECT  2.16 36.855 58.32 37.125 ;
     RECT  2.16 37.395 58.32 37.665 ;
     RECT  2.16 37.935 58.32 38.205 ;
     RECT  2.16 38.475 58.32 38.745 ;
     RECT  2.16 39.015 58.32 39.285 ;
     RECT  2.16 39.555 58.32 39.825 ;
     RECT  2.16 40.095 58.32 40.365 ;
     RECT  2.16 40.635 58.32 40.905 ;
     RECT  2.16 41.175 58.32 41.445 ;
     RECT  2.16 41.715 58.32 41.985 ;
     RECT  2.16 42.255 58.32 42.525 ;
     RECT  2.16 42.795 58.32 43.065 ;
     RECT  2.16 43.335 58.32 43.605 ;
     RECT  2.16 43.875 58.32 44.145 ;
     RECT  2.16 44.415 58.32 44.685 ;
     RECT  2.16 44.955 58.32 45.225 ;
     RECT  2.16 45.495 58.32 45.765 ;
     RECT  2.16 46.035 58.32 46.305 ;
     RECT  2.16 46.575 58.32 46.845 ;
     RECT  2.16 47.115 58.32 47.385 ;
     RECT  2.16 47.655 58.32 47.925 ;
     RECT  2.16 48.195 58.32 48.465 ;
     RECT  2.16 48.735 58.32 49.005 ;
     RECT  2.16 49.275 58.32 49.545 ;
     RECT  2.16 49.815 58.32 50.085 ;
     RECT  2.16 50.355 58.32 50.625 ;
     RECT  2.16 50.895 58.32 51.165 ;
     RECT  2.16 51.435 58.32 51.705 ;
     RECT  2.16 51.975 58.32 52.245 ;
     RECT  2.16 52.515 58.32 52.785 ;
     RECT  2.16 53.055 58.32 53.325 ;
     RECT  2.16 53.595 58.32 53.865 ;
     RECT  2.16 54.135 58.32 54.405 ;
     RECT  2.16 54.675 58.32 54.945 ;
     RECT  2.16 55.215 58.32 55.485 ;
     RECT  2.16 55.755 58.32 56.025 ;
     RECT  2.16 56.295 58.32 56.565 ;
     RECT  2.16 56.835 58.32 57.105 ;
     RECT  2.16 57.375 58.32 57.645 ;
     RECT  2.16 57.915 58.32 58.185 ;
    LAYER M1 ;
     RECT  2.16 2.151 58.32 58.329 ;
    LAYER M2 ;
     RECT  0.103 17.082 0.499 17.604 ;
     RECT  0.499 16.884 0.535 17.604 ;
     RECT  0.535 16.884 2.16 17.982 ;
     RECT  0.103 18.774 2.16 18.792 ;
     RECT  2.16 2.151 6.799 58.329 ;
     RECT  6.799 2.106 7.151 58.329 ;
     RECT  7.151 2.151 11.191 58.329 ;
     RECT  11.191 2.106 12.191 58.329 ;
     RECT  12.191 2.151 13.171 58.329 ;
     RECT  13.171 2.151 13.559 58.518 ;
     RECT  14.287 1.152 14.603 1.17 ;
     RECT  13.559 2.151 18.535 58.329 ;
     RECT  18.535 2.151 18.779 58.518 ;
     RECT  18.779 2.151 20.407 58.329 ;
     RECT  20.407 2.106 20.615 58.329 ;
     RECT  20.615 2.151 24.655 58.329 ;
     RECT  24.655 2.106 25.331 58.329 ;
     RECT  25.331 2.151 27.247 58.329 ;
     RECT  27.247 1.836 27.563 58.329 ;
     RECT  27.563 2.106 28.291 58.329 ;
     RECT  28.291 2.07 28.859 58.329 ;
     RECT  28.859 2.106 29.003 58.329 ;
     RECT  34.483 1.152 34.583 1.17 ;
     RECT  29.003 2.151 38.479 58.329 ;
     RECT  38.479 2.106 39.731 58.329 ;
     RECT  39.731 2.151 42.331 58.329 ;
     RECT  42.331 2.106 42.683 58.329 ;
     RECT  42.683 2.151 43.699 58.329 ;
     RECT  43.699 2.106 44.771 58.329 ;
     RECT  44.771 2.151 51.367 58.329 ;
     RECT  51.367 2.106 53.059 58.329 ;
     RECT  53.059 2.034 53.771 58.329 ;
     RECT  53.771 2.151 58.32 58.329 ;
     RECT  58.32 9.936 59.279 27.9 ;
     RECT  58.32 29.196 59.279 40.014 ;
     RECT  59.279 27.684 59.315 27.9 ;
     RECT  59.279 29.196 59.315 39.546 ;
     RECT  59.279 20.862 59.855 26.784 ;
     RECT  59.315 27.846 59.855 27.9 ;
     RECT  59.315 36.486 59.855 39.546 ;
     RECT  59.279 9.936 59.891 20.034 ;
     RECT  59.855 20.862 59.891 26.694 ;
     RECT  59.315 29.196 59.891 35.496 ;
     RECT  59.855 36.486 59.891 36.774 ;
     RECT  59.855 37.566 59.891 39.546 ;
     RECT  58.32 42.696 59.891 52.272 ;
     RECT  59.891 10.134 59.927 12.348 ;
     RECT  59.891 13.14 59.927 13.464 ;
     RECT  59.891 14.256 59.927 14.508 ;
     RECT  59.891 17.766 59.927 20.034 ;
     RECT  59.891 20.862 59.927 20.88 ;
     RECT  59.891 21.636 59.927 23.418 ;
     RECT  59.891 25.254 59.927 26.694 ;
     RECT  59.855 27.882 59.927 27.9 ;
     RECT  59.891 29.646 59.927 29.664 ;
     RECT  59.891 34.866 59.927 34.884 ;
     RECT  59.891 43.308 59.927 44.172 ;
     RECT  59.891 47.088 59.927 49.644 ;
     RECT  59.891 50.562 59.927 52.272 ;
     RECT  59.927 10.134 59.963 11.772 ;
     RECT  59.927 14.49 59.963 14.508 ;
     RECT  59.891 15.264 59.963 16.668 ;
     RECT  59.891 30.42 59.963 34.074 ;
     RECT  59.891 37.944 59.963 39.546 ;
     RECT  59.927 43.416 59.963 44.136 ;
     RECT  59.927 47.088 59.963 48.024 ;
     RECT  59.927 49.05 59.963 49.068 ;
     RECT  59.927 51.174 59.963 52.272 ;
     RECT  59.963 16.416 59.999 16.434 ;
     RECT  59.963 51.174 59.999 51.768 ;
     RECT  59.927 18.036 60.323 20.034 ;
     RECT  59.963 37.944 60.323 38.736 ;
     RECT  59.963 15.264 60.359 15.624 ;
     RECT  59.927 22.176 60.359 23.418 ;
     RECT  59.927 26.334 60.359 26.694 ;
     RECT  59.963 30.42 60.359 31.14 ;
     RECT  60.323 37.944 60.359 38.7 ;
     RECT  59.963 10.134 60.395 11.268 ;
     RECT  59.927 13.446 60.395 13.464 ;
     RECT  60.359 15.264 60.395 15.552 ;
     RECT  60.323 18.036 60.395 18.486 ;
     RECT  60.323 19.314 60.395 20.034 ;
     RECT  60.359 22.176 60.395 23.184 ;
     RECT  59.891 24.246 60.395 24.462 ;
     RECT  59.927 25.254 60.395 25.272 ;
     RECT  60.359 26.334 60.395 26.352 ;
     RECT  60.359 30.456 60.395 31.14 ;
     RECT  59.963 31.896 60.395 34.074 ;
     RECT  59.891 36.486 60.395 36.504 ;
     RECT  60.359 37.944 60.395 38.538 ;
     RECT  59.963 39.528 60.395 39.546 ;
     RECT  59.963 44.118 60.395 44.136 ;
     RECT  59.963 47.826 60.395 47.844 ;
     RECT  59.999 51.174 60.395 51.66 ;
    LAYER M3 ;
     RECT  12.636 0.091 12.654 0.139 ;
     RECT  28.116 0.091 28.134 0.139 ;
     RECT  24.444 0.091 24.462 0.365 ;
     RECT  5.148 0.091 7.722 0.523 ;
     RECT  8.82 0.091 8.838 0.571 ;
     RECT  10.368 0.523 10.386 0.571 ;
     RECT  14.292 0.091 14.31 0.571 ;
     RECT  19.656 0.091 20.178 0.571 ;
     RECT  21.492 0.091 21.51 0.571 ;
     RECT  22.896 0.091 23.49 0.571 ;
     RECT  36.324 0.091 38.61 0.571 ;
     RECT  44.82 0.091 45.126 0.571 ;
     RECT  48.78 0.091 50.022 0.571 ;
     RECT  5.148 0.523 7.794 1.099 ;
     RECT  26.316 0.571 26.334 1.099 ;
     RECT  41.724 0.571 41.742 1.099 ;
     RECT  46.8 0.091 47.718 1.099 ;
     RECT  50.94 0.571 50.958 1.099 ;
     RECT  10.368 0.571 10.602 1.147 ;
     RECT  11.376 0.523 11.394 1.147 ;
     RECT  12.636 0.139 12.906 1.147 ;
     RECT  14.112 0.571 14.31 1.147 ;
     RECT  15.66 0.091 16.362 1.147 ;
     RECT  17.424 0.091 17.442 1.147 ;
     RECT  18.504 0.091 18.522 1.147 ;
     RECT  34.092 0.091 35.19 1.147 ;
     RECT  36.288 0.571 38.61 1.147 ;
     RECT  48.636 0.571 50.022 1.147 ;
     RECT  50.868 1.099 50.958 1.147 ;
     RECT  39.456 1.099 39.474 1.627 ;
     RECT  10.368 1.147 11.394 1.675 ;
     RECT  46.044 0.235 46.062 1.675 ;
     RECT  46.8 1.099 47.754 1.675 ;
     RECT  5.004 1.099 7.794 1.723 ;
     RECT  8.784 0.571 8.838 1.723 ;
     RECT  9.936 1.675 11.394 1.723 ;
     RECT  14.112 1.147 16.362 1.723 ;
     RECT  17.424 1.147 18.522 1.723 ;
     RECT  19.584 0.571 20.61 1.723 ;
     RECT  21.492 0.571 24.174 1.723 ;
     RECT  26.028 1.099 26.802 1.723 ;
     RECT  28.116 0.139 28.206 1.723 ;
     RECT  34.092 1.147 38.61 1.723 ;
     RECT  39.456 1.627 39.978 1.723 ;
     RECT  41.148 1.099 41.742 1.723 ;
     RECT  42.48 0.091 43.686 1.723 ;
     RECT  44.784 0.571 45.126 1.723 ;
     RECT  46.044 1.675 47.754 1.723 ;
     RECT  48.636 1.147 50.958 1.723 ;
     RECT  5.004 1.723 11.898 1.771 ;
     RECT  12.636 1.147 12.978 1.771 ;
     RECT  13.788 1.723 26.802 1.771 ;
     RECT  52.452 1.723 52.47 1.771 ;
     RECT  13.788 1.771 27.342 1.819 ;
     RECT  28.116 1.723 28.89 1.819 ;
     RECT  44.424 1.723 51.174 1.819 ;
     RECT  52.452 1.771 52.83 1.819 ;
     RECT  13.788 1.819 28.89 1.867 ;
     RECT  29.628 1.771 29.646 1.867 ;
     RECT  5.004 1.771 12.978 2.011 ;
     RECT  13.788 1.867 29.646 2.011 ;
     RECT  44.424 1.819 52.83 2.029 ;
     RECT  34.092 1.723 43.686 2.101 ;
     RECT  44.424 2.029 53.766 2.101 ;
     RECT  5.004 2.011 29.646 2.263 ;
     RECT  4.968 2.263 29.79 2.335 ;
     RECT  34.092 2.101 53.766 2.371 ;
     RECT  2.415 2.143 2.505 2.413 ;
     RECT  56.415 2.143 56.505 2.413 ;
     RECT  4.968 2.335 30.186 2.533 ;
     RECT  4.968 2.533 30.87 2.605 ;
     RECT  34.092 2.371 54.342 2.795 ;
     RECT  34.092 2.795 54.09 2.803 ;
     RECT  4.716 2.605 30.87 3.145 ;
     RECT  4.716 3.145 31.158 3.379 ;
     RECT  32.508 3.271 32.526 3.379 ;
     RECT  33.84 2.803 54.09 3.541 ;
     RECT  4.716 3.379 32.526 3.649 ;
     RECT  4.716 3.649 32.67 3.721 ;
     RECT  33.624 3.541 54.09 3.721 ;
     RECT  4.716 3.721 54.198 3.773 ;
     RECT  33.48 3.773 54.198 3.919 ;
     RECT  4.716 3.773 32.67 3.983 ;
     RECT  33.48 3.919 54.234 4.495 ;
     RECT  4.716 3.983 32.526 4.531 ;
     RECT  33.408 4.495 54.234 4.541 ;
     RECT  33.552 4.541 54.234 4.559 ;
     RECT  4.572 4.531 32.526 4.649 ;
     RECT  33.552 4.559 54.126 5.333 ;
     RECT  33.588 5.333 54.126 6.691 ;
     RECT  4.572 4.649 32.382 6.845 ;
     RECT  10.692 6.845 32.382 7.349 ;
     RECT  10.692 7.349 11.178 7.457 ;
     RECT  12.06 7.349 32.382 7.457 ;
     RECT  12.312 7.457 32.382 7.897 ;
     RECT  4.572 6.845 9.81 7.933 ;
     RECT  12.312 7.897 32.418 7.933 ;
     RECT  12.312 7.933 32.49 8.011 ;
     RECT  4.572 7.933 9.918 8.311 ;
     RECT  10.692 7.457 11.07 8.311 ;
     RECT  12.312 8.011 32.814 8.339 ;
     RECT  4.572 8.311 11.07 8.429 ;
     RECT  12.456 8.339 32.814 8.537 ;
     RECT  4.572 8.429 9.918 8.699 ;
     RECT  12.456 8.537 32.382 9.113 ;
     RECT  12.6 9.113 32.382 9.347 ;
     RECT  12.6 9.347 13.497 9.419 ;
     RECT  14.22 9.347 32.382 9.751 ;
     RECT  33.552 6.691 54.126 9.751 ;
     RECT  59.868 9.925 59.886 10.075 ;
     RECT  59.868 10.075 60.39 11.273 ;
     RECT  56.415 2.413 56.697 11.983 ;
     RECT  56.415 11.983 56.79 12.125 ;
     RECT  4.572 8.699 9.882 12.289 ;
     RECT  10.692 8.429 11.07 12.289 ;
     RECT  14.22 9.751 54.126 12.317 ;
     RECT  33.12 12.317 54.126 12.515 ;
     RECT  59.868 11.273 59.958 12.571 ;
     RECT  4.572 12.289 11.07 13.019 ;
     RECT  59.868 12.571 60.318 13.387 ;
     RECT  59.868 13.387 60.39 13.469 ;
     RECT  4.572 13.019 9.918 13.829 ;
     RECT  14.22 12.317 32.382 13.945 ;
     RECT  2.415 2.413 2.697 14.143 ;
     RECT  4.572 13.829 9.774 14.171 ;
     RECT  14.22 13.945 32.454 14.171 ;
     RECT  2.415 14.143 3.402 14.215 ;
     RECT  4.572 14.171 9.702 14.215 ;
     RECT  59.868 13.469 59.886 14.251 ;
     RECT  59.868 14.251 60.318 14.381 ;
     RECT  2.415 14.215 9.702 14.675 ;
     RECT  59.868 14.381 59.958 15.115 ;
     RECT  59.868 15.115 60.39 15.557 ;
     RECT  2.415 14.675 9.558 15.601 ;
     RECT  59.868 15.557 60.354 15.629 ;
     RECT  59.868 15.629 59.958 16.411 ;
     RECT  2.415 15.601 9.81 16.835 ;
     RECT  14.22 14.171 32.382 16.891 ;
     RECT  14.22 16.891 32.814 16.939 ;
     RECT  33.552 12.515 54.126 16.939 ;
     RECT  0.504 16.879 0.522 16.951 ;
     RECT  0.504 16.951 0.558 17.077 ;
     RECT  59.868 16.411 59.994 17.179 ;
     RECT  14.22 16.939 54.126 17.339 ;
     RECT  56.415 12.125 56.697 17.467 ;
     RECT  56.415 17.467 56.79 17.597 ;
     RECT  0.108 17.077 0.558 17.741 ;
     RECT  59.868 17.179 60.318 17.741 ;
     RECT  2.415 16.835 9.774 17.851 ;
     RECT  59.904 17.741 60.318 17.851 ;
     RECT  2.304 17.851 9.774 18.059 ;
     RECT  0.54 17.741 0.558 18.317 ;
     RECT  59.904 17.851 60.39 18.565 ;
     RECT  2.412 18.059 9.774 18.571 ;
     RECT  2.412 18.571 9.918 18.805 ;
     RECT  2.412 18.805 9.954 18.841 ;
     RECT  10.692 13.019 11.07 18.841 ;
     RECT  56.415 17.597 56.697 18.841 ;
     RECT  0.108 18.769 0.126 18.893 ;
     RECT  56.415 18.841 57.294 18.967 ;
     RECT  56.415 18.967 57.69 18.995 ;
     RECT  2.412 18.841 11.07 19.003 ;
     RECT  59.868 18.565 60.39 19.039 ;
     RECT  57.672 18.995 57.69 19.067 ;
     RECT  33.552 17.339 54.126 19.075 ;
     RECT  58.14 19.111 58.158 19.181 ;
     RECT  33.552 19.075 54.702 19.345 ;
     RECT  33.552 19.345 54.738 19.381 ;
     RECT  59.256 19.039 60.39 19.435 ;
     RECT  33.552 19.381 54.954 19.499 ;
     RECT  58.68 19.435 60.39 19.499 ;
     RECT  56.415 18.995 56.697 19.507 ;
     RECT  33.552 19.499 54.738 19.535 ;
     RECT  59.292 19.499 60.39 19.613 ;
     RECT  56.196 19.507 56.697 19.651 ;
     RECT  33.552 19.535 54.594 19.661 ;
     RECT  56.052 19.651 56.697 20.011 ;
     RECT  59.868 19.613 60.39 20.039 ;
     RECT  59.868 20.039 60.354 20.045 ;
     RECT  56.016 20.011 56.697 20.155 ;
     RECT  60.336 20.045 60.354 20.189 ;
     RECT  56.016 20.155 57.402 20.309 ;
     RECT  58.14 20.191 58.158 20.333 ;
     RECT  33.552 19.661 54.45 20.389 ;
     RECT  56.016 20.309 57.006 20.389 ;
     RECT  2.304 19.003 11.07 20.453 ;
     RECT  58.68 20.353 58.734 20.587 ;
     RECT  58.68 20.587 59.274 20.624 ;
     RECT  2.304 20.453 9.774 21.019 ;
     RECT  2.268 21.019 9.774 21.119 ;
     RECT  58.68 20.624 58.734 21.451 ;
     RECT  59.832 20.857 59.922 21.451 ;
     RECT  33.552 20.389 57.006 21.569 ;
     RECT  58.68 21.451 59.922 21.569 ;
     RECT  59.22 21.569 59.922 21.595 ;
     RECT  57.528 21.631 57.546 21.731 ;
     RECT  2.304 21.119 9.774 21.775 ;
     RECT  2.304 21.775 9.846 21.929 ;
     RECT  59.22 21.595 60.39 21.929 ;
     RECT  2.304 21.929 9.774 22.037 ;
     RECT  59.256 21.929 60.39 22.109 ;
     RECT  2.34 22.037 9.774 22.199 ;
     RECT  33.552 21.569 56.697 22.235 ;
     RECT  59.292 22.109 60.39 22.493 ;
     RECT  2.415 22.199 9.774 22.811 ;
     RECT  56.415 22.235 56.697 22.855 ;
     RECT  56.415 22.855 56.934 23.053 ;
     RECT  56.415 23.053 57.006 23.125 ;
     RECT  57.744 22.981 57.762 23.125 ;
     RECT  58.68 23.035 58.698 23.125 ;
     RECT  59.832 22.493 60.39 23.189 ;
     RECT  33.552 22.235 55.566 23.275 ;
     RECT  56.415 23.125 58.698 23.275 ;
     RECT  33.552 23.275 58.698 23.315 ;
     RECT  58.14 23.315 58.698 23.323 ;
     RECT  59.832 23.189 60.354 23.323 ;
     RECT  58.14 23.323 60.354 23.357 ;
     RECT  3.96 22.811 9.774 23.423 ;
     RECT  58.644 23.357 60.354 23.423 ;
     RECT  33.552 23.315 57.258 23.549 ;
     RECT  58.644 23.423 59.922 23.693 ;
     RECT  33.552 23.549 57.078 23.819 ;
     RECT  58.716 23.693 59.922 23.933 ;
     RECT  4.536 23.423 9.774 23.963 ;
     RECT  33.552 23.819 57.006 24.125 ;
     RECT  33.552 24.125 56.934 24.161 ;
     RECT  59.868 23.933 59.922 24.187 ;
     RECT  33.552 24.161 56.718 24.395 ;
     RECT  58.716 23.933 58.734 24.509 ;
     RECT  33.552 24.395 55.674 24.629 ;
     RECT  59.868 24.187 60.39 24.763 ;
     RECT  33.552 24.629 55.314 24.899 ;
     RECT  56.415 24.395 56.718 24.907 ;
     RECT  56.415 24.907 56.79 25.085 ;
     RECT  56.415 25.085 56.697 25.249 ;
     RECT  57.456 25.141 57.474 25.277 ;
     RECT  56.232 25.249 56.697 25.511 ;
     RECT  55.296 24.899 55.314 25.517 ;
     RECT  59.832 24.763 60.39 25.627 ;
     RECT  33.552 24.899 54.342 25.951 ;
     RECT  2.415 22.811 2.697 26.059 ;
     RECT  2.415 26.059 3.258 26.249 ;
     RECT  33.552 25.951 54.738 26.257 ;
     RECT  56.415 25.511 56.697 26.257 ;
     RECT  57.6 26.221 57.618 26.257 ;
     RECT  0.108 26.203 0.126 26.333 ;
     RECT  59.256 25.627 60.39 26.357 ;
     RECT  59.256 26.357 60.354 26.365 ;
     RECT  4.572 23.963 9.774 26.401 ;
     RECT  4.032 26.401 9.774 26.627 ;
     RECT  56.415 26.257 57.618 26.635 ;
     RECT  33.552 26.257 54.81 26.671 ;
     RECT  55.944 26.635 57.762 26.671 ;
     RECT  58.68 26.365 60.354 26.699 ;
     RECT  13.215 9.419 13.497 26.731 ;
     RECT  14.22 17.339 32.382 26.731 ;
     RECT  13.215 26.731 32.382 26.789 ;
     RECT  58.68 26.699 59.85 26.789 ;
     RECT  33.552 26.671 57.762 26.825 ;
     RECT  55.764 26.825 57.762 26.869 ;
     RECT  58.68 26.789 59.346 26.869 ;
     RECT  33.552 26.825 54.846 27.197 ;
     RECT  33.552 27.197 54.81 27.239 ;
     RECT  33.552 27.239 54.702 27.248 ;
     RECT  33.552 27.248 54.63 27.329 ;
     RECT  33.552 27.329 54.378 27.365 ;
     RECT  55.764 26.869 59.346 27.365 ;
     RECT  58.14 27.365 59.346 27.389 ;
     RECT  55.764 27.365 57.186 27.743 ;
     RECT  58.14 27.389 58.194 27.779 ;
     RECT  59.292 27.389 59.346 27.787 ;
     RECT  59.292 27.787 59.85 27.877 ;
     RECT  55.764 27.743 56.697 27.905 ;
     RECT  59.292 27.877 59.922 27.965 ;
     RECT  58.176 27.779 58.194 28.109 ;
     RECT  59.904 27.965 59.922 28.253 ;
     RECT  33.552 27.365 54.126 29.605 ;
     RECT  59.868 29.191 59.886 29.641 ;
     RECT  59.868 29.641 59.922 29.659 ;
     RECT  56.415 27.905 56.697 29.731 ;
     RECT  14.22 26.789 32.382 29.803 ;
     RECT  59.868 29.659 60.318 29.837 ;
     RECT  56.415 29.731 56.79 29.981 ;
     RECT  14.22 29.803 32.454 30.181 ;
     RECT  59.904 29.837 60.318 30.235 ;
     RECT  14.22 30.181 32.526 30.271 ;
     RECT  33.336 29.605 54.126 30.271 ;
     RECT  59.904 30.235 60.39 30.613 ;
     RECT  56.415 29.981 56.697 31.243 ;
     RECT  56.304 31.243 56.697 31.289 ;
     RECT  59.868 30.613 60.39 31.565 ;
     RECT  59.94 31.565 60.39 32.305 ;
     RECT  13.215 26.789 13.497 32.773 ;
     RECT  14.22 30.271 54.126 32.773 ;
     RECT  13.215 32.773 54.126 33.655 ;
     RECT  57.492 33.619 57.51 33.853 ;
     RECT  56.415 31.289 56.697 33.889 ;
     RECT  57.492 33.853 57.618 33.889 ;
     RECT  56.415 33.889 57.618 33.925 ;
     RECT  59.868 32.305 60.39 34.079 ;
     RECT  13.215 33.655 54.81 34.115 ;
     RECT  58.716 33.961 58.734 34.157 ;
     RECT  56.376 33.925 57.618 34.159 ;
     RECT  56.304 34.159 57.618 34.501 ;
     RECT  59.868 34.079 59.922 34.555 ;
     RECT  55.872 34.501 57.618 34.655 ;
     RECT  57.528 34.655 57.618 34.663 ;
     RECT  57.528 34.663 57.978 34.693 ;
     RECT  57.528 34.693 58.158 34.727 ;
     RECT  59.832 34.555 59.922 34.735 ;
     RECT  57.96 34.727 58.158 34.799 ;
     RECT  55.872 34.655 56.697 34.925 ;
     RECT  33.552 34.115 54.126 35.005 ;
     RECT  59.256 34.735 59.922 35.021 ;
     RECT  33.552 35.005 54.738 35.195 ;
     RECT  59.868 35.021 59.922 35.453 ;
     RECT  56.415 34.925 56.697 35.473 ;
     RECT  56.415 35.473 57.294 35.573 ;
     RECT  58.68 35.275 58.734 35.609 ;
     RECT  59.868 35.453 59.886 35.741 ;
     RECT  33.552 35.195 54.702 36.085 ;
     RECT  58.716 35.609 58.734 36.121 ;
     RECT  58.716 36.121 59.31 36.173 ;
     RECT  33.552 36.085 54.738 36.517 ;
     RECT  57.852 36.355 57.87 36.653 ;
     RECT  58.716 36.173 58.734 36.749 ;
     RECT  60.372 36.427 60.39 36.751 ;
     RECT  56.415 35.573 56.697 36.787 ;
     RECT  33.552 36.517 54.81 36.887 ;
     RECT  59.832 36.751 60.39 37.021 ;
     RECT  55.296 36.895 55.314 37.085 ;
     RECT  56.304 36.787 56.697 37.435 ;
     RECT  56.232 37.435 56.697 37.625 ;
     RECT  56.415 37.625 56.697 37.741 ;
     RECT  59.256 37.021 60.39 37.831 ;
     RECT  58.68 37.831 60.39 37.901 ;
     RECT  56.415 37.741 57.33 37.939 ;
     RECT  33.552 36.887 54.126 38.011 ;
     RECT  56.415 37.939 57.546 38.129 ;
     RECT  33.156 38.011 54.126 38.137 ;
     RECT  58.716 37.901 60.39 38.189 ;
     RECT  56.415 38.129 57.402 38.309 ;
     RECT  59.256 38.189 60.39 38.399 ;
     RECT  33.156 38.137 54.738 38.434 ;
     RECT  59.868 38.399 60.39 38.543 ;
     RECT  33.156 38.434 54.774 38.669 ;
     RECT  56.415 38.309 57.042 38.678 ;
     RECT  59.868 38.543 60.354 38.705 ;
     RECT  4.572 26.627 9.774 38.713 ;
     RECT  10.692 20.453 11.07 38.713 ;
     RECT  56.415 38.678 57.006 38.717 ;
     RECT  4.572 38.713 11.07 39.217 ;
     RECT  4.572 39.217 11.286 39.325 ;
     RECT  4.572 39.325 11.646 39.352 ;
     RECT  4.572 39.352 11.718 39.389 ;
     RECT  59.868 38.705 60.318 39.451 ;
     RECT  59.868 39.451 60.39 39.551 ;
     RECT  59.868 39.551 59.886 39.629 ;
     RECT  59.256 39.739 59.274 40.019 ;
     RECT  56.415 38.717 56.697 40.027 ;
     RECT  55.332 39.631 55.35 40.063 ;
     RECT  55.152 40.063 55.35 40.099 ;
     RECT  56.124 40.027 56.697 40.099 ;
     RECT  55.152 40.099 56.697 40.109 ;
     RECT  33.156 38.669 54.126 40.261 ;
     RECT  55.728 40.109 56.697 40.289 ;
     RECT  4.572 39.389 11.646 40.333 ;
     RECT  33.156 40.261 54.414 40.405 ;
     RECT  4.572 40.333 11.682 40.703 ;
     RECT  4.572 40.703 10.566 41.009 ;
     RECT  59.868 42.691 59.886 43.303 ;
     RECT  59.868 43.303 59.922 43.387 ;
     RECT  59.868 43.387 60.318 43.915 ;
     RECT  56.415 40.289 56.697 44.077 ;
     RECT  59.868 43.915 60.39 44.141 ;
     RECT  56.415 44.077 56.754 44.177 ;
     RECT  56.415 44.177 56.697 44.203 ;
     RECT  56.304 44.203 56.697 44.249 ;
     RECT  59.868 44.141 60.318 44.909 ;
     RECT  56.415 44.249 56.697 45.067 ;
     RECT  56.415 45.067 56.79 45.149 ;
     RECT  59.868 44.909 59.886 45.427 ;
     RECT  59.292 45.427 59.886 45.677 ;
     RECT  58.14 45.967 58.158 46.237 ;
     RECT  58.14 46.237 58.734 46.253 ;
     RECT  58.716 46.253 58.734 46.397 ;
     RECT  56.415 45.149 56.697 46.645 ;
     RECT  56.415 46.645 56.79 46.685 ;
     RECT  59.868 45.677 59.886 46.741 ;
     RECT  4.572 41.009 9.702 46.769 ;
     RECT  59.292 46.741 59.886 46.829 ;
     RECT  59.832 46.829 59.886 47.083 ;
     RECT  59.832 47.083 59.958 47.219 ;
     RECT  58.14 47.155 58.158 47.405 ;
     RECT  13.215 34.115 32.346 47.461 ;
     RECT  33.156 40.405 54.846 47.461 ;
     RECT  59.868 47.219 59.958 47.803 ;
     RECT  59.868 47.803 60.39 47.849 ;
     RECT  59.868 47.849 59.958 48.269 ;
     RECT  56.415 46.685 56.697 48.523 ;
     RECT  56.304 48.523 56.697 48.569 ;
     RECT  59.868 48.269 59.922 49.045 ;
     RECT  56.415 48.569 56.697 49.315 ;
     RECT  56.415 49.315 56.79 49.421 ;
     RECT  59.868 49.045 59.958 49.709 ;
     RECT  4.572 46.769 9.666 50.827 ;
     RECT  10.548 41.009 10.566 50.827 ;
     RECT  4.572 50.827 10.566 50.971 ;
     RECT  59.868 49.709 59.922 50.971 ;
     RECT  4.392 50.971 10.566 51.395 ;
     RECT  11.52 40.703 11.682 51.403 ;
     RECT  59.868 50.971 60.39 51.665 ;
     RECT  13.215 47.461 54.846 51.809 ;
     RECT  59.868 51.665 59.994 52.013 ;
     RECT  4.392 51.395 9.846 52.249 ;
     RECT  10.584 51.439 10.602 52.249 ;
     RECT  59.868 52.013 59.958 52.301 ;
     RECT  59.94 52.301 59.958 52.445 ;
     RECT  11.484 51.403 11.682 53.941 ;
     RECT  4.392 52.249 10.602 54.211 ;
     RECT  11.34 53.941 11.682 54.211 ;
     RECT  4.392 54.211 11.682 54.337 ;
     RECT  13.215 51.809 32.346 54.481 ;
     RECT  4.392 54.337 11.97 54.571 ;
     RECT  13.14 54.481 32.346 54.571 ;
     RECT  33.156 51.809 54.846 54.985 ;
     RECT  33.156 54.985 55.098 55.589 ;
     RECT  56.415 49.421 56.697 55.831 ;
     RECT  4.392 54.571 32.346 55.993 ;
     RECT  33.156 55.589 51.297 55.993 ;
     RECT  4.392 55.993 51.297 56.065 ;
     RECT  4.068 56.065 51.297 56.263 ;
     RECT  3.708 56.263 51.297 56.335 ;
     RECT  3.528 56.335 51.297 56.731 ;
     RECT  52.02 55.589 55.098 56.731 ;
     RECT  56.16 55.831 56.697 56.759 ;
     RECT  3.456 56.731 55.098 56.911 ;
     RECT  3.456 56.911 55.386 57.029 ;
     RECT  52.524 57.029 55.386 57.209 ;
     RECT  3.456 57.029 51.714 57.299 ;
     RECT  52.632 57.209 55.386 57.299 ;
     RECT  3.456 57.299 51.354 57.479 ;
     RECT  52.848 57.299 55.386 57.569 ;
     RECT  3.456 57.479 51.297 57.685 ;
     RECT  2.415 26.249 2.697 58.067 ;
     RECT  3.42 57.685 51.297 58.067 ;
     RECT  56.415 56.759 56.697 58.067 ;
     RECT  3.42 58.067 51.105 58.109 ;
     RECT  3.42 58.109 31.266 58.117 ;
     RECT  3.312 58.117 31.266 58.157 ;
     RECT  32.112 58.109 51.105 58.157 ;
     RECT  52.848 57.569 55.17 58.157 ;
     RECT  3.528 58.157 31.266 58.205 ;
     RECT  32.112 58.157 43.362 58.205 ;
     RECT  44.244 58.157 49.338 58.205 ;
     RECT  50.112 58.157 51.105 58.205 ;
     RECT  4.068 58.205 11.142 58.253 ;
     RECT  18.36 58.205 20.466 58.253 ;
     RECT  21.384 58.205 26.442 58.253 ;
     RECT  28.836 58.205 30.582 58.253 ;
     RECT  32.112 58.205 41.202 58.253 ;
     RECT  44.244 58.205 44.262 58.253 ;
     RECT  45.432 58.205 47.142 58.253 ;
     RECT  48.204 58.205 48.978 58.253 ;
     RECT  52.848 58.157 54.918 58.253 ;
     RECT  6.84 58.253 8.694 58.301 ;
     RECT  9.864 58.253 9.882 58.301 ;
     RECT  12.024 58.205 14.85 58.301 ;
     RECT  16.452 58.205 17.118 58.301 ;
     RECT  18.36 58.253 19.35 58.301 ;
     RECT  20.448 58.253 20.466 58.301 ;
     RECT  28.836 58.253 29.574 58.301 ;
     RECT  30.564 58.253 30.582 58.301 ;
     RECT  33.228 58.253 41.202 58.301 ;
     RECT  42.192 58.205 43.362 58.301 ;
     RECT  45.432 58.253 46.674 58.301 ;
     RECT  50.112 58.205 50.13 58.301 ;
     RECT  2.415 58.067 2.505 58.337 ;
     RECT  51.015 58.205 51.105 58.337 ;
     RECT  56.415 58.067 56.505 58.337 ;
     RECT  27.252 58.205 28.026 58.349 ;
     RECT  14.832 58.301 14.85 58.397 ;
     RECT  29.376 58.301 29.574 58.445 ;
     RECT  12.024 58.301 13.626 58.493 ;
     RECT  29.556 58.445 29.574 58.493 ;
     RECT  18.36 58.301 18.774 58.637 ;
     RECT  52.848 58.253 54.27 58.637 ;
     RECT  4.572 58.253 6.102 58.685 ;
     RECT  7.488 58.301 8.694 58.685 ;
     RECT  12.024 58.493 13.554 58.685 ;
     RECT  17.1 58.301 17.118 58.685 ;
     RECT  21.384 58.253 24.822 58.685 ;
     RECT  27.576 58.349 28.026 58.685 ;
     RECT  32.112 58.253 32.13 58.685 ;
     RECT  33.228 58.301 40.986 58.685 ;
     RECT  42.732 58.301 43.362 58.685 ;
     RECT  45.432 58.301 46.062 58.685 ;
     RECT  53.604 58.637 54.27 58.685 ;
     RECT  39.888 58.685 39.906 58.733 ;
     RECT  53.604 58.685 53.622 59.261 ;
     RECT  13.536 58.685 13.554 59.309 ;
     RECT  26.136 58.253 26.442 59.309 ;
     RECT  38.088 58.685 38.106 59.309 ;
     RECT  42.732 58.685 42.75 59.309 ;
     RECT  45.432 58.685 45.45 59.309 ;
     RECT  48.888 58.253 48.906 59.309 ;
     RECT  7.704 58.685 8.442 59.885 ;
     RECT  12.456 58.685 12.474 59.885 ;
     RECT  18.756 58.637 18.774 59.885 ;
     RECT  24.408 58.685 24.426 59.885 ;
     RECT  26.172 59.309 26.442 59.885 ;
     RECT  36.468 58.685 36.486 59.885 ;
     RECT  52.848 58.637 52.866 59.885 ;
     RECT  26.424 59.885 26.442 60.365 ;
    LAYER M4 ;
     RECT  0.084 26.064 0.097 26.088 ;
     RECT  0.06 26.088 0.097 26.208 ;
     RECT  0.084 26.208 0.097 26.232 ;
     RECT  0.084 17.136 0.137 17.16 ;
     RECT  0.06 17.16 0.137 17.28 ;
     RECT  0.084 17.28 0.137 17.304 ;
     RECT  0.06 17.304 0.137 17.424 ;
     RECT  0.084 17.424 0.137 17.448 ;
     RECT  0.06 17.448 0.137 17.568 ;
     RECT  0.084 17.568 0.137 17.592 ;
     RECT  0.06 17.592 0.137 17.712 ;
     RECT  0.084 17.712 0.137 17.736 ;
     RECT  0.06 17.736 0.137 17.856 ;
     RECT  0.084 17.856 0.137 17.88 ;
     RECT  0.06 17.88 0.137 18 ;
     RECT  0.084 18 0.137 18.024 ;
     RECT  0.06 18.024 0.137 18.144 ;
     RECT  0.084 18.144 0.137 18.168 ;
     RECT  0.06 18.168 0.137 18.288 ;
     RECT  0.084 18.288 0.137 18.312 ;
     RECT  0.06 18.312 0.137 18.432 ;
     RECT  0.084 18.432 0.137 18.456 ;
     RECT  0.06 18.456 0.137 18.576 ;
     RECT  0.084 18.576 0.137 18.6 ;
     RECT  0.06 18.6 0.137 18.72 ;
     RECT  0.084 18.72 0.137 18.744 ;
     RECT  0.06 18.744 0.137 18.864 ;
     RECT  0.084 18.864 0.137 18.888 ;
     RECT  0.06 18.888 0.137 19.008 ;
     RECT  0.084 19.008 0.137 19.032 ;
     RECT  0.06 19.032 0.137 19.152 ;
     RECT  0.084 19.152 0.137 19.176 ;
     RECT  0.06 19.176 0.137 19.296 ;
     RECT  0.084 19.296 0.137 19.32 ;
     RECT  0.06 19.32 0.137 19.44 ;
     RECT  0.084 19.44 0.137 19.464 ;
     RECT  0.06 19.464 0.137 19.584 ;
     RECT  0.084 19.584 0.137 19.608 ;
     RECT  0.06 19.608 0.137 19.728 ;
     RECT  0.084 19.728 0.137 19.752 ;
     RECT  0.06 19.752 0.137 19.872 ;
     RECT  0.084 19.872 0.137 19.896 ;
     RECT  0.06 19.896 0.137 20.016 ;
     RECT  0.084 20.016 0.137 20.04 ;
     RECT  0.06 20.04 0.137 20.16 ;
     RECT  0.084 20.16 0.137 20.184 ;
     RECT  0.06 20.184 0.137 20.304 ;
     RECT  0.084 20.304 0.137 20.328 ;
     RECT  0.06 20.328 0.137 20.448 ;
     RECT  0.084 20.448 0.137 20.472 ;
     RECT  0.06 20.472 0.137 20.592 ;
     RECT  0.084 20.592 0.137 20.616 ;
     RECT  0.06 20.616 0.137 20.736 ;
     RECT  0.084 20.736 0.137 20.76 ;
     RECT  0.06 20.76 0.137 20.88 ;
     RECT  0.084 20.88 0.137 20.904 ;
     RECT  0.06 20.904 0.137 21.024 ;
     RECT  0.084 21.024 0.137 21.048 ;
     RECT  0.06 21.048 0.137 21.168 ;
     RECT  0.084 21.168 0.137 21.192 ;
     RECT  0.06 21.192 0.137 21.312 ;
     RECT  0.084 21.312 0.137 21.336 ;
     RECT  0.06 21.336 0.137 21.456 ;
     RECT  0.084 21.456 0.137 21.48 ;
     RECT  0.06 21.48 0.137 21.6 ;
     RECT  0.084 21.6 0.137 21.624 ;
     RECT  0.137 17.28 0.569 21.624 ;
     RECT  0.569 17.568 2.408 21.624 ;
     RECT  0.097 26.064 2.408 26.328 ;
     RECT  2.408 2.148 2.512 58.332 ;
     RECT  2.512 2.418 2.704 58.152 ;
     RECT  2.704 26.064 3.269 26.328 ;
     RECT  2.704 58.128 3.49 58.152 ;
     RECT  2.704 17.088 3.733 20.328 ;
     RECT  3.733 17.088 3.841 20.472 ;
     RECT  2.704 21.936 3.841 22.056 ;
     RECT  2.704 15.312 4.025 15.624 ;
     RECT  3.49 58.128 4.057 58.2 ;
     RECT  3.841 17.088 4.172 22.056 ;
     RECT  4.172 16.512 4.489 22.056 ;
     RECT  4.057 58.128 4.561 58.248 ;
     RECT  4.489 16.512 4.817 22.344 ;
     RECT  4.025 15.312 5.065 15.336 ;
     RECT  4.817 16.512 5.065 22.296 ;
     RECT  5.065 3.168 5.137 3.192 ;
     RECT  5.137 2.88 5.537 3.192 ;
     RECT  4.993 56.496 5.605 56.52 ;
     RECT  4.993 4.8 5.641 4.824 ;
     RECT  5.137 0.096 5.65 0.12 ;
     RECT  4.993 1.104 5.65 1.128 ;
     RECT  5.605 56.4 5.753 56.52 ;
     RECT  5.065 15.312 5.893 22.296 ;
     RECT  5.641 3.936 5.897 4.824 ;
     RECT  5.65 0.096 5.977 1.128 ;
     RECT  5.893 15.312 5.996 22.344 ;
     RECT  5.996 14.544 6.077 22.344 ;
     RECT  6.077 14.544 6.083 14.568 ;
     RECT  6.077 16.224 6.083 22.344 ;
     RECT  6.083 18.432 6.109 22.344 ;
     RECT  4.525 23.424 6.109 23.448 ;
     RECT  6.083 16.224 6.185 17.256 ;
     RECT  4.561 58.128 6.227 58.68 ;
     RECT  5.965 2.256 6.275 2.856 ;
     RECT  3.269 26.304 6.469 26.328 ;
     RECT  6.275 2.736 6.509 2.856 ;
     RECT  6.109 18.432 6.515 23.448 ;
     RECT  6.325 1.152 6.545 1.176 ;
     RECT  6.515 22.032 6.613 23.448 ;
     RECT  6.613 22.032 6.649 23.592 ;
     RECT  6.649 22.032 6.689 23.928 ;
     RECT  6.649 5.664 6.797 5.688 ;
     RECT  6.689 23.568 6.901 23.928 ;
     RECT  6.469 26.208 6.901 26.328 ;
     RECT  7.189 7.632 7.225 7.656 ;
     RECT  5.977 0.096 7.405 0.168 ;
     RECT  6.217 55.248 7.429 55.272 ;
     RECT  5.753 56.496 7.429 56.52 ;
     RECT  6.185 16.32 7.441 17.256 ;
     RECT  6.515 18.432 7.441 20.472 ;
     RECT  7.333 5.712 7.477 5.736 ;
     RECT  7.225 6.816 7.477 7.656 ;
     RECT  6.227 58.128 7.477 58.296 ;
     RECT  7.117 14.784 7.573 14.808 ;
     RECT  7.441 16.32 7.573 20.472 ;
     RECT  6.509 2.736 7.657 2.808 ;
     RECT  5.897 4.128 7.657 4.152 ;
     RECT  7.657 2.736 7.693 4.152 ;
     RECT  7.669 60.288 7.693 60.312 ;
     RECT  7.405 0.096 7.733 0.6 ;
     RECT  6.749 1.728 7.808 1.752 ;
     RECT  7.693 2.736 7.808 4.2 ;
     RECT  7.477 5.712 7.808 7.656 ;
     RECT  7.669 13.344 7.808 13.368 ;
     RECT  7.573 14.4 7.808 20.472 ;
     RECT  6.689 22.032 7.808 22.536 ;
     RECT  6.901 23.568 7.808 24.504 ;
     RECT  6.901 25.68 7.808 26.328 ;
     RECT  6.469 30.336 7.808 30.36 ;
     RECT  7.429 55.248 7.808 56.52 ;
     RECT  7.477 58.128 7.808 58.68 ;
     RECT  7.693 59.856 7.811 60.312 ;
     RECT  7.808 1.728 8.104 58.68 ;
     RECT  8.104 21.648 8.165 22.536 ;
     RECT  8.104 26.304 8.165 26.76 ;
     RECT  8.104 8.448 8.237 8.472 ;
     RECT  8.104 13.584 8.243 16.584 ;
     RECT  8.104 3.936 8.633 6.312 ;
     RECT  8.165 21.648 8.633 21.672 ;
     RECT  8.104 57.936 8.669 58.68 ;
     RECT  7.811 59.856 8.675 59.88 ;
     RECT  7.733 0.144 8.765 0.6 ;
     RECT  8.104 50.592 8.777 51.912 ;
     RECT  8.765 0.096 8.813 0.6 ;
     RECT  8.633 3.936 8.813 5.736 ;
     RECT  8.104 17.952 8.813 19.272 ;
     RECT  8.104 20.4 8.813 20.472 ;
     RECT  8.813 0.096 8.849 0.12 ;
     RECT  8.777 50.688 8.867 51.912 ;
     RECT  8.243 13.584 8.921 15.48 ;
     RECT  8.813 17.952 8.921 18.984 ;
     RECT  8.669 58.128 8.963 58.68 ;
     RECT  8.867 50.688 9.059 51.768 ;
     RECT  8.921 13.584 9.097 13.992 ;
     RECT  8.921 18 9.137 18.984 ;
     RECT  8.243 16.56 9.148 16.584 ;
     RECT  8.813 20.4 9.173 20.424 ;
     RECT  9.097 12.528 9.203 13.992 ;
     RECT  9.059 50.928 9.209 51.768 ;
     RECT  9.203 13.584 9.245 13.992 ;
     RECT  8.921 15.456 9.245 15.48 ;
     RECT  9.209 50.928 9.281 51.144 ;
     RECT  9.137 18 9.317 18.456 ;
     RECT  8.104 9.792 9.389 9.816 ;
     RECT  8.165 26.688 9.395 26.76 ;
     RECT  9.205 38.976 9.395 39 ;
     RECT  8.104 1.728 9.457 2.808 ;
     RECT  8.813 3.936 9.457 5.16 ;
     RECT  9.457 1.728 9.461 5.16 ;
     RECT  9.281 50.928 9.569 50.952 ;
     RECT  8.104 55.776 9.596 56.52 ;
     RECT  9.245 13.968 9.605 13.992 ;
     RECT  8.963 58.128 9.637 58.296 ;
     RECT  9.596 55.152 9.683 56.52 ;
     RECT  9.203 12.528 9.785 12.552 ;
     RECT  9.461 1.728 9.884 4.536 ;
     RECT  9.637 57.552 9.893 58.296 ;
     RECT  9.884 1.68 9.971 4.536 ;
     RECT  9.971 1.728 10.001 4.536 ;
     RECT  10.001 4.128 10.181 4.344 ;
     RECT  9.683 55.776 10.433 55.8 ;
     RECT  9.421 39.36 10.465 39.72 ;
     RECT  10.316 0.528 10.501 0.552 ;
     RECT  10.465 39.36 10.681 40.008 ;
     RECT  9.853 54.576 10.685 54.6 ;
     RECT  10.001 1.728 10.757 2.76 ;
     RECT  10.181 4.128 10.793 4.152 ;
     RECT  10.501 0.528 11.077 0.6 ;
     RECT  10.757 1.728 11.077 2.616 ;
     RECT  10.681 39.36 11.153 40.104 ;
     RECT  11.077 0.528 11.261 2.616 ;
     RECT  11.261 0.528 11.411 0.552 ;
     RECT  10.825 55.824 11.437 55.848 ;
     RECT  11.153 39.36 11.513 39.72 ;
     RECT  11.513 39.36 11.729 39.528 ;
     RECT  11.437 4.608 11.797 4.632 ;
     RECT  11.797 4.608 11.869 5.16 ;
     RECT  10.753 6.144 11.869 6.168 ;
     RECT  11.261 1.728 11.909 2.616 ;
     RECT  11.185 54.72 11.989 54.744 ;
     RECT  11.437 55.824 11.989 56.184 ;
     RECT  9.893 57.552 12.013 58.248 ;
     RECT  11.909 1.776 12.025 2.616 ;
     RECT  11.869 4.608 12.085 6.168 ;
     RECT  11.989 54.72 12.089 56.184 ;
     RECT  12.025 2.592 12.188 2.616 ;
     RECT  12.085 4.56 12.517 6.168 ;
     RECT  12.517 0.096 12.661 0.12 ;
     RECT  12.661 0.096 12.665 0.168 ;
     RECT  12.445 59.856 12.707 59.88 ;
     RECT  12.517 4.56 13.093 6.36 ;
     RECT  12.949 1.152 13.165 1.176 ;
     RECT  12.188 2.592 13.165 3.432 ;
     RECT  13.165 1.152 13.208 3.432 ;
     RECT  13.093 4.56 13.208 7.08 ;
     RECT  9.317 18.432 13.208 18.456 ;
     RECT  9.395 26.736 13.208 26.76 ;
     RECT  8.104 30.336 13.208 30.36 ;
     RECT  11.729 39.504 13.208 39.528 ;
     RECT  12.089 55.296 13.208 56.184 ;
     RECT  12.013 57.552 13.208 58.68 ;
     RECT  13.208 1.152 13.504 58.68 ;
     RECT  13.504 57.408 13.525 58.68 ;
     RECT  13.525 57.408 13.637 59.304 ;
     RECT  13.504 1.152 13.667 3.432 ;
     RECT  13.504 4.992 13.673 7.032 ;
     RECT  13.637 59.28 13.859 59.304 ;
     RECT  12.665 0.144 13.957 0.168 ;
     RECT  13.957 0.144 14.237 0.6 ;
     RECT  13.673 4.992 14.285 6.936 ;
     RECT  14.237 0.096 14.321 0.6 ;
     RECT  14.285 4.992 14.677 6.84 ;
     RECT  13.667 1.728 14.821 3.432 ;
     RECT  13.637 57.552 14.821 58.296 ;
     RECT  14.677 4.56 14.825 6.84 ;
     RECT  14.821 1.056 14.897 3.432 ;
     RECT  14.825 4.896 14.897 6.84 ;
     RECT  14.821 57.552 14.905 58.392 ;
     RECT  13.504 55.68 15.113 55.704 ;
     RECT  14.897 1.056 15.185 2.616 ;
     RECT  15.185 1.056 15.293 1.224 ;
     RECT  15.293 1.056 15.299 1.176 ;
     RECT  13.504 39.504 15.469 39.528 ;
     RECT  15.299 1.152 15.587 1.176 ;
     RECT  15.397 0.096 15.761 0.168 ;
     RECT  15.469 39.504 15.793 39.576 ;
     RECT  15.185 2.256 16.117 2.616 ;
     RECT  15.793 39.504 16.157 39.768 ;
     RECT  14.905 57.552 16.405 58.2 ;
     RECT  14.897 4.896 16.513 6.216 ;
     RECT  16.117 2.256 16.549 3.432 ;
     RECT  16.513 4.896 16.697 6.936 ;
     RECT  16.405 57.552 17.089 58.296 ;
     RECT  17.089 7.92 17.201 7.944 ;
     RECT  17.089 57.552 17.233 58.68 ;
     RECT  17.233 57.408 17.315 58.68 ;
     RECT  16.697 5.04 17.345 6.936 ;
     RECT  17.341 15.792 17.521 15.816 ;
     RECT  16.549 1.728 17.845 3.432 ;
     RECT  18.061 17.136 18.133 17.16 ;
     RECT  13.504 18.432 18.133 18.456 ;
     RECT  17.845 1.152 18.173 3.432 ;
     RECT  13.504 26.736 18.277 26.76 ;
     RECT  18.097 31.344 18.277 31.368 ;
     RECT  17.315 57.408 18.349 58.2 ;
     RECT  15.761 0.096 18.373 0.12 ;
     RECT  18.133 17.136 18.385 18.456 ;
     RECT  18.349 57.408 18.433 58.632 ;
     RECT  18.373 60.288 18.469 60.312 ;
     RECT  18.173 1.728 18.608 3.432 ;
     RECT  17.345 5.04 18.608 6.168 ;
     RECT  17.521 14.928 18.608 15.816 ;
     RECT  18.385 17.136 18.608 19.368 ;
     RECT  18.277 26.208 18.608 26.76 ;
     RECT  13.504 30.336 18.608 30.36 ;
     RECT  18.277 31.344 18.608 31.416 ;
     RECT  16.157 39.504 18.608 39.528 ;
     RECT  18.469 51.936 18.608 51.96 ;
     RECT  18.469 55.392 18.608 55.416 ;
     RECT  18.433 57.408 18.608 58.44 ;
     RECT  18.469 60.24 18.611 60.312 ;
     RECT  18.611 60.24 18.745 60.264 ;
     RECT  18.745 59.856 18.755 60.264 ;
     RECT  18.608 1.728 18.785 58.44 ;
     RECT  18.755 59.856 18.899 59.88 ;
     RECT  18.785 1.728 18.904 58.296 ;
     RECT  18.904 39.504 19.001 39.816 ;
     RECT  18.904 56.064 19.001 56.088 ;
     RECT  18.904 57.408 19.372 58.296 ;
     RECT  18.373 0.096 19.573 0.216 ;
     RECT  18.904 4.8 19.613 7.416 ;
     RECT  19.613 4.8 19.757 6.216 ;
     RECT  19.613 7.392 19.829 7.416 ;
     RECT  18.904 1.728 20.045 3.768 ;
     RECT  18.904 13.872 20.108 13.896 ;
     RECT  20.108 13.776 20.195 13.896 ;
     RECT  19.573 0.096 20.233 0.6 ;
     RECT  18.904 17.184 20.329 19.368 ;
     RECT  18.904 15.312 20.365 15.528 ;
     RECT  20.329 16.8 20.369 19.368 ;
     RECT  19.372 57.408 20.396 58.248 ;
     RECT  20.045 1.728 20.585 2.952 ;
     RECT  20.233 0.528 20.665 0.6 ;
     RECT  20.396 57.408 20.675 58.296 ;
     RECT  20.365 15.312 20.693 15.768 ;
     RECT  20.629 54.864 20.716 55.416 ;
     RECT  20.693 15.504 20.797 15.768 ;
     RECT  20.369 16.8 20.797 17.496 ;
     RECT  20.797 15.504 20.801 17.496 ;
     RECT  19.757 5.136 20.941 6.216 ;
     RECT  20.941 4.512 21.049 6.216 ;
     RECT  18.904 51.936 21.233 51.96 ;
     RECT  20.675 58.128 21.301 58.296 ;
     RECT  21.049 4.512 21.517 6.984 ;
     RECT  21.437 0.096 21.521 0.12 ;
     RECT  19.001 39.504 21.697 39.528 ;
     RECT  20.801 16.08 21.733 17.496 ;
     RECT  20.369 19.344 21.779 19.368 ;
     RECT  21.697 39.504 21.805 39.768 ;
     RECT  21.517 4.512 21.809 7.416 ;
     RECT  20.585 1.728 21.869 1.752 ;
     RECT  20.585 2.88 21.869 2.952 ;
     RECT  21.517 56.976 21.917 57 ;
     RECT  21.733 16.08 21.989 18.216 ;
     RECT  21.809 4.992 22.061 7.416 ;
     RECT  22.061 4.992 22.205 6.888 ;
     RECT  22.205 4.992 22.313 6.84 ;
     RECT  20.716 54.864 22.364 54.888 ;
     RECT  22.313 4.992 22.385 5.16 ;
     RECT  22.364 54.576 22.405 54.888 ;
     RECT  22.405 54.576 22.451 55.32 ;
     RECT  22.373 52.992 22.457 53.016 ;
     RECT  22.013 0.576 22.7 0.6 ;
     RECT  21.869 1.728 22.7 2.952 ;
     RECT  22.385 4.992 22.781 5.064 ;
     RECT  21.989 16.08 22.781 18.024 ;
     RECT  22.7 0.576 22.787 2.952 ;
     RECT  22.787 0.576 22.885 0.6 ;
     RECT  21.805 39.504 22.885 39.96 ;
     RECT  22.787 1.728 22.933 2.952 ;
     RECT  20.195 13.872 22.988 13.896 ;
     RECT  20.149 12.768 23.029 12.792 ;
     RECT  22.988 13.872 23.029 14.904 ;
     RECT  22.313 6.144 23.237 6.84 ;
     RECT  23.029 12.768 23.389 14.904 ;
     RECT  23.389 12.768 23.42 15.48 ;
     RECT  22.933 1.728 23.605 3.048 ;
     RECT  22.781 5.04 23.749 5.064 ;
     RECT  23.605 1.728 23.785 3.384 ;
     RECT  23.749 5.04 23.821 5.16 ;
     RECT  23.237 6.144 23.821 6.888 ;
     RECT  23.785 1.728 24.008 3.96 ;
     RECT  23.821 5.04 24.008 6.888 ;
     RECT  23.42 12.528 24.008 15.48 ;
     RECT  22.781 16.464 24.008 18.024 ;
     RECT  18.904 30.336 24.008 30.36 ;
     RECT  18.904 31.392 24.008 31.416 ;
     RECT  22.885 39.504 24.008 40.392 ;
     RECT  23.137 51.6 24.008 51.624 ;
     RECT  22.451 54.864 24.008 55.32 ;
     RECT  21.301 58.128 24.008 58.68 ;
     RECT  22.885 0.096 24.185 0.6 ;
     RECT  24.008 1.728 24.304 58.68 ;
     RECT  24.304 1.728 24.437 3.432 ;
     RECT  24.185 0.096 24.473 0.36 ;
     RECT  24.304 10.8 24.508 18.024 ;
     RECT  24.304 57.024 24.509 58.68 ;
     RECT  24.473 0.096 24.515 0.264 ;
     RECT  24.508 12.288 24.545 18.024 ;
     RECT  24.397 59.856 24.659 59.88 ;
     RECT  24.304 4.848 24.941 6.072 ;
     RECT  24.509 58.128 24.947 58.68 ;
     RECT  24.304 31.392 25.139 31.608 ;
     RECT  24.304 38.544 25.187 39.624 ;
     RECT  24.941 6.048 25.333 6.072 ;
     RECT  24.304 33.504 25.337 33.528 ;
     RECT  24.545 13.872 25.379 18.024 ;
     RECT  25.333 6.048 25.477 6.312 ;
     RECT  24.304 49.008 25.477 51.336 ;
     RECT  25.477 49.008 25.523 52.008 ;
     RECT  24.545 12.288 25.545 12.792 ;
     RECT  25.379 14.928 25.571 18.024 ;
     RECT  24.304 36.144 25.621 36.168 ;
     RECT  25.513 37.632 25.621 37.656 ;
     RECT  24.304 47.856 25.621 47.88 ;
     RECT  25.523 51.312 25.625 52.008 ;
     RECT  25.297 35.04 25.667 35.064 ;
     RECT  25.621 36.144 25.667 37.656 ;
     RECT  25.523 49.008 25.733 50.232 ;
     RECT  24.941 4.848 25.769 4.872 ;
     RECT  25.571 15.024 25.769 18.024 ;
     RECT  24.437 1.728 25.873 3.384 ;
     RECT  24.947 58.128 25.955 58.248 ;
     RECT  25.477 6.048 25.981 6.552 ;
     RECT  25.873 1.728 26.012 3.432 ;
     RECT  24.508 10.8 26.089 10.824 ;
     RECT  25.545 12.288 26.089 12.552 ;
     RECT  25.379 13.872 26.089 13.896 ;
     RECT  25.187 39.408 26.129 39.528 ;
     RECT  26.125 59.28 26.161 59.304 ;
     RECT  26.012 1.104 26.197 3.432 ;
     RECT  26.161 59.28 26.243 59.88 ;
     RECT  26.089 10.8 26.245 12.552 ;
     RECT  26.245 10.08 26.291 12.552 ;
     RECT  24.304 54.864 26.309 55.56 ;
     RECT  26.291 10.08 26.332 10.344 ;
     RECT  26.243 59.856 26.341 59.88 ;
     RECT  26.197 0.576 26.345 3.432 ;
     RECT  26.309 54.864 26.381 55.512 ;
     RECT  25.667 36.144 26.453 36.696 ;
     RECT  26.341 59.856 26.453 60.36 ;
     RECT  25.801 56.976 26.525 57 ;
     RECT  26.453 59.856 26.531 59.88 ;
     RECT  26.345 1.104 26.561 3.432 ;
     RECT  26.381 54.864 26.819 54.984 ;
     RECT  25.733 49.728 26.821 50.232 ;
     RECT  26.561 1.104 26.857 3.048 ;
     RECT  25.621 47.856 26.881 47.976 ;
     RECT  26.821 49.008 26.881 50.232 ;
     RECT  25.955 58.128 26.917 58.152 ;
     RECT  26.917 58.128 27.061 58.2 ;
     RECT  25.625 51.984 27.097 52.008 ;
     RECT  26.881 47.856 27.133 50.232 ;
     RECT  25.981 5.376 27.169 6.552 ;
     RECT  27.061 58.128 27.205 58.248 ;
     RECT  27.205 58.128 27.212 58.344 ;
     RECT  27.133 47.76 27.245 50.232 ;
     RECT  27.169 4.608 27.281 6.552 ;
     RECT  27.245 47.76 27.281 50.136 ;
     RECT  26.819 54.96 27.299 54.984 ;
     RECT  27.212 57.456 27.299 58.344 ;
     RECT  25.769 15.504 27.421 18.024 ;
     RECT  26.089 13.68 27.493 13.896 ;
     RECT  27.421 14.976 27.493 18.024 ;
     RECT  27.493 13.68 27.533 18.024 ;
     RECT  27.299 57.888 27.565 58.344 ;
     RECT  26.129 39.456 27.677 39.528 ;
     RECT  27.281 47.904 27.713 50.136 ;
     RECT  26.857 1.728 27.745 3.048 ;
     RECT  26.557 35.952 27.889 35.976 ;
     RECT  26.291 11.328 27.929 12.552 ;
     RECT  27.889 35.952 27.929 36.072 ;
     RECT  26.332 10.32 28.033 10.344 ;
     RECT  27.925 0.096 28.069 0.12 ;
     RECT  27.929 12.528 28.109 12.552 ;
     RECT  27.565 57.888 28.115 58.68 ;
     RECT  28.069 0.096 28.145 0.168 ;
     RECT  28.145 0.144 28.217 0.168 ;
     RECT  24.304 30.336 28.309 30.36 ;
     RECT  25.139 31.584 28.321 31.608 ;
     RECT  28.321 31.488 28.355 31.608 ;
     RECT  27.713 47.904 28.357 50.04 ;
     RECT  28.309 30.192 28.396 30.36 ;
     RECT  28.033 10.32 28.468 11.016 ;
     RECT  27.745 1.728 28.609 3.432 ;
     RECT  27.281 4.608 28.609 5.736 ;
     RECT  28.396 30.336 28.693 30.36 ;
     RECT  28.355 31.488 28.693 31.512 ;
     RECT  28.357 47.856 28.717 50.04 ;
     RECT  27.097 51.744 28.717 52.008 ;
     RECT  28.609 1.728 28.748 5.736 ;
     RECT  28.748 1.728 28.901 6.696 ;
     RECT  28.717 51.456 28.969 52.008 ;
     RECT  28.115 57.888 29.173 58.296 ;
     RECT  28.717 47.616 29.269 50.04 ;
     RECT  28.901 1.776 29.408 6.696 ;
     RECT  28.468 10.272 29.408 11.016 ;
     RECT  27.533 13.872 29.408 18.024 ;
     RECT  28.997 28.512 29.408 28.536 ;
     RECT  28.693 30.336 29.408 31.512 ;
     RECT  27.929 36.048 29.408 36.072 ;
     RECT  27.205 38.208 29.408 38.232 ;
     RECT  27.677 39.504 29.408 39.528 ;
     RECT  29.221 46.56 29.408 46.584 ;
     RECT  29.269 47.616 29.408 50.328 ;
     RECT  28.969 51.36 29.408 52.008 ;
     RECT  28.789 56.592 29.408 56.616 ;
     RECT  29.173 57.888 29.408 58.44 ;
     RECT  29.408 1.776 29.509 58.44 ;
     RECT  29.509 1.776 29.596 58.488 ;
     RECT  29.596 1.776 29.657 58.296 ;
     RECT  29.657 2.418 29.704 58.296 ;
     RECT  29.704 30.72 29.765 34.104 ;
     RECT  29.704 47.616 29.765 49.032 ;
     RECT  29.704 9.792 29.891 10.872 ;
     RECT  29.173 60.288 29.891 60.312 ;
     RECT  29.765 31.488 29.981 34.104 ;
     RECT  29.981 32.448 29.987 34.104 ;
     RECT  29.704 36.048 29.987 36.072 ;
     RECT  29.704 3.024 30.053 3.384 ;
     RECT  29.765 47.616 30.089 48.696 ;
     RECT  30.053 3.024 30.125 3.336 ;
     RECT  30.089 47.664 30.227 48.696 ;
     RECT  29.704 56.592 30.521 56.616 ;
     RECT  29.704 50.304 30.563 52.104 ;
     RECT  29.704 57.6 30.604 58.296 ;
     RECT  29.704 55.536 30.621 55.56 ;
     RECT  30.563 50.304 30.629 51.768 ;
     RECT  29.704 12.576 30.733 12.6 ;
     RECT  30.227 47.712 30.733 48.696 ;
     RECT  29.704 38.208 30.769 38.232 ;
     RECT  30.769 38.208 30.809 38.424 ;
     RECT  29.987 33.936 30.881 34.104 ;
     RECT  29.891 9.792 31.021 10.152 ;
     RECT  30.769 30.72 31.021 31.368 ;
     RECT  30.997 32.88 31.021 32.904 ;
     RECT  31.021 30.72 31.061 32.904 ;
     RECT  31.061 31.92 31.084 32.904 ;
     RECT  31.021 9.744 31.165 10.152 ;
     RECT  29.704 46.56 31.333 46.584 ;
     RECT  30.733 47.712 31.333 49.08 ;
     RECT  31.129 50.112 31.333 50.136 ;
     RECT  31.084 31.92 31.457 32.184 ;
     RECT  31.333 46.56 31.493 50.136 ;
     RECT  30.881 33.936 31.705 33.96 ;
     RECT  31.493 47.76 31.741 50.136 ;
     RECT  30.629 51.12 31.741 51.768 ;
     RECT  30.604 57.6 31.745 58.2 ;
     RECT  31.309 30 31.921 30.648 ;
     RECT  31.741 47.76 31.925 51.768 ;
     RECT  31.925 47.76 31.961 50.136 ;
     RECT  31.165 9.744 32.101 10.2 ;
     RECT  31.745 58.128 32.101 58.2 ;
     RECT  32.101 9.744 32.137 10.584 ;
     RECT  31.961 50.112 32.141 50.136 ;
     RECT  31.457 32.16 32.209 32.184 ;
     RECT  31.705 33.552 32.209 33.96 ;
     RECT  31.921 29.76 32.389 30.648 ;
     RECT  32.437 7.968 32.523 7.992 ;
     RECT  32.523 7.968 32.524 8.04 ;
     RECT  32.437 5.184 32.533 5.208 ;
     RECT  31.961 47.76 32.609 48.552 ;
     RECT  32.137 9.744 32.753 10.968 ;
     RECT  32.209 32.16 32.78 33.96 ;
     RECT  32.524 8.016 32.785 8.04 ;
     RECT  29.704 39.504 32.821 39.528 ;
     RECT  32.785 8.016 32.825 8.52 ;
     RECT  31.925 51.168 32.825 51.768 ;
     RECT  32.78 31.824 32.867 33.96 ;
     RECT  32.825 51.168 32.893 51.192 ;
     RECT  32.389 29.76 32.933 30.84 ;
     RECT  32.867 32.16 32.933 33.96 ;
     RECT  30.125 3.024 32.993 3.048 ;
     RECT  32.533 4.512 32.993 5.208 ;
     RECT  32.825 8.496 33.059 8.52 ;
     RECT  32.933 33.024 33.073 33.96 ;
     RECT  32.993 3.024 33.437 5.208 ;
     RECT  32.753 9.744 33.617 10.584 ;
     RECT  32.821 39.408 33.973 39.528 ;
     RECT  33.073 33.024 34.009 34.104 ;
     RECT  30.809 38.4 34.009 38.424 ;
     RECT  33.437 5.184 34.261 5.208 ;
     RECT  34.009 38.208 34.261 38.424 ;
     RECT  33.973 39.408 34.261 39.576 ;
     RECT  34.261 38.208 34.316 39.576 ;
     RECT  34.261 1.728 34.364 1.752 ;
     RECT  34.297 31.68 34.585 31.704 ;
     RECT  34.357 42.72 34.655 42.744 ;
     RECT  34.081 0.096 34.765 0.12 ;
     RECT  34.364 1.104 34.765 1.752 ;
     RECT  34.765 0.096 34.808 1.752 ;
     RECT  33.437 3.024 34.808 3.768 ;
     RECT  34.261 5.184 34.808 5.784 ;
     RECT  33.617 10.032 34.808 10.584 ;
     RECT  30.733 12.576 34.808 13.08 ;
     RECT  29.704 14.976 34.808 18.024 ;
     RECT  32.933 29.76 34.808 30.648 ;
     RECT  34.585 31.68 34.808 31.8 ;
     RECT  34.009 32.832 34.808 34.104 ;
     RECT  34.316 38.208 34.808 39.912 ;
     RECT  34.655 42.72 34.808 43.032 ;
     RECT  31.493 46.56 34.808 46.584 ;
     RECT  32.609 48.528 34.808 48.552 ;
     RECT  32.893 50.4 34.808 51.192 ;
     RECT  33.505 55.824 34.808 55.848 ;
     RECT  32.101 58.128 34.808 58.68 ;
     RECT  34.808 0.096 35.104 58.68 ;
     RECT  35.104 0.096 35.267 5.88 ;
     RECT  35.104 44.736 35.411 46.776 ;
     RECT  35.267 4.512 35.453 5.88 ;
     RECT  35.267 0.096 35.669 3.432 ;
     RECT  35.669 0.096 35.893 1.848 ;
     RECT  35.104 29.76 36.241 31.8 ;
     RECT  35.104 32.832 36.241 32.856 ;
     RECT  35.893 0.096 36.317 1.752 ;
     RECT  35.104 38.208 36.461 39.528 ;
     RECT  35.669 2.88 36.493 3.432 ;
     RECT  35.453 4.512 36.493 5.832 ;
     RECT  35.104 43.008 36.601 43.032 ;
     RECT  36.601 43.008 36.641 43.368 ;
     RECT  35.411 45.216 36.745 45.336 ;
     RECT  35.411 46.56 36.745 46.776 ;
     RECT  36.745 45.216 36.785 46.776 ;
     RECT  36.317 1.104 36.857 1.752 ;
     RECT  36.457 59.856 36.899 59.88 ;
     RECT  36.493 2.88 36.997 5.832 ;
     RECT  36.997 2.88 37.009 6.072 ;
     RECT  36.785 45.216 37.141 46.584 ;
     RECT  36.857 1.104 37.187 1.128 ;
     RECT  37.009 2.88 37.357 3.096 ;
     RECT  37.009 4.512 37.541 6.072 ;
     RECT  37.357 2.208 37.619 3.096 ;
     RECT  36.317 0.096 37.717 0.12 ;
     RECT  35.104 14.976 37.717 18.024 ;
     RECT  37.541 4.608 37.793 6.072 ;
     RECT  37.141 44.4 37.825 46.584 ;
     RECT  35.104 12.576 37.861 13.08 ;
     RECT  37.717 14.784 37.861 18.024 ;
     RECT  36.641 43.344 37.861 43.368 ;
     RECT  37.825 44.4 37.861 46.728 ;
     RECT  37.861 43.344 37.865 46.728 ;
     RECT  37.619 3.024 37.937 3.096 ;
     RECT  37.793 4.848 38.005 6.072 ;
     RECT  37.865 46.56 38.041 46.728 ;
     RECT  35.104 58.128 38.077 58.68 ;
     RECT  38.041 46.56 38.113 47.4 ;
     RECT  35.104 55.44 38.113 55.464 ;
     RECT  38.113 46.56 38.221 47.448 ;
     RECT  35.104 48.528 38.221 48.552 ;
     RECT  38.077 58.128 38.339 59.304 ;
     RECT  38.005 4.848 38.369 6.264 ;
     RECT  37.937 3.072 38.513 3.096 ;
     RECT  37.717 0.096 38.549 0.6 ;
     RECT  38.549 0.096 38.665 0.12 ;
     RECT  37.861 12.576 38.869 18.024 ;
     RECT  37.865 43.344 38.873 45.528 ;
     RECT  35.104 10.176 38.909 10.2 ;
     RECT  38.369 4.848 38.915 5.832 ;
     RECT  38.869 12.528 38.953 18.024 ;
     RECT  38.005 1.728 39.013 1.752 ;
     RECT  39.013 56.976 39.121 57 ;
     RECT  38.915 5.184 39.197 5.832 ;
     RECT  38.953 12.576 39.233 18.024 ;
     RECT  36.461 38.208 39.349 38.232 ;
     RECT  39.013 1.728 39.404 2.328 ;
     RECT  39.404 1.104 39.491 2.328 ;
     RECT  39.121 56.976 39.541 57.096 ;
     RECT  38.339 58.128 39.541 58.68 ;
     RECT  39.491 1.632 39.733 2.328 ;
     RECT  39.541 56.976 39.836 58.68 ;
     RECT  39.733 1.632 39.841 2.904 ;
     RECT  39.836 56.976 39.923 58.728 ;
     RECT  39.841 1.632 39.941 3 ;
     RECT  38.113 55.44 40.069 55.992 ;
     RECT  39.923 56.976 40.069 58.68 ;
     RECT  39.941 1.632 40.165 3.24 ;
     RECT  40.165 1.632 40.208 3.96 ;
     RECT  39.197 5.184 40.208 5.208 ;
     RECT  39.233 12.576 40.208 13.608 ;
     RECT  39.233 14.976 40.208 18.024 ;
     RECT  40.069 24.912 40.208 24.936 ;
     RECT  36.241 29.76 40.208 32.856 ;
     RECT  39.349 37.392 40.208 38.232 ;
     RECT  36.461 39.456 40.208 39.528 ;
     RECT  38.873 43.392 40.208 45.528 ;
     RECT  38.221 46.56 40.208 48.552 ;
     RECT  35.104 50.4 40.208 51.192 ;
     RECT  40.069 55.44 40.208 58.68 ;
     RECT  40.208 1.632 40.504 58.68 ;
     RECT  40.504 23.328 40.643 24.936 ;
     RECT  40.504 3.936 40.673 3.96 ;
     RECT  40.453 0.144 40.691 0.168 ;
     RECT  40.504 57.936 40.745 58.68 ;
     RECT  40.504 1.632 40.997 2.904 ;
     RECT  40.745 58.128 40.997 58.68 ;
     RECT  40.997 2.16 41.213 2.904 ;
     RECT  41.132 0.576 41.219 1.128 ;
     RECT  40.504 4.992 41.393 6.312 ;
     RECT  40.504 43.392 41.501 48.552 ;
     RECT  40.504 55.104 41.507 55.992 ;
     RECT  41.213 2.16 41.545 2.328 ;
     RECT  41.219 0.576 41.753 0.6 ;
     RECT  40.643 24.624 41.785 24.936 ;
     RECT  41.641 3.408 41.795 3.432 ;
     RECT  40.504 53.664 41.797 53.688 ;
     RECT  41.797 53.52 41.821 53.688 ;
     RECT  41.501 46.608 41.891 48.552 ;
     RECT  40.504 12.576 41.893 13.704 ;
     RECT  41.821 53.04 41.905 53.688 ;
     RECT  41.891 47.328 41.987 48.552 ;
     RECT  41.905 53.664 41.987 53.688 ;
     RECT  41.507 55.392 42.133 55.992 ;
     RECT  41.893 12.576 42.145 13.848 ;
     RECT  40.504 14.976 42.145 18.024 ;
     RECT  41.785 24.624 42.173 25.464 ;
     RECT  42.173 23.904 42.227 25.464 ;
     RECT  40.997 58.128 42.227 58.296 ;
     RECT  42.227 23.904 42.257 23.928 ;
     RECT  41.987 47.328 42.257 47.448 ;
     RECT  42.253 27.216 42.289 27.24 ;
     RECT  41.545 2.16 42.293 2.28 ;
     RECT  42.227 58.128 42.325 58.248 ;
     RECT  42.257 47.424 42.401 47.448 ;
     RECT  42.227 24.912 42.433 25.464 ;
     RECT  41.501 43.392 42.685 45.528 ;
     RECT  41.393 5.136 42.697 5.496 ;
     RECT  42.696 59.28 42.805 59.304 ;
     RECT  42.697 5.472 42.901 5.496 ;
     RECT  42.145 12.576 42.997 18.024 ;
     RECT  42.433 24.912 43.196 26.232 ;
     RECT  42.997 12.576 43.237 18.84 ;
     RECT  42.289 27.216 43.237 27.384 ;
     RECT  43.237 12.576 43.283 19.272 ;
     RECT  42.325 1.728 43.333 1.752 ;
     RECT  43.117 2.736 43.333 2.76 ;
     RECT  42.325 57.552 43.333 58.248 ;
     RECT  43.196 24.816 43.337 26.232 ;
     RECT  43.333 57.552 43.417 58.68 ;
     RECT  42.433 3.984 43.517 4.008 ;
     RECT  42.397 23.616 43.549 23.64 ;
     RECT  43.337 24.816 43.549 25.512 ;
     RECT  42.901 5.472 43.58 5.736 ;
     RECT  43.513 6.768 43.58 6.792 ;
     RECT  42.469 0.096 43.697 0.12 ;
     RECT  43.333 1.728 43.769 2.76 ;
     RECT  43.549 23.616 43.769 25.512 ;
     RECT  42.133 55.392 43.801 56.232 ;
     RECT  43.769 23.616 43.868 24.504 ;
     RECT  40.504 29.76 43.873 32.856 ;
     RECT  43.729 33.984 43.873 34.008 ;
     RECT  43.237 27.216 43.909 27.96 ;
     RECT  43.868 23.328 43.955 24.504 ;
     RECT  43.417 57.552 44.093 58.248 ;
     RECT  44.093 58.128 44.284 58.248 ;
     RECT  43.873 29.76 44.449 34.008 ;
     RECT  43.58 5.472 44.485 6.792 ;
     RECT  43.909 26.88 44.673 27.96 ;
     RECT  44.449 29.76 44.677 34.152 ;
     RECT  44.629 0.576 44.765 0.6 ;
     RECT  44.485 5.472 44.78 6.984 ;
     RECT  44.765 0.096 44.813 0.6 ;
     RECT  44.78 4.944 44.845 6.984 ;
     RECT  44.813 0.096 45.137 0.168 ;
     RECT  44.521 35.664 45.157 35.688 ;
     RECT  44.845 4.944 45.457 7.224 ;
     RECT  43.801 55.296 45.565 56.232 ;
     RECT  43.769 1.728 45.608 2.28 ;
     RECT  45.457 4.176 45.608 7.224 ;
     RECT  43.283 12.576 45.608 18.024 ;
     RECT  43.283 19.248 45.608 19.272 ;
     RECT  43.955 23.616 45.608 24.504 ;
     RECT  43.769 25.488 45.608 25.512 ;
     RECT  44.673 26.64 45.608 27.96 ;
     RECT  44.677 29.76 45.608 34.344 ;
     RECT  45.157 35.664 45.608 35.976 ;
     RECT  40.504 37.296 45.608 38.232 ;
     RECT  40.504 39.504 45.608 39.528 ;
     RECT  42.685 43.392 45.608 45.816 ;
     RECT  41.987 48.528 45.608 48.552 ;
     RECT  40.504 50.4 45.608 51.192 ;
     RECT  45.565 55.248 45.608 56.232 ;
     RECT  44.284 58.128 45.608 58.2 ;
     RECT  45.421 59.28 45.608 59.304 ;
     RECT  45.608 1.728 45.683 59.304 ;
     RECT  45.137 0.144 45.781 0.168 ;
     RECT  45.683 1.728 45.904 58.68 ;
     RECT  45.781 0.144 45.925 0.216 ;
     RECT  45.904 3.312 46.019 6.6 ;
     RECT  45.925 0.144 46.073 0.264 ;
     RECT  45.904 58.128 46.117 58.68 ;
     RECT  46.073 0.144 46.163 0.216 ;
     RECT  45.904 1.728 46.172 2.28 ;
     RECT  46.019 3.312 46.181 6.072 ;
     RECT  45.904 55.248 46.181 56.232 ;
     RECT  46.172 1.68 46.259 2.28 ;
     RECT  45.904 29.76 46.289 38.232 ;
     RECT  46.289 35.568 46.613 38.232 ;
     RECT  45.904 26.88 46.691 28.104 ;
     RECT  46.117 58.128 46.691 58.296 ;
     RECT  46.181 3.312 46.721 5.784 ;
     RECT  45.904 25.632 46.721 25.656 ;
     RECT  46.721 3.408 46.757 5.784 ;
     RECT  46.289 29.76 46.901 34.248 ;
     RECT  46.691 26.88 46.969 27.48 ;
     RECT  46.757 3.408 47.045 5.736 ;
     RECT  46.613 36.336 47.153 38.232 ;
     RECT  47.045 4.272 47.297 5.736 ;
     RECT  47.297 4.272 47.315 5.496 ;
     RECT  47.153 36.912 47.329 38.232 ;
     RECT  45.904 39.504 47.329 39.528 ;
     RECT  46.969 26.256 47.333 27.48 ;
     RECT  47.333 26.256 47.369 27.336 ;
     RECT  45.904 23.328 47.477 24.504 ;
     RECT  46.259 2.208 47.509 2.28 ;
     RECT  46.181 56.208 47.545 56.232 ;
     RECT  47.509 1.728 47.689 2.28 ;
     RECT  47.689 1.728 47.725 3.048 ;
     RECT  46.789 0.096 47.729 0.12 ;
     RECT  45.904 19.248 47.833 19.272 ;
     RECT  47.725 1.104 48.017 3.048 ;
     RECT  47.833 19.056 48.121 19.272 ;
     RECT  46.901 33.84 48.121 34.248 ;
     RECT  47.477 23.424 48.125 24.504 ;
     RECT  45.904 12.576 48.193 18.024 ;
     RECT  48.121 19.056 48.193 19.32 ;
     RECT  47.315 4.512 48.197 5.496 ;
     RECT  48.125 23.424 48.233 23.64 ;
     RECT  48.017 2.208 48.269 3.048 ;
     RECT  48.017 1.104 48.275 1.128 ;
     RECT  48.197 4.848 48.373 5.496 ;
     RECT  48.193 12.576 48.409 19.32 ;
     RECT  47.545 55.44 48.449 56.232 ;
     RECT  48.373 4.848 48.485 5.736 ;
     RECT  48.121 33.84 48.557 35.592 ;
     RECT  48.517 0.576 48.769 0.6 ;
     RECT  47.369 26.736 48.949 27.336 ;
     RECT  46.691 58.128 48.995 58.248 ;
     RECT  48.449 56.208 48.997 56.232 ;
     RECT  48.995 58.128 48.997 58.2 ;
     RECT  48.949 26.352 49.021 27.336 ;
     RECT  48.997 56.208 49.043 56.52 ;
     RECT  48.485 4.848 49.061 5.592 ;
     RECT  48.557 35.568 49.061 35.592 ;
     RECT  48.269 2.688 49.237 3.048 ;
     RECT  47.329 36.912 49.241 39.528 ;
     RECT  48.877 59.28 49.283 59.304 ;
     RECT  48.409 12.576 49.349 19.944 ;
     RECT  49.241 36.912 49.489 36.936 ;
     RECT  49.237 2.304 49.561 3.048 ;
     RECT  49.489 36.864 49.561 36.936 ;
     RECT  48.769 0.096 49.565 0.6 ;
     RECT  49.565 0.096 49.573 0.168 ;
     RECT  49.021 26.304 49.673 27.336 ;
     RECT  49.241 38.208 49.813 39.528 ;
     RECT  49.673 26.304 49.925 27.144 ;
     RECT  49.925 26.304 49.997 27.096 ;
     RECT  49.573 0.096 50.033 0.12 ;
     RECT  48.997 58.08 50.06 58.2 ;
     RECT  49.993 55.488 50.137 55.512 ;
     RECT  49.043 56.496 50.137 56.52 ;
     RECT  50.06 58.08 50.137 58.296 ;
     RECT  48.557 33.84 50.149 34.152 ;
     RECT  49.993 35.376 50.149 35.4 ;
     RECT  49.061 4.848 50.353 5.16 ;
     RECT  49.561 1.68 50.389 3.048 ;
     RECT  50.389 1.152 50.461 3.048 ;
     RECT  49.349 12.576 50.497 19.656 ;
     RECT  49.429 21.12 50.497 21.144 ;
     RECT  48.233 23.616 50.641 23.64 ;
     RECT  50.461 1.152 50.821 3.432 ;
     RECT  50.497 12.576 50.821 21.144 ;
     RECT  50.641 22.752 50.821 23.64 ;
     RECT  50.353 4.848 50.893 5.256 ;
     RECT  50.821 0.576 50.969 3.432 ;
     RECT  50.969 1.104 51.008 3.432 ;
     RECT  50.893 4.512 51.008 5.256 ;
     RECT  50.821 12.576 51.008 23.64 ;
     RECT  49.997 26.352 51.008 27.096 ;
     RECT  46.901 29.76 51.008 32.856 ;
     RECT  50.149 33.84 51.008 35.4 ;
     RECT  49.561 36.576 51.008 36.936 ;
     RECT  49.813 38.208 51.008 40.104 ;
     RECT  45.904 43.392 51.008 45.816 ;
     RECT  45.904 48.528 51.008 48.552 ;
     RECT  45.904 50.4 51.008 51.192 ;
     RECT  50.137 55.488 51.008 58.296 ;
     RECT  51.008 1.104 51.011 58.332 ;
     RECT  51.011 1.728 51.112 58.332 ;
     RECT  51.112 1.728 51.304 58.062 ;
     RECT  51.304 2.88 51.437 4.536 ;
     RECT  51.304 20.592 51.473 21.144 ;
     RECT  51.304 1.728 52.405 1.896 ;
     RECT  51.437 2.88 52.405 3.912 ;
     RECT  51.304 43.392 52.441 45.816 ;
     RECT  52.405 1.728 52.481 3.912 ;
     RECT  51.304 5.712 52.517 5.736 ;
     RECT  51.304 23.616 52.585 23.64 ;
     RECT  51.304 22.224 52.739 22.248 ;
     RECT  52.481 1.776 52.841 3.912 ;
     RECT  51.473 21.12 53.129 21.144 ;
     RECT  53.125 19.632 53.197 19.656 ;
     RECT  52.841 2.208 53.273 3.912 ;
     RECT  52.837 59.856 53.315 59.88 ;
     RECT  53.273 2.208 53.417 2.232 ;
     RECT  51.304 27.072 53.485 27.096 ;
     RECT  53.372 58.128 53.485 58.152 ;
     RECT  53.485 27.024 53.521 27.096 ;
     RECT  53.485 58.128 53.549 58.632 ;
     RECT  53.197 19.584 53.593 19.656 ;
     RECT  53.549 58.128 53.633 59.256 ;
     RECT  53.633 58.128 53.665 58.68 ;
     RECT  52.585 23.616 53.701 23.88 ;
     RECT  53.521 27.024 53.773 27.192 ;
     RECT  53.665 57.696 53.809 58.68 ;
     RECT  51.304 39.504 53.849 40.104 ;
     RECT  53.665 3.984 53.957 4.008 ;
     RECT  53.701 23.424 54.025 23.88 ;
     RECT  53.773 26.832 54.061 27.192 ;
     RECT  54.025 23.424 54.092 24.504 ;
     RECT  54.092 23.424 54.179 24.648 ;
     RECT  54.061 26.832 54.353 27.24 ;
     RECT  53.809 57.6 54.421 58.68 ;
     RECT  51.304 56.496 54.425 56.52 ;
     RECT  53.593 19.584 54.533 20.568 ;
     RECT  54.421 57.552 54.533 58.68 ;
     RECT  54.179 23.424 54.565 24.504 ;
     RECT  54.533 19.632 54.605 20.568 ;
     RECT  53.413 21.744 54.605 21.96 ;
     RECT  54.533 57.6 54.611 58.68 ;
     RECT  54.605 21.744 54.641 21.768 ;
     RECT  54.353 27.168 54.713 27.24 ;
     RECT  54.611 57.6 54.749 58.248 ;
     RECT  54.713 27.168 54.857 27.192 ;
     RECT  54.565 23.376 54.929 24.504 ;
     RECT  54.749 58.128 54.94 58.248 ;
     RECT  54.929 23.376 54.961 23.688 ;
     RECT  54.605 20.544 55.073 20.568 ;
     RECT  54.961 23.28 55.073 23.688 ;
     RECT  53.849 40.08 55.181 40.104 ;
     RECT  54.94 58.128 55.181 58.152 ;
     RECT  55.073 23.28 55.321 23.304 ;
     RECT  55.321 22.752 55.433 23.304 ;
     RECT  51.304 12.576 56.408 18.024 ;
     RECT  55.433 23.28 56.408 23.304 ;
     RECT  55.285 25.488 56.408 25.512 ;
     RECT  51.304 29.76 56.408 32.856 ;
     RECT  51.304 38.208 56.408 38.232 ;
     RECT  52.441 43.392 56.408 46.104 ;
     RECT  51.304 48.528 56.408 48.552 ;
     RECT  51.304 50.4 56.408 51.192 ;
     RECT  56.408 2.148 56.512 58.332 ;
     RECT  56.512 2.418 56.704 58.062 ;
     RECT  56.704 38.208 57.017 38.712 ;
     RECT  56.704 27.216 58.129 27.24 ;
     RECT  56.704 43.392 58.129 46.68 ;
     RECT  58.129 27.216 58.165 27.672 ;
     RECT  58.129 19.152 58.669 19.176 ;
     RECT  58.129 20.304 58.669 20.328 ;
     RECT  58.129 23.328 58.669 23.352 ;
     RECT  58.165 27.216 58.669 28.104 ;
     RECT  58.129 34.704 58.669 34.728 ;
     RECT  56.704 36 58.669 36.024 ;
     RECT  57.017 38.208 58.669 38.232 ;
     RECT  58.669 19.152 58.705 21.048 ;
     RECT  56.704 25.056 58.705 25.512 ;
     RECT  58.669 34.704 58.705 36.024 ;
     RECT  58.705 19.152 59.209 21.336 ;
     RECT  58.705 24.48 59.245 25.512 ;
     RECT  58.669 26.496 59.245 28.104 ;
     RECT  58.705 34.128 59.245 36.744 ;
     RECT  58.669 37.872 59.245 38.232 ;
     RECT  59.209 19.152 59.281 21.768 ;
     RECT  58.669 23.04 59.281 23.352 ;
     RECT  59.245 24.48 59.281 28.104 ;
     RECT  56.704 10.224 59.857 10.248 ;
     RECT  56.704 12.096 59.857 18.024 ;
     RECT  59.281 19.152 59.857 28.104 ;
     RECT  56.704 29.76 59.857 32.856 ;
     RECT  59.245 34.128 59.857 38.232 ;
     RECT  59.245 39.744 59.857 39.768 ;
     RECT  58.129 43.392 59.857 47.4 ;
     RECT  56.704 48.528 59.857 49.416 ;
     RECT  56.704 50.4 59.857 51.288 ;
     RECT  59.857 9.936 59.893 28.104 ;
     RECT  59.857 43.344 59.929 52.296 ;
     RECT  59.893 9.936 60.396 9.96 ;
     RECT  59.893 9.96 60.444 10.08 ;
     RECT  59.893 10.08 60.396 10.104 ;
     RECT  59.893 10.104 60.444 10.224 ;
     RECT  59.893 10.224 60.396 10.248 ;
     RECT  59.893 10.248 60.444 10.368 ;
     RECT  59.893 10.368 60.396 10.392 ;
     RECT  59.893 10.392 60.444 10.512 ;
     RECT  59.893 10.512 60.396 10.536 ;
     RECT  59.893 10.536 60.444 10.656 ;
     RECT  59.893 10.656 60.396 10.68 ;
     RECT  59.893 10.68 60.444 10.8 ;
     RECT  59.893 10.8 60.396 10.824 ;
     RECT  59.893 10.824 60.444 10.944 ;
     RECT  59.893 10.944 60.396 10.968 ;
     RECT  59.893 10.968 60.444 11.088 ;
     RECT  59.893 11.088 60.396 11.112 ;
     RECT  59.893 11.112 60.444 11.232 ;
     RECT  59.893 11.232 60.396 11.256 ;
     RECT  59.893 11.256 60.444 11.376 ;
     RECT  59.893 11.376 60.396 11.4 ;
     RECT  59.893 11.4 60.444 11.52 ;
     RECT  59.893 11.52 60.396 11.544 ;
     RECT  59.893 11.544 60.444 11.664 ;
     RECT  59.893 11.664 60.396 11.688 ;
     RECT  59.893 11.688 60.444 11.808 ;
     RECT  59.893 11.808 60.396 11.832 ;
     RECT  59.893 11.832 60.444 11.952 ;
     RECT  59.893 11.952 60.396 11.976 ;
     RECT  59.893 11.976 60.444 12.096 ;
     RECT  59.893 12.096 60.396 12.12 ;
     RECT  59.893 12.12 60.444 12.24 ;
     RECT  59.893 12.24 60.396 12.264 ;
     RECT  59.893 12.264 60.444 12.384 ;
     RECT  59.893 12.384 60.396 12.408 ;
     RECT  59.893 12.408 60.444 12.528 ;
     RECT  59.893 12.528 60.396 12.552 ;
     RECT  59.893 12.552 60.444 12.672 ;
     RECT  59.893 12.672 60.396 12.696 ;
     RECT  59.893 12.696 60.444 12.816 ;
     RECT  59.893 12.816 60.396 12.84 ;
     RECT  59.893 12.84 60.444 12.96 ;
     RECT  59.893 12.96 60.396 12.984 ;
     RECT  59.893 12.984 60.444 13.104 ;
     RECT  59.893 13.104 60.396 13.128 ;
     RECT  59.893 13.128 60.444 13.248 ;
     RECT  59.893 13.248 60.396 13.272 ;
     RECT  59.893 13.272 60.444 13.392 ;
     RECT  59.893 13.392 60.396 13.416 ;
     RECT  59.893 13.416 60.444 13.536 ;
     RECT  59.893 13.536 60.396 13.56 ;
     RECT  59.893 13.56 60.444 13.68 ;
     RECT  59.893 13.68 60.396 13.704 ;
     RECT  59.893 13.704 60.444 13.824 ;
     RECT  59.893 13.824 60.396 13.848 ;
     RECT  59.893 13.848 60.444 13.968 ;
     RECT  59.893 13.968 60.396 13.992 ;
     RECT  59.893 13.992 60.444 14.112 ;
     RECT  59.893 14.112 60.396 14.136 ;
     RECT  59.893 14.136 60.444 14.256 ;
     RECT  59.893 14.256 60.396 14.28 ;
     RECT  59.893 14.28 60.444 14.4 ;
     RECT  59.893 14.4 60.396 14.424 ;
     RECT  59.893 14.424 60.444 14.544 ;
     RECT  59.893 14.544 60.396 14.568 ;
     RECT  59.893 14.568 60.444 14.688 ;
     RECT  59.893 14.688 60.396 14.712 ;
     RECT  59.893 14.712 60.444 14.832 ;
     RECT  59.893 14.832 60.396 14.856 ;
     RECT  59.893 14.856 60.444 14.976 ;
     RECT  59.893 14.976 60.396 15 ;
     RECT  59.893 15 60.444 15.12 ;
     RECT  59.893 15.12 60.396 15.144 ;
     RECT  59.893 15.144 60.444 15.264 ;
     RECT  59.893 15.264 60.396 15.288 ;
     RECT  59.893 15.288 60.444 15.408 ;
     RECT  59.893 15.408 60.396 15.432 ;
     RECT  59.893 15.432 60.444 15.552 ;
     RECT  59.893 15.552 60.396 15.576 ;
     RECT  59.893 15.576 60.444 15.696 ;
     RECT  59.893 15.696 60.396 15.72 ;
     RECT  59.893 15.72 60.444 15.84 ;
     RECT  59.893 15.84 60.396 15.864 ;
     RECT  59.893 15.864 60.444 15.984 ;
     RECT  59.893 15.984 60.396 16.008 ;
     RECT  59.893 16.008 60.444 16.128 ;
     RECT  59.893 16.128 60.396 16.152 ;
     RECT  59.893 16.152 60.444 16.272 ;
     RECT  59.893 16.272 60.396 16.296 ;
     RECT  59.893 16.296 60.444 16.416 ;
     RECT  59.893 16.416 60.396 16.44 ;
     RECT  59.893 16.44 60.444 16.56 ;
     RECT  59.893 16.56 60.396 16.584 ;
     RECT  59.893 16.584 60.444 16.704 ;
     RECT  59.893 16.704 60.396 16.728 ;
     RECT  59.893 16.728 60.444 16.848 ;
     RECT  59.893 16.848 60.396 16.872 ;
     RECT  59.893 16.872 60.444 16.992 ;
     RECT  59.893 16.992 60.396 17.016 ;
     RECT  59.893 17.016 60.444 17.136 ;
     RECT  59.893 17.136 60.396 17.16 ;
     RECT  59.893 17.16 60.444 17.28 ;
     RECT  59.893 17.28 60.396 17.304 ;
     RECT  59.893 17.304 60.444 17.424 ;
     RECT  59.893 17.424 60.396 17.448 ;
     RECT  59.893 17.448 60.444 17.568 ;
     RECT  59.893 17.568 60.396 17.592 ;
     RECT  59.893 17.592 60.444 17.712 ;
     RECT  59.893 17.712 60.396 17.736 ;
     RECT  59.893 17.736 60.444 17.856 ;
     RECT  59.893 17.856 60.396 17.88 ;
     RECT  59.893 17.88 60.444 18 ;
     RECT  59.893 18 60.396 18.024 ;
     RECT  59.893 18.024 60.444 18.144 ;
     RECT  59.893 18.144 60.396 18.168 ;
     RECT  59.893 18.168 60.444 18.288 ;
     RECT  59.893 18.288 60.396 18.312 ;
     RECT  59.893 18.312 60.444 18.432 ;
     RECT  59.893 18.432 60.396 18.456 ;
     RECT  59.893 18.456 60.444 18.576 ;
     RECT  59.893 18.576 60.396 18.6 ;
     RECT  59.893 18.6 60.444 18.72 ;
     RECT  59.893 18.72 60.396 18.744 ;
     RECT  59.893 18.744 60.444 18.864 ;
     RECT  59.893 18.864 60.396 18.888 ;
     RECT  59.893 18.888 60.444 19.008 ;
     RECT  59.893 19.008 60.396 19.032 ;
     RECT  59.893 19.032 60.444 19.152 ;
     RECT  59.893 19.152 60.396 19.176 ;
     RECT  59.893 19.176 60.444 19.296 ;
     RECT  59.893 19.296 60.396 19.32 ;
     RECT  59.893 19.32 60.444 19.44 ;
     RECT  59.893 19.44 60.396 19.464 ;
     RECT  59.893 19.464 60.444 19.584 ;
     RECT  59.893 19.584 60.396 19.608 ;
     RECT  59.893 19.608 60.444 19.728 ;
     RECT  59.893 19.728 60.396 19.752 ;
     RECT  59.893 19.752 60.444 19.872 ;
     RECT  59.893 19.872 60.396 19.896 ;
     RECT  59.893 19.896 60.444 20.016 ;
     RECT  59.893 20.016 60.396 20.04 ;
     RECT  59.893 20.04 60.444 20.16 ;
     RECT  59.893 20.16 60.396 20.184 ;
     RECT  59.893 20.184 60.444 20.304 ;
     RECT  59.893 20.304 60.396 20.328 ;
     RECT  59.893 20.328 60.444 20.448 ;
     RECT  59.893 20.448 60.396 20.472 ;
     RECT  59.893 20.472 60.444 20.592 ;
     RECT  59.893 20.592 60.396 20.616 ;
     RECT  59.893 20.616 60.444 20.736 ;
     RECT  59.893 20.736 60.396 20.76 ;
     RECT  59.893 20.76 60.444 20.88 ;
     RECT  59.893 20.88 60.396 20.904 ;
     RECT  59.893 20.904 60.444 21.024 ;
     RECT  59.893 21.024 60.396 21.048 ;
     RECT  59.893 21.048 60.444 21.168 ;
     RECT  59.893 21.168 60.396 21.192 ;
     RECT  59.893 21.192 60.444 21.312 ;
     RECT  59.893 21.312 60.396 21.336 ;
     RECT  59.893 21.336 60.444 21.456 ;
     RECT  59.893 21.456 60.396 21.48 ;
     RECT  59.893 21.48 60.444 21.6 ;
     RECT  59.893 21.6 60.396 21.624 ;
     RECT  59.893 21.624 60.444 21.744 ;
     RECT  59.893 21.744 60.396 21.768 ;
     RECT  59.893 21.768 60.444 21.888 ;
     RECT  59.893 21.888 60.396 21.912 ;
     RECT  59.893 21.912 60.444 22.032 ;
     RECT  59.893 22.032 60.396 22.056 ;
     RECT  59.893 22.056 60.444 22.176 ;
     RECT  59.893 22.176 60.396 22.2 ;
     RECT  59.893 22.2 60.444 22.32 ;
     RECT  59.893 22.32 60.396 22.344 ;
     RECT  59.893 22.344 60.444 22.464 ;
     RECT  59.893 22.464 60.396 22.488 ;
     RECT  59.893 22.488 60.444 22.608 ;
     RECT  59.893 22.608 60.396 22.632 ;
     RECT  59.893 22.632 60.444 22.752 ;
     RECT  59.893 22.752 60.396 22.776 ;
     RECT  59.893 22.776 60.444 22.896 ;
     RECT  59.893 22.896 60.396 22.92 ;
     RECT  59.893 22.92 60.444 23.04 ;
     RECT  59.893 23.04 60.396 23.064 ;
     RECT  59.893 23.064 60.444 23.184 ;
     RECT  59.893 23.184 60.396 23.208 ;
     RECT  59.893 23.208 60.444 23.328 ;
     RECT  59.893 23.328 60.396 23.352 ;
     RECT  59.893 23.352 60.444 23.472 ;
     RECT  59.893 23.472 60.396 23.496 ;
     RECT  59.893 23.496 60.444 23.616 ;
     RECT  59.893 23.616 60.396 23.64 ;
     RECT  59.893 23.64 60.444 23.76 ;
     RECT  59.893 23.76 60.396 23.784 ;
     RECT  59.893 23.784 60.444 23.904 ;
     RECT  59.893 23.904 60.396 23.928 ;
     RECT  59.893 23.928 60.444 24.048 ;
     RECT  59.893 24.048 60.396 24.072 ;
     RECT  59.893 24.072 60.444 24.192 ;
     RECT  59.893 24.192 60.396 24.216 ;
     RECT  59.893 24.216 60.444 24.336 ;
     RECT  59.893 24.336 60.396 24.36 ;
     RECT  59.893 24.36 60.444 24.48 ;
     RECT  59.893 24.48 60.396 24.504 ;
     RECT  59.893 24.504 60.444 24.624 ;
     RECT  59.893 24.624 60.396 24.648 ;
     RECT  59.893 24.648 60.444 24.768 ;
     RECT  59.893 24.768 60.396 24.792 ;
     RECT  59.893 24.792 60.444 24.912 ;
     RECT  59.893 24.912 60.396 24.936 ;
     RECT  59.893 24.936 60.444 25.056 ;
     RECT  59.893 25.056 60.396 25.08 ;
     RECT  59.893 25.08 60.444 25.2 ;
     RECT  59.893 25.2 60.396 25.224 ;
     RECT  59.893 25.224 60.444 25.344 ;
     RECT  59.893 25.344 60.396 25.368 ;
     RECT  59.893 25.368 60.444 25.488 ;
     RECT  59.893 25.488 60.396 25.512 ;
     RECT  59.893 25.512 60.444 25.632 ;
     RECT  59.893 25.632 60.396 25.656 ;
     RECT  59.893 25.656 60.444 25.776 ;
     RECT  59.893 25.776 60.396 25.8 ;
     RECT  59.893 25.8 60.444 25.92 ;
     RECT  59.893 25.92 60.396 25.944 ;
     RECT  59.893 25.944 60.444 26.064 ;
     RECT  59.893 26.064 60.396 26.088 ;
     RECT  59.893 26.088 60.444 26.208 ;
     RECT  59.893 26.208 60.396 26.232 ;
     RECT  59.893 26.232 60.444 26.352 ;
     RECT  59.893 26.352 60.396 26.376 ;
     RECT  59.893 26.376 60.444 26.496 ;
     RECT  59.893 26.496 60.396 26.52 ;
     RECT  59.893 26.52 60.444 26.64 ;
     RECT  59.893 26.64 60.396 26.664 ;
     RECT  59.893 26.664 60.444 26.784 ;
     RECT  59.893 26.784 60.396 26.808 ;
     RECT  59.893 26.808 60.444 26.928 ;
     RECT  59.893 26.928 60.396 26.952 ;
     RECT  59.893 26.952 60.444 27.072 ;
     RECT  59.893 27.072 60.396 27.096 ;
     RECT  59.893 27.096 60.444 27.216 ;
     RECT  59.893 27.216 60.396 27.24 ;
     RECT  59.893 27.24 60.444 27.36 ;
     RECT  59.893 27.36 60.396 27.384 ;
     RECT  59.893 27.384 60.444 27.504 ;
     RECT  59.893 27.504 60.396 27.528 ;
     RECT  59.893 27.528 60.444 27.648 ;
     RECT  59.893 27.648 60.396 27.672 ;
     RECT  59.893 27.672 60.444 27.792 ;
     RECT  59.893 27.792 60.396 27.816 ;
     RECT  59.893 27.816 60.444 27.936 ;
     RECT  59.893 27.936 60.396 27.96 ;
     RECT  59.893 27.96 60.444 28.08 ;
     RECT  59.893 28.08 60.396 28.104 ;
     RECT  59.893 28.104 60.444 28.224 ;
     RECT  59.893 28.224 60.396 28.248 ;
     RECT  59.857 29.52 60.396 29.544 ;
     RECT  59.857 29.544 60.444 29.664 ;
     RECT  59.857 29.664 60.396 29.688 ;
     RECT  59.857 29.688 60.444 29.808 ;
     RECT  59.857 29.808 60.396 29.832 ;
     RECT  59.857 29.832 60.444 29.952 ;
     RECT  59.857 29.952 60.396 29.976 ;
     RECT  59.857 29.976 60.444 30.096 ;
     RECT  59.857 30.096 60.396 30.12 ;
     RECT  59.857 30.12 60.444 30.24 ;
     RECT  59.857 30.24 60.396 30.264 ;
     RECT  59.857 30.264 60.444 30.384 ;
     RECT  59.857 30.384 60.396 30.408 ;
     RECT  59.857 30.408 60.444 30.528 ;
     RECT  59.857 30.528 60.396 30.552 ;
     RECT  59.857 30.552 60.444 30.672 ;
     RECT  59.857 30.672 60.396 30.696 ;
     RECT  59.857 30.696 60.444 30.816 ;
     RECT  59.857 30.816 60.396 30.84 ;
     RECT  59.857 30.84 60.444 30.96 ;
     RECT  59.857 30.96 60.396 30.984 ;
     RECT  59.857 30.984 60.444 31.104 ;
     RECT  59.857 31.104 60.396 31.128 ;
     RECT  59.857 31.128 60.444 31.248 ;
     RECT  59.857 31.248 60.396 31.272 ;
     RECT  59.857 31.272 60.444 31.392 ;
     RECT  59.857 31.392 60.396 31.416 ;
     RECT  59.857 31.416 60.444 31.536 ;
     RECT  59.857 31.536 60.396 31.56 ;
     RECT  59.857 31.56 60.444 31.68 ;
     RECT  59.857 31.68 60.396 31.704 ;
     RECT  59.857 31.704 60.444 31.824 ;
     RECT  59.857 31.824 60.396 31.848 ;
     RECT  59.857 31.848 60.444 31.968 ;
     RECT  59.857 31.968 60.396 31.992 ;
     RECT  59.857 31.992 60.444 32.112 ;
     RECT  59.857 32.112 60.396 32.136 ;
     RECT  59.857 32.136 60.444 32.256 ;
     RECT  59.857 32.256 60.396 32.28 ;
     RECT  59.857 32.28 60.444 32.4 ;
     RECT  59.857 32.4 60.396 32.424 ;
     RECT  59.857 32.424 60.444 32.544 ;
     RECT  59.857 32.544 60.396 32.568 ;
     RECT  59.857 32.568 60.444 32.688 ;
     RECT  59.857 32.688 60.396 32.712 ;
     RECT  59.857 32.712 60.444 32.832 ;
     RECT  59.857 32.832 60.396 32.856 ;
     RECT  59.857 32.856 60.444 32.976 ;
     RECT  59.857 32.976 60.396 33 ;
     RECT  59.857 33 60.444 33.12 ;
     RECT  59.857 33.12 60.396 33.144 ;
     RECT  59.857 33.144 60.444 33.264 ;
     RECT  59.857 33.264 60.396 33.288 ;
     RECT  59.857 33.288 60.444 33.408 ;
     RECT  59.857 33.408 60.396 33.432 ;
     RECT  59.857 33.432 60.444 33.552 ;
     RECT  59.857 33.552 60.396 33.576 ;
     RECT  59.857 33.576 60.444 33.696 ;
     RECT  59.857 33.696 60.396 33.72 ;
     RECT  59.857 33.72 60.444 33.84 ;
     RECT  59.857 33.84 60.396 33.864 ;
     RECT  59.857 33.864 60.444 33.984 ;
     RECT  59.857 33.984 60.396 34.008 ;
     RECT  59.857 34.008 60.444 34.128 ;
     RECT  59.857 34.128 60.396 34.152 ;
     RECT  59.857 34.152 60.444 34.272 ;
     RECT  59.857 34.272 60.396 34.296 ;
     RECT  59.857 34.296 60.444 34.416 ;
     RECT  59.857 34.416 60.396 34.44 ;
     RECT  59.857 34.44 60.444 34.56 ;
     RECT  59.857 34.56 60.396 34.584 ;
     RECT  59.857 34.584 60.444 34.704 ;
     RECT  59.857 34.704 60.396 34.728 ;
     RECT  59.857 34.728 60.444 34.848 ;
     RECT  59.857 34.848 60.396 34.872 ;
     RECT  59.857 34.872 60.444 34.992 ;
     RECT  59.857 34.992 60.396 35.016 ;
     RECT  59.857 35.016 60.444 35.136 ;
     RECT  59.857 35.136 60.396 35.16 ;
     RECT  59.857 35.16 60.444 35.28 ;
     RECT  59.857 35.28 60.396 35.304 ;
     RECT  59.857 35.304 60.444 35.424 ;
     RECT  59.857 35.424 60.396 35.448 ;
     RECT  59.857 35.448 60.444 35.568 ;
     RECT  59.857 35.568 60.396 35.592 ;
     RECT  59.857 35.592 60.444 35.712 ;
     RECT  59.857 35.712 60.396 35.736 ;
     RECT  59.857 35.736 60.444 35.856 ;
     RECT  59.857 35.856 60.396 35.88 ;
     RECT  59.857 35.88 60.444 36 ;
     RECT  59.857 36 60.396 36.024 ;
     RECT  59.857 36.024 60.444 36.144 ;
     RECT  59.857 36.144 60.396 36.168 ;
     RECT  59.857 36.168 60.444 36.288 ;
     RECT  59.857 36.288 60.396 36.312 ;
     RECT  59.857 36.312 60.444 36.432 ;
     RECT  59.857 36.432 60.396 36.456 ;
     RECT  59.857 36.456 60.444 36.576 ;
     RECT  59.857 36.576 60.396 36.6 ;
     RECT  59.857 36.6 60.444 36.72 ;
     RECT  59.857 36.72 60.396 36.744 ;
     RECT  59.857 36.744 60.444 36.864 ;
     RECT  59.857 36.864 60.396 36.888 ;
     RECT  59.857 36.888 60.444 37.008 ;
     RECT  59.857 37.008 60.396 37.032 ;
     RECT  59.857 37.032 60.444 37.152 ;
     RECT  59.857 37.152 60.396 37.176 ;
     RECT  59.857 37.176 60.444 37.296 ;
     RECT  59.857 37.296 60.396 37.32 ;
     RECT  59.857 37.32 60.444 37.44 ;
     RECT  59.857 37.44 60.396 37.464 ;
     RECT  59.857 37.464 60.444 37.584 ;
     RECT  59.857 37.584 60.396 37.608 ;
     RECT  59.857 37.608 60.444 37.728 ;
     RECT  59.857 37.728 60.396 37.752 ;
     RECT  59.857 37.752 60.444 37.872 ;
     RECT  59.857 37.872 60.396 37.896 ;
     RECT  59.857 37.896 60.444 38.016 ;
     RECT  59.857 38.016 60.396 38.04 ;
     RECT  59.857 38.04 60.444 38.16 ;
     RECT  59.857 38.16 60.396 38.184 ;
     RECT  59.857 38.184 60.444 38.304 ;
     RECT  59.857 38.304 60.396 38.328 ;
     RECT  59.857 38.328 60.444 38.448 ;
     RECT  59.857 38.448 60.396 38.472 ;
     RECT  59.857 38.472 60.444 38.592 ;
     RECT  59.857 38.592 60.396 38.616 ;
     RECT  59.857 38.616 60.444 38.736 ;
     RECT  59.857 38.736 60.396 38.76 ;
     RECT  59.857 38.76 60.444 38.88 ;
     RECT  59.857 38.88 60.396 38.904 ;
     RECT  59.857 38.904 60.444 39.024 ;
     RECT  59.857 39.024 60.396 39.048 ;
     RECT  59.857 39.048 60.444 39.168 ;
     RECT  59.857 39.168 60.396 39.192 ;
     RECT  59.857 39.192 60.444 39.312 ;
     RECT  59.857 39.312 60.396 39.336 ;
     RECT  59.857 39.336 60.444 39.456 ;
     RECT  59.857 39.456 60.396 39.48 ;
     RECT  59.857 39.48 60.444 39.6 ;
     RECT  59.857 39.6 60.396 39.624 ;
     RECT  59.857 39.624 60.444 39.744 ;
     RECT  59.857 39.744 60.396 39.768 ;
     RECT  59.929 43.344 60.396 43.368 ;
     RECT  59.929 43.368 60.444 43.488 ;
     RECT  59.929 43.488 60.396 43.512 ;
     RECT  59.929 43.512 60.444 43.632 ;
     RECT  59.929 43.632 60.396 43.656 ;
     RECT  59.929 43.656 60.444 43.776 ;
     RECT  59.929 43.776 60.396 43.8 ;
     RECT  59.929 43.8 60.444 43.92 ;
     RECT  59.929 43.92 60.396 43.944 ;
     RECT  59.929 43.944 60.444 44.064 ;
     RECT  59.929 44.064 60.396 44.088 ;
     RECT  59.929 44.088 60.444 44.208 ;
     RECT  59.929 44.208 60.396 44.232 ;
     RECT  59.929 44.232 60.444 44.352 ;
     RECT  59.929 44.352 60.396 44.376 ;
     RECT  59.929 44.376 60.444 44.496 ;
     RECT  59.929 44.496 60.396 44.52 ;
     RECT  59.929 44.52 60.444 44.64 ;
     RECT  59.929 44.64 60.396 44.664 ;
     RECT  59.929 44.664 60.444 44.784 ;
     RECT  59.929 44.784 60.396 44.808 ;
     RECT  59.929 44.808 60.444 44.928 ;
     RECT  59.929 44.928 60.396 44.952 ;
     RECT  59.929 44.952 60.444 45.072 ;
     RECT  59.929 45.072 60.396 45.096 ;
     RECT  59.929 45.096 60.444 45.216 ;
     RECT  59.929 45.216 60.396 45.24 ;
     RECT  59.929 45.24 60.444 45.36 ;
     RECT  59.929 45.36 60.396 45.384 ;
     RECT  59.929 45.384 60.444 45.504 ;
     RECT  59.929 45.504 60.396 45.528 ;
     RECT  59.929 45.528 60.444 45.648 ;
     RECT  59.929 45.648 60.396 45.672 ;
     RECT  59.929 45.672 60.444 45.792 ;
     RECT  59.929 45.792 60.396 45.816 ;
     RECT  59.929 45.816 60.444 45.936 ;
     RECT  59.929 45.936 60.396 45.96 ;
     RECT  59.929 45.96 60.444 46.08 ;
     RECT  59.929 46.08 60.396 46.104 ;
     RECT  59.929 46.104 60.444 46.224 ;
     RECT  59.929 46.224 60.396 46.248 ;
     RECT  59.929 46.248 60.444 46.368 ;
     RECT  59.929 46.368 60.396 46.392 ;
     RECT  59.929 46.392 60.444 46.512 ;
     RECT  59.929 46.512 60.396 46.536 ;
     RECT  59.929 46.536 60.444 46.656 ;
     RECT  59.929 46.656 60.396 46.68 ;
     RECT  59.929 46.68 60.444 46.8 ;
     RECT  59.929 46.8 60.396 46.824 ;
     RECT  59.929 46.824 60.444 46.944 ;
     RECT  59.929 46.944 60.396 46.968 ;
     RECT  59.929 46.968 60.444 47.088 ;
     RECT  59.929 47.088 60.396 47.112 ;
     RECT  59.929 47.112 60.444 47.232 ;
     RECT  59.929 47.232 60.396 47.256 ;
     RECT  59.929 47.256 60.444 47.376 ;
     RECT  59.929 47.376 60.396 47.4 ;
     RECT  59.929 47.4 60.444 47.52 ;
     RECT  59.929 47.52 60.396 47.544 ;
     RECT  59.929 47.544 60.444 47.664 ;
     RECT  59.929 47.664 60.396 47.688 ;
     RECT  59.929 47.688 60.444 47.808 ;
     RECT  59.929 47.808 60.396 47.832 ;
     RECT  59.929 47.832 60.444 47.952 ;
     RECT  59.929 47.952 60.396 47.976 ;
     RECT  59.929 47.976 60.444 48.096 ;
     RECT  59.929 48.096 60.396 48.12 ;
     RECT  59.929 48.12 60.444 48.24 ;
     RECT  59.929 48.24 60.396 48.264 ;
     RECT  59.929 48.264 60.444 48.384 ;
     RECT  59.929 48.384 60.396 48.408 ;
     RECT  59.929 48.408 60.444 48.528 ;
     RECT  59.929 48.528 60.396 48.552 ;
     RECT  59.929 48.552 60.444 48.672 ;
     RECT  59.929 48.672 60.396 48.696 ;
     RECT  59.929 48.696 60.444 48.816 ;
     RECT  59.929 48.816 60.396 48.84 ;
     RECT  59.929 48.84 60.444 48.96 ;
     RECT  59.929 48.96 60.396 48.984 ;
     RECT  59.929 48.984 60.444 49.104 ;
     RECT  59.929 49.104 60.396 49.128 ;
     RECT  59.929 49.128 60.444 49.248 ;
     RECT  59.929 49.248 60.396 49.272 ;
     RECT  59.929 49.272 60.444 49.392 ;
     RECT  59.929 49.392 60.396 49.416 ;
     RECT  59.929 49.416 60.444 49.536 ;
     RECT  59.929 49.536 60.396 49.56 ;
     RECT  59.929 49.56 60.444 49.68 ;
     RECT  59.929 49.68 60.396 49.704 ;
     RECT  59.929 49.704 60.444 49.824 ;
     RECT  59.929 49.824 60.396 49.848 ;
     RECT  59.929 49.848 60.444 49.968 ;
     RECT  59.929 49.968 60.396 49.992 ;
     RECT  59.929 49.992 60.444 50.112 ;
     RECT  59.929 50.112 60.396 50.136 ;
     RECT  59.929 50.136 60.444 50.256 ;
     RECT  59.929 50.256 60.396 50.28 ;
     RECT  59.929 50.28 60.444 50.4 ;
     RECT  59.929 50.4 60.396 50.424 ;
     RECT  59.929 50.424 60.444 50.544 ;
     RECT  59.929 50.544 60.396 50.568 ;
     RECT  59.929 50.568 60.444 50.688 ;
     RECT  59.929 50.688 60.396 50.712 ;
     RECT  59.929 50.712 60.444 50.832 ;
     RECT  59.929 50.832 60.396 50.856 ;
     RECT  59.929 50.856 60.444 50.976 ;
     RECT  59.929 50.976 60.396 51 ;
     RECT  59.929 51 60.444 51.12 ;
     RECT  59.929 51.12 60.396 51.144 ;
     RECT  59.929 51.144 60.444 51.264 ;
     RECT  59.929 51.264 60.396 51.288 ;
     RECT  59.929 51.288 60.444 51.408 ;
     RECT  59.929 51.408 60.396 51.432 ;
     RECT  59.929 51.432 60.444 51.552 ;
     RECT  59.929 51.552 60.396 51.576 ;
     RECT  59.929 51.576 60.444 51.696 ;
     RECT  59.929 51.696 60.396 51.72 ;
     RECT  59.929 51.72 60.444 51.84 ;
     RECT  59.929 51.84 60.396 51.864 ;
     RECT  59.929 51.864 60.444 51.984 ;
     RECT  59.929 51.984 60.396 52.008 ;
     RECT  59.929 52.008 60.444 52.128 ;
     RECT  59.929 52.128 60.396 52.152 ;
     RECT  59.929 52.152 60.444 52.272 ;
     RECT  59.929 52.272 60.396 52.296 ;
     RECT  59.929 52.296 60.444 52.416 ;
     RECT  59.929 52.416 60.396 52.44 ;
    LAYER M5 ;
     RECT  5.352 0.016 5.472 0.084 ;
     RECT  5.496 0.016 5.616 0.084 ;
     RECT  5.64 0.016 5.76 0.084 ;
     RECT  5.784 0.016 5.904 0.084 ;
     RECT  5.928 0.016 6.048 0.084 ;
     RECT  6.072 0.016 6.192 0.084 ;
     RECT  6.216 0.016 6.336 0.084 ;
     RECT  6.36 0.016 6.48 0.084 ;
     RECT  6.504 0.016 6.624 0.084 ;
     RECT  6.648 0.016 6.768 0.084 ;
     RECT  6.792 0.016 6.912 0.084 ;
     RECT  6.936 0.016 7.056 0.084 ;
     RECT  7.08 0.016 7.2 0.084 ;
     RECT  7.224 0.016 7.344 0.084 ;
     RECT  7.368 0.016 7.488 0.084 ;
     RECT  7.512 0.016 7.632 0.084 ;
     RECT  7.656 0.016 7.776 0.084 ;
     RECT  7.8 0.016 7.92 0.084 ;
     RECT  7.944 0.016 8.064 0.084 ;
     RECT  8.088 0.016 8.208 0.084 ;
     RECT  8.232 0.016 8.352 0.084 ;
     RECT  8.376 0.016 8.496 0.084 ;
     RECT  8.52 0.016 8.64 0.084 ;
     RECT  8.664 0.016 8.784 0.084 ;
     RECT  8.808 0.016 8.928 0.084 ;
     RECT  8.952 0.016 9.072 0.084 ;
     RECT  9.096 0.016 9.216 0.084 ;
     RECT  9.24 0.016 9.36 0.084 ;
     RECT  9.384 0.016 9.504 0.084 ;
     RECT  9.528 0.016 9.936 0.084 ;
     RECT  9.96 0.016 10.08 0.084 ;
     RECT  10.104 0.016 10.224 0.084 ;
     RECT  10.248 0.016 10.368 0.084 ;
     RECT  10.392 0.016 10.512 0.084 ;
     RECT  10.536 0.016 10.656 0.084 ;
     RECT  10.68 0.016 10.8 0.084 ;
     RECT  10.824 0.016 10.944 0.084 ;
     RECT  10.968 0.016 11.088 0.084 ;
     RECT  11.112 0.016 11.232 0.084 ;
     RECT  11.256 0.016 11.376 0.084 ;
     RECT  11.4 0.016 11.52 0.084 ;
     RECT  11.544 0.016 11.664 0.084 ;
     RECT  11.688 0.016 11.808 0.084 ;
     RECT  11.832 0.016 11.952 0.084 ;
     RECT  11.976 0.016 12.096 0.084 ;
     RECT  12.12 0.016 12.24 0.084 ;
     RECT  12.264 0.016 12.384 0.084 ;
     RECT  12.408 0.016 12.528 0.084 ;
     RECT  12.552 0.016 12.672 0.084 ;
     RECT  12.696 0.016 12.816 0.084 ;
     RECT  12.84 0.016 12.96 0.084 ;
     RECT  12.984 0.016 13.104 0.084 ;
     RECT  13.128 0.016 13.248 0.084 ;
     RECT  13.272 0.016 13.392 0.084 ;
     RECT  13.416 0.016 13.536 0.084 ;
     RECT  13.56 0.016 13.68 0.084 ;
     RECT  13.704 0.016 13.824 0.084 ;
     RECT  13.848 0.016 13.968 0.084 ;
     RECT  13.992 0.016 14.112 0.084 ;
     RECT  14.136 0.016 14.256 0.084 ;
     RECT  14.28 0.016 14.4 0.084 ;
     RECT  14.424 0.016 14.544 0.084 ;
     RECT  14.568 0.016 14.688 0.084 ;
     RECT  14.712 0.016 14.832 0.084 ;
     RECT  14.856 0.016 14.976 0.084 ;
     RECT  15 0.016 15.12 0.084 ;
     RECT  15.144 0.016 15.264 0.084 ;
     RECT  15.288 0.016 15.408 0.084 ;
     RECT  15.432 0.016 15.552 0.084 ;
     RECT  15.576 0.016 15.696 0.084 ;
     RECT  15.72 0.016 15.84 0.084 ;
     RECT  15.864 0.016 15.984 0.084 ;
     RECT  16.008 0.016 16.128 0.084 ;
     RECT  16.152 0.016 16.272 0.084 ;
     RECT  16.296 0.016 16.416 0.084 ;
     RECT  16.44 0.016 16.56 0.084 ;
     RECT  16.584 0.016 16.704 0.084 ;
     RECT  16.728 0.016 16.848 0.084 ;
     RECT  16.872 0.016 16.992 0.084 ;
     RECT  17.016 0.016 17.136 0.084 ;
     RECT  17.16 0.016 17.28 0.084 ;
     RECT  17.304 0.016 17.424 0.084 ;
     RECT  17.448 0.016 17.568 0.084 ;
     RECT  17.592 0.016 17.712 0.084 ;
     RECT  17.736 0.016 17.856 0.084 ;
     RECT  17.88 0.016 18 0.084 ;
     RECT  18.024 0.016 18.144 0.084 ;
     RECT  18.168 0.016 18.288 0.084 ;
     RECT  18.312 0.016 18.432 0.084 ;
     RECT  18.456 0.016 18.576 0.084 ;
     RECT  18.6 0.016 18.72 0.084 ;
     RECT  18.744 0.016 18.864 0.084 ;
     RECT  18.888 0.016 19.008 0.084 ;
     RECT  19.032 0.016 19.152 0.084 ;
     RECT  19.176 0.016 19.296 0.084 ;
     RECT  19.32 0.016 19.44 0.084 ;
     RECT  19.464 0.016 19.584 0.084 ;
     RECT  19.608 0.016 19.728 0.084 ;
     RECT  19.752 0.016 19.872 0.084 ;
     RECT  19.896 0.016 20.016 0.084 ;
     RECT  20.04 0.016 20.16 0.084 ;
     RECT  20.184 0.016 20.304 0.084 ;
     RECT  20.328 0.016 20.448 0.084 ;
     RECT  20.472 0.016 20.592 0.084 ;
     RECT  20.616 0.016 20.736 0.084 ;
     RECT  20.76 0.016 20.88 0.084 ;
     RECT  20.904 0.016 21.024 0.084 ;
     RECT  21.048 0.016 21.168 0.084 ;
     RECT  21.192 0.016 21.312 0.084 ;
     RECT  21.336 0.016 21.456 0.084 ;
     RECT  21.48 0.016 21.6 0.084 ;
     RECT  21.624 0.016 21.744 0.084 ;
     RECT  21.768 0.016 21.888 0.084 ;
     RECT  21.912 0.016 22.032 0.084 ;
     RECT  22.056 0.016 22.176 0.084 ;
     RECT  22.2 0.016 22.32 0.084 ;
     RECT  22.344 0.016 22.464 0.084 ;
     RECT  22.488 0.016 22.608 0.084 ;
     RECT  22.632 0.016 22.752 0.084 ;
     RECT  22.776 0.016 22.896 0.084 ;
     RECT  22.92 0.016 23.04 0.084 ;
     RECT  23.064 0.016 23.184 0.084 ;
     RECT  23.208 0.016 23.328 0.084 ;
     RECT  23.352 0.016 23.472 0.084 ;
     RECT  23.496 0.016 23.616 0.084 ;
     RECT  23.64 0.016 23.76 0.084 ;
     RECT  23.784 0.016 23.904 0.084 ;
     RECT  23.928 0.016 24.048 0.084 ;
     RECT  24.072 0.016 24.192 0.084 ;
     RECT  24.216 0.016 24.336 0.084 ;
     RECT  24.36 0.016 24.48 0.084 ;
     RECT  24.504 0.016 24.624 0.084 ;
     RECT  24.648 0.016 24.768 0.084 ;
     RECT  24.792 0.016 24.912 0.084 ;
     RECT  24.936 0.016 25.056 0.084 ;
     RECT  25.08 0.016 25.2 0.084 ;
     RECT  25.224 0.016 25.344 0.084 ;
     RECT  25.368 0.016 25.488 0.084 ;
     RECT  25.512 0.016 25.632 0.084 ;
     RECT  25.656 0.016 25.776 0.084 ;
     RECT  25.8 0.016 25.92 0.084 ;
     RECT  25.944 0.016 26.064 0.084 ;
     RECT  26.088 0.016 26.208 0.084 ;
     RECT  26.232 0.016 26.352 0.084 ;
     RECT  26.376 0.016 26.496 0.084 ;
     RECT  26.52 0.016 26.64 0.084 ;
     RECT  26.664 0.016 26.784 0.084 ;
     RECT  26.808 0.016 26.928 0.084 ;
     RECT  26.952 0.016 27.072 0.084 ;
     RECT  27.096 0.016 27.216 0.084 ;
     RECT  27.24 0.016 27.36 0.084 ;
     RECT  27.384 0.016 27.504 0.084 ;
     RECT  27.528 0.016 27.648 0.084 ;
     RECT  27.672 0.016 27.792 0.084 ;
     RECT  27.816 0.016 27.936 0.084 ;
     RECT  27.96 0.016 28.08 0.084 ;
     RECT  28.104 0.016 28.224 0.084 ;
     RECT  5.328 0.084 28.248 0.131 ;
     RECT  34.152 0.016 34.272 0.084 ;
     RECT  34.296 0.016 34.416 0.084 ;
     RECT  34.44 0.016 34.56 0.084 ;
     RECT  34.584 0.016 34.704 0.084 ;
     RECT  34.728 0.016 34.848 0.084 ;
     RECT  34.872 0.016 34.992 0.084 ;
     RECT  35.016 0.016 35.136 0.084 ;
     RECT  35.16 0.016 35.28 0.084 ;
     RECT  35.304 0.016 35.424 0.084 ;
     RECT  35.448 0.016 35.568 0.084 ;
     RECT  35.592 0.016 35.712 0.084 ;
     RECT  35.736 0.016 35.856 0.084 ;
     RECT  35.88 0.016 36 0.084 ;
     RECT  36.024 0.016 36.144 0.084 ;
     RECT  36.168 0.016 36.288 0.084 ;
     RECT  36.312 0.016 36.432 0.084 ;
     RECT  36.456 0.016 36.576 0.084 ;
     RECT  36.6 0.016 36.72 0.084 ;
     RECT  36.744 0.016 36.864 0.084 ;
     RECT  36.888 0.016 37.008 0.084 ;
     RECT  37.032 0.016 37.152 0.084 ;
     RECT  37.176 0.016 37.296 0.084 ;
     RECT  37.32 0.016 37.44 0.084 ;
     RECT  37.464 0.016 37.584 0.084 ;
     RECT  37.608 0.016 37.728 0.084 ;
     RECT  37.752 0.016 37.872 0.084 ;
     RECT  37.896 0.016 38.016 0.084 ;
     RECT  38.04 0.016 38.16 0.084 ;
     RECT  38.184 0.016 38.304 0.084 ;
     RECT  38.328 0.016 38.448 0.084 ;
     RECT  38.472 0.016 38.592 0.084 ;
     RECT  38.616 0.016 38.736 0.084 ;
     RECT  38.76 0.016 38.88 0.084 ;
     RECT  38.904 0.016 39.024 0.084 ;
     RECT  39.048 0.016 39.168 0.084 ;
     RECT  39.192 0.016 39.312 0.084 ;
     RECT  39.336 0.016 39.456 0.084 ;
     RECT  39.48 0.016 39.6 0.084 ;
     RECT  39.624 0.016 39.744 0.084 ;
     RECT  39.768 0.016 39.888 0.084 ;
     RECT  39.912 0.016 40.032 0.084 ;
     RECT  40.056 0.016 40.176 0.084 ;
     RECT  40.2 0.016 40.32 0.084 ;
     RECT  40.344 0.016 40.464 0.084 ;
     RECT  40.488 0.016 40.608 0.084 ;
     RECT  40.632 0.016 40.752 0.084 ;
     RECT  40.776 0.016 40.896 0.084 ;
     RECT  40.92 0.016 41.04 0.084 ;
     RECT  41.064 0.016 41.184 0.084 ;
     RECT  41.208 0.016 41.328 0.084 ;
     RECT  41.352 0.016 41.472 0.084 ;
     RECT  41.496 0.016 41.616 0.084 ;
     RECT  41.64 0.016 41.76 0.084 ;
     RECT  41.784 0.016 41.904 0.084 ;
     RECT  41.928 0.016 42.048 0.084 ;
     RECT  42.072 0.016 42.192 0.084 ;
     RECT  42.216 0.016 42.336 0.084 ;
     RECT  42.36 0.016 42.48 0.084 ;
     RECT  42.504 0.016 42.624 0.084 ;
     RECT  42.648 0.016 42.768 0.084 ;
     RECT  42.792 0.016 42.912 0.084 ;
     RECT  42.936 0.016 43.056 0.084 ;
     RECT  43.08 0.016 43.2 0.084 ;
     RECT  43.224 0.016 43.344 0.084 ;
     RECT  43.368 0.016 43.488 0.084 ;
     RECT  43.512 0.016 43.632 0.084 ;
     RECT  43.656 0.016 43.776 0.084 ;
     RECT  43.8 0.016 43.92 0.084 ;
     RECT  43.944 0.016 44.064 0.084 ;
     RECT  44.088 0.016 44.208 0.084 ;
     RECT  44.232 0.016 44.352 0.084 ;
     RECT  44.376 0.016 44.496 0.084 ;
     RECT  44.52 0.016 44.64 0.084 ;
     RECT  44.664 0.016 44.784 0.084 ;
     RECT  44.808 0.016 44.928 0.084 ;
     RECT  44.952 0.016 45.072 0.084 ;
     RECT  45.096 0.016 45.216 0.084 ;
     RECT  45.24 0.016 45.36 0.084 ;
     RECT  45.384 0.016 45.504 0.084 ;
     RECT  45.528 0.016 45.648 0.084 ;
     RECT  45.672 0.016 45.792 0.084 ;
     RECT  45.816 0.016 45.936 0.084 ;
     RECT  45.96 0.016 46.08 0.084 ;
     RECT  46.104 0.016 46.224 0.084 ;
     RECT  46.248 0.016 46.368 0.084 ;
     RECT  46.392 0.016 46.512 0.084 ;
     RECT  46.536 0.016 46.656 0.084 ;
     RECT  46.68 0.016 46.8 0.084 ;
     RECT  46.824 0.016 46.944 0.084 ;
     RECT  46.968 0.016 47.088 0.084 ;
     RECT  47.112 0.016 47.232 0.084 ;
     RECT  47.256 0.016 47.376 0.084 ;
     RECT  47.4 0.016 47.52 0.084 ;
     RECT  47.544 0.016 47.664 0.084 ;
     RECT  47.688 0.016 47.808 0.084 ;
     RECT  47.832 0.016 47.952 0.084 ;
     RECT  47.976 0.016 48.096 0.084 ;
     RECT  48.12 0.016 48.24 0.084 ;
     RECT  48.264 0.016 48.384 0.084 ;
     RECT  48.408 0.016 48.528 0.084 ;
     RECT  48.552 0.016 48.672 0.084 ;
     RECT  48.696 0.016 48.816 0.084 ;
     RECT  48.84 0.016 48.96 0.084 ;
     RECT  48.984 0.016 49.104 0.084 ;
     RECT  49.128 0.016 49.248 0.084 ;
     RECT  49.272 0.016 49.392 0.084 ;
     RECT  49.416 0.016 49.536 0.084 ;
     RECT  49.56 0.016 49.68 0.084 ;
     RECT  49.704 0.016 49.824 0.084 ;
     RECT  49.848 0.016 49.968 0.084 ;
     RECT  49.992 0.016 50.112 0.084 ;
     RECT  50.136 0.016 50.256 0.084 ;
     RECT  50.28 0.016 50.4 0.084 ;
     RECT  50.424 0.016 50.544 0.084 ;
     RECT  50.568 0.016 50.688 0.084 ;
     RECT  50.712 0.016 50.832 0.084 ;
     RECT  50.856 0.016 50.976 0.084 ;
     RECT  51 0.016 51.12 0.084 ;
     RECT  51.144 0.016 51.264 0.084 ;
     RECT  51.288 0.016 51.408 0.084 ;
     RECT  51.432 0.016 51.552 0.084 ;
     RECT  51.576 0.016 51.696 0.084 ;
     RECT  51.72 0.016 51.84 0.084 ;
     RECT  51.864 0.016 51.984 0.084 ;
     RECT  52.008 0.016 52.128 0.084 ;
     RECT  52.152 0.016 52.272 0.084 ;
     RECT  52.296 0.016 52.416 0.084 ;
     RECT  34.128 0.084 52.44 0.131 ;
     RECT  5.616 0.131 28.248 1.139 ;
     RECT  6.336 1.139 28.248 1.187 ;
     RECT  6.768 1.187 28.248 1.763 ;
     RECT  34.272 0.131 52.44 1.763 ;
     RECT  7.344 1.763 19.32 1.859 ;
     RECT  20.304 1.763 28.248 1.859 ;
     RECT  34.8 1.763 52.44 1.859 ;
     RECT  20.304 1.859 27.816 1.955 ;
     RECT  2.4 2.137 2.52 2.151 ;
     RECT  29.4 2.137 29.52 2.151 ;
     RECT  56.4 2.137 56.52 2.151 ;
     RECT  7.344 1.859 10.68 2.291 ;
     RECT  11.808 1.859 19.32 2.291 ;
     RECT  20.304 1.955 25.656 2.291 ;
     RECT  26.64 1.955 27.816 2.291 ;
     RECT  36.432 1.859 52.44 2.291 ;
     RECT  7.344 2.291 9.24 2.339 ;
     RECT  26.64 2.291 26.952 2.339 ;
     RECT  38.16 2.291 44.52 2.339 ;
     RECT  45.6 2.291 52.008 2.339 ;
     RECT  26.64 2.339 26.664 2.771 ;
     RECT  6.24 2.245 6.264 2.867 ;
     RECT  11.808 2.291 17.016 2.867 ;
     RECT  20.304 2.291 24.504 2.915 ;
     RECT  39.744 2.339 44.52 2.915 ;
     RECT  50.256 2.339 52.008 3.011 ;
     RECT  21.6 2.915 24.504 3.059 ;
     RECT  39.984 2.915 44.52 3.251 ;
     RECT  14.688 2.867 17.016 3.443 ;
     RECT  34.8 1.859 35.256 3.635 ;
     RECT  29.4 2.151 29.712 3.925 ;
     RECT  33.024 3.733 33.048 4.501 ;
     RECT  32.544 4.501 33.048 4.547 ;
     RECT  45.6 2.339 48.984 4.547 ;
     RECT  7.344 2.339 8.952 4.595 ;
     RECT  11.808 2.867 13.656 4.595 ;
     RECT  38.16 2.339 38.76 4.837 ;
     RECT  14.688 3.443 16.008 4.885 ;
     RECT  16.992 3.443 17.016 4.885 ;
     RECT  45.6 4.547 47.304 4.931 ;
     RECT  40.2 3.251 44.52 4.933 ;
     RECT  45.6 4.931 47.256 4.933 ;
     RECT  12.816 4.595 13.656 4.981 ;
     RECT  14.688 4.885 17.016 4.981 ;
     RECT  18.384 2.291 19.176 5.077 ;
     RECT  34.8 3.635 35.208 5.077 ;
     RECT  12.816 4.981 17.016 5.123 ;
     RECT  18.288 5.077 19.176 5.125 ;
     RECT  20.304 2.915 20.328 5.125 ;
     RECT  11.808 4.595 11.832 5.171 ;
     RECT  21.6 3.059 22.2 5.171 ;
     RECT  23.76 3.059 24.504 5.171 ;
     RECT  40.2 4.933 47.256 5.171 ;
     RECT  48.384 4.547 48.984 5.171 ;
     RECT  32.544 4.547 32.568 5.173 ;
     RECT  12.816 5.123 13.656 5.267 ;
     RECT  18.288 5.125 20.328 5.411 ;
     RECT  18.384 5.411 20.328 5.507 ;
     RECT  42.912 5.171 47.256 5.507 ;
     RECT  18.6 5.507 20.328 5.603 ;
     RECT  12.816 5.267 13.608 5.605 ;
     RECT  20.304 5.603 20.328 5.653 ;
     RECT  21.6 5.171 21.624 5.653 ;
     RECT  7.344 4.595 8.52 5.747 ;
     RECT  15.12 5.123 17.016 5.747 ;
     RECT  24 5.171 24.504 5.747 ;
     RECT  36.432 2.291 37.032 5.747 ;
     RECT  38.16 4.837 38.904 5.747 ;
     RECT  42.912 5.507 46.104 5.747 ;
     RECT  47.232 5.507 47.256 5.747 ;
     RECT  48.384 5.171 48.408 5.747 ;
     RECT  50.784 3.011 52.008 5.747 ;
     RECT  20.304 5.653 21.624 5.795 ;
     RECT  34.8 5.077 35.352 5.795 ;
     RECT  43.632 5.747 46.056 5.987 ;
     RECT  12.672 5.605 13.608 6.035 ;
     RECT  37.008 5.747 37.032 6.083 ;
     RECT  44.064 5.987 46.056 6.083 ;
     RECT  21.6 5.795 21.624 6.131 ;
     RECT  15.84 5.747 15.864 6.227 ;
     RECT  20.304 5.795 20.328 6.227 ;
     RECT  12.816 6.035 13.608 6.323 ;
     RECT  40.2 5.171 41.352 6.323 ;
     RECT  44.064 6.083 46.008 6.323 ;
     RECT  44.496 6.323 46.008 6.419 ;
     RECT  45.6 6.419 46.008 6.611 ;
     RECT  24 5.747 24.312 6.757 ;
     RECT  18.6 5.603 19.176 6.803 ;
     RECT  23.28 6.757 24.312 6.899 ;
     RECT  7.488 5.747 8.112 6.995 ;
     RECT  44.496 6.419 44.52 6.995 ;
     RECT  13.104 6.323 13.608 7.043 ;
     RECT  13.104 7.043 13.512 7.091 ;
     RECT  32.448 5.173 32.568 8.485 ;
     RECT  28.8 3.925 29.712 9.781 ;
     RECT  25.488 3.349 25.512 10.069 ;
     RECT  28.8 9.781 29.88 10.307 ;
     RECT  32.448 8.485 33.048 10.595 ;
     RECT  25.488 10.069 26.28 10.835 ;
     RECT  29.4 10.307 29.88 10.883 ;
     RECT  24 6.899 24.312 11.653 ;
     RECT  24 11.653 24.456 12.517 ;
     RECT  23.472 12.517 24.456 12.563 ;
     RECT  25.488 10.835 26.232 12.563 ;
     RECT  38.88 5.747 38.904 12.563 ;
     RECT  25.488 12.563 25.512 12.803 ;
     RECT  23.472 12.563 24.312 13.285 ;
     RECT  7.8 6.995 8.112 13.333 ;
     RECT  7.68 13.333 8.112 13.621 ;
     RECT  9.168 13.045 9.192 13.621 ;
     RECT  29.4 10.883 29.712 13.861 ;
     RECT  7.68 13.621 9.192 14.389 ;
     RECT  23.04 13.285 24.312 14.915 ;
     RECT  25.344 14.773 25.368 14.917 ;
     RECT  25.344 14.917 25.56 14.963 ;
     RECT  23.904 14.915 24.312 15.011 ;
     RECT  7.584 14.389 9.192 15.491 ;
     RECT  37.728 14.773 38.52 15.779 ;
     RECT  25.536 14.963 25.56 15.971 ;
     RECT  7.8 15.491 9.096 16.595 ;
     RECT  32.448 10.595 32.472 16.643 ;
     RECT  38.496 15.779 38.52 16.883 ;
     RECT  24 15.011 24.312 16.885 ;
     RECT  29.232 13.861 29.712 16.885 ;
     RECT  24 16.885 24.408 17.075 ;
     RECT  4.224 16.501 4.248 17.123 ;
     RECT  20.16 12.757 20.184 17.603 ;
     RECT  18.6 6.803 18.912 17.605 ;
     RECT  6.048 14.533 6.072 17.653 ;
     RECT  5.904 17.653 6.072 17.699 ;
     RECT  18.144 17.605 18.912 18.133 ;
     RECT  43.008 15.445 43.032 18.805 ;
     RECT  18.144 18.133 19.512 18.851 ;
     RECT  43.008 18.805 43.272 18.851 ;
     RECT  21.744 18.181 21.768 19.379 ;
     RECT  50.784 5.747 51.312 19.861 ;
     RECT  50.736 19.861 51.312 20.867 ;
     RECT  49.44 19.237 49.464 21.155 ;
     RECT  5.904 17.699 5.928 21.301 ;
     RECT  5.904 21.301 6.504 22.355 ;
     RECT  6.48 22.355 6.504 22.547 ;
     RECT  50.784 20.867 51.312 22.787 ;
     RECT  40.2 6.323 40.512 23.317 ;
     RECT  43.248 18.851 43.272 23.317 ;
     RECT  45.6 6.611 45.912 23.317 ;
     RECT  52.704 22.213 52.728 23.843 ;
     RECT  40.2 23.317 40.632 23.987 ;
     RECT  45.6 23.317 46.776 23.987 ;
     RECT  7.8 16.595 9.048 24.469 ;
     RECT  43.248 23.317 43.944 24.515 ;
     RECT  54.144 23.797 54.168 24.659 ;
     RECT  40.2 23.987 40.512 24.901 ;
     RECT  42.192 23.893 42.216 24.947 ;
     RECT  6.912 24.469 9.048 25.715 ;
     RECT  45.6 23.987 45.912 26.629 ;
     RECT  7.8 25.715 9.048 26.677 ;
     RECT  49.152 26.725 49.176 27.107 ;
     RECT  44.736 26.629 45.912 27.445 ;
     RECT  44.736 27.445 46.68 27.635 ;
     RECT  43.248 24.515 43.272 27.971 ;
     RECT  45.6 27.635 46.68 28.115 ;
     RECT  29.04 16.885 29.712 28.547 ;
     RECT  29.232 28.547 29.712 30.181 ;
     RECT  18.144 18.851 18.912 31.379 ;
     RECT  24 17.075 24.312 31.381 ;
     RECT  18.288 31.379 18.912 31.427 ;
     RECT  28.32 30.181 29.712 31.619 ;
     RECT  29.232 31.619 29.712 32.437 ;
     RECT  24 31.381 25.128 33.539 ;
     RECT  45.6 28.115 45.912 33.541 ;
     RECT  34.8 5.795 35.112 33.925 ;
     RECT  31.008 32.869 31.032 33.971 ;
     RECT  51 22.787 51.312 33.973 ;
     RECT  44.688 33.541 45.912 35.077 ;
     RECT  50.16 33.973 51.312 35.411 ;
     RECT  44.688 35.077 46.2 35.699 ;
     RECT  45.168 35.699 46.2 35.987 ;
     RECT  29.232 32.437 29.976 36.083 ;
     RECT  24 33.539 24.312 36.133 ;
     RECT  25.632 35.029 25.656 36.133 ;
     RECT  45.6 35.987 46.2 36.997 ;
     RECT  40.08 24.901 40.512 37.381 ;
     RECT  45.6 36.997 46.728 37.475 ;
     RECT  24 36.133 25.656 37.667 ;
     RECT  34.272 33.925 35.112 38.483 ;
     RECT  48.48 36.997 48.504 38.675 ;
     RECT  7.8 26.677 9.384 39.011 ;
     RECT  49.584 38.629 49.608 39.061 ;
     RECT  49.584 39.061 49.848 39.107 ;
     RECT  32.832 31.813 32.856 39.443 ;
     RECT  10.848 39.445 10.872 39.587 ;
     RECT  24 37.667 25.176 39.635 ;
     RECT  34.8 38.483 35.112 39.877 ;
     RECT  49.824 39.107 49.848 40.115 ;
     RECT  34.368 39.877 35.112 42.755 ;
     RECT  34.704 42.755 35.112 43.043 ;
     RECT  34.8 43.043 35.112 44.725 ;
     RECT  39.36 37.381 40.512 45.733 ;
     RECT  34.8 44.725 35.4 46.211 ;
     RECT  39.36 45.733 41.4 46.597 ;
     RECT  39.36 46.597 41.88 46.739 ;
     RECT  29.232 36.083 29.712 47.653 ;
     RECT  40.08 46.739 41.88 47.845 ;
     RECT  40.08 47.845 41.976 47.891 ;
     RECT  29.232 47.653 30.216 48.131 ;
     RECT  31.344 47.461 31.368 49.523 ;
     RECT  24 39.635 24.792 49.667 ;
     RECT  29.232 48.131 29.712 49.763 ;
     RECT  26.832 48.997 26.856 50.243 ;
     RECT  29.28 49.763 29.712 50.677 ;
     RECT  7.8 39.011 9.048 50.723 ;
     RECT  29.28 50.677 30.552 51.395 ;
     RECT  7.8 50.723 8.856 51.923 ;
     RECT  18.6 31.427 18.912 51.925 ;
     RECT  25.488 50.677 25.512 52.019 ;
     RECT  41.856 47.891 41.976 53.509 ;
     RECT  40.08 47.891 40.512 53.653 ;
     RECT  41.808 53.509 41.976 53.653 ;
     RECT  40.08 53.653 41.976 53.699 ;
     RECT  26.784 51.973 26.808 54.949 ;
     RECT  26.784 54.949 27.288 54.995 ;
     RECT  40.08 53.699 41.832 55.139 ;
     RECT  6.48 30.325 6.504 55.237 ;
     RECT  7.8 51.923 8.112 55.237 ;
     RECT  22.416 52.981 22.44 55.331 ;
     RECT  18.48 51.925 18.912 55.427 ;
     RECT  40.08 55.139 40.512 55.429 ;
     RECT  29.4 51.395 30.552 55.571 ;
     RECT  6.48 55.237 8.112 55.955 ;
     RECT  41.808 55.139 41.832 55.957 ;
     RECT  41.808 55.957 42.168 56.003 ;
     RECT  12 55.237 12.024 56.195 ;
     RECT  42.144 56.003 42.168 56.243 ;
     RECT  2.4 2.151 2.712 58.117 ;
     RECT  6.48 55.955 6.504 58.117 ;
     RECT  7.8 55.955 8.112 58.117 ;
     RECT  9.648 55.141 9.672 58.117 ;
     RECT  13.2 7.091 13.512 58.117 ;
     RECT  18.6 55.427 18.912 58.117 ;
     RECT  20.64 54.853 20.664 58.117 ;
     RECT  24 49.667 24.312 58.117 ;
     RECT  27.264 54.995 27.288 58.117 ;
     RECT  29.4 55.571 29.712 58.117 ;
     RECT  34.8 46.211 35.112 58.117 ;
     RECT  39.552 55.429 40.512 58.117 ;
     RECT  45.6 37.475 45.912 58.117 ;
     RECT  49.008 56.197 49.032 58.117 ;
     RECT  51 35.411 51.312 58.117 ;
     RECT  54.288 57.685 54.312 58.117 ;
     RECT  2.4 58.117 30.696 58.165 ;
     RECT  36.144 58.117 51.312 58.329 ;
     RECT  56.4 2.151 56.712 58.329 ;
     RECT  2.4 58.165 30.84 58.343 ;
     RECT  36.144 58.329 51.12 58.343 ;
     RECT  56.4 58.329 56.52 58.343 ;
     RECT  32.256 58.117 35.112 58.549 ;
     RECT  36.144 58.343 50.424 58.549 ;
     RECT  32.256 58.549 50.424 58.645 ;
     RECT  53.424 58.117 55.032 59.845 ;
     RECT  3.312 58.343 30.84 60.396 ;
     RECT  3.336 60.396 3.456 60.432 ;
     RECT  3.48 60.396 3.6 60.432 ;
     RECT  3.624 60.396 3.744 60.432 ;
     RECT  3.768 60.396 3.888 60.432 ;
     RECT  3.912 60.396 4.032 60.432 ;
     RECT  4.056 60.396 4.176 60.432 ;
     RECT  4.2 60.396 4.32 60.432 ;
     RECT  4.344 60.396 4.464 60.432 ;
     RECT  4.488 60.396 4.608 60.432 ;
     RECT  4.632 60.396 4.752 60.432 ;
     RECT  4.776 60.396 4.896 60.432 ;
     RECT  4.92 60.396 5.04 60.432 ;
     RECT  5.064 60.396 5.184 60.432 ;
     RECT  5.208 60.396 5.328 60.432 ;
     RECT  5.352 60.396 5.472 60.432 ;
     RECT  5.496 60.396 5.616 60.432 ;
     RECT  5.64 60.396 5.76 60.432 ;
     RECT  5.784 60.396 5.904 60.432 ;
     RECT  5.928 60.396 6.048 60.432 ;
     RECT  6.072 60.396 6.192 60.432 ;
     RECT  6.216 60.396 6.336 60.432 ;
     RECT  6.36 60.396 6.48 60.432 ;
     RECT  6.504 60.396 6.624 60.432 ;
     RECT  6.648 60.396 6.768 60.432 ;
     RECT  6.792 60.396 6.912 60.432 ;
     RECT  6.936 60.396 7.056 60.432 ;
     RECT  7.08 60.396 7.2 60.432 ;
     RECT  7.224 60.396 7.344 60.432 ;
     RECT  7.368 60.396 7.488 60.432 ;
     RECT  7.512 60.396 7.632 60.432 ;
     RECT  7.656 60.396 7.776 60.432 ;
     RECT  7.8 60.396 7.92 60.432 ;
     RECT  7.944 60.396 8.064 60.432 ;
     RECT  8.088 60.396 8.208 60.432 ;
     RECT  8.232 60.396 8.352 60.432 ;
     RECT  8.376 60.396 8.496 60.432 ;
     RECT  8.52 60.396 8.64 60.432 ;
     RECT  8.664 60.396 8.784 60.432 ;
     RECT  8.808 60.396 8.928 60.432 ;
     RECT  8.952 60.396 9.072 60.432 ;
     RECT  9.096 60.396 9.216 60.432 ;
     RECT  9.24 60.396 9.36 60.432 ;
     RECT  9.384 60.396 9.504 60.432 ;
     RECT  9.528 60.396 9.648 60.432 ;
     RECT  9.672 60.396 9.792 60.432 ;
     RECT  9.816 60.396 9.936 60.432 ;
     RECT  9.96 60.396 10.08 60.432 ;
     RECT  10.104 60.396 10.224 60.432 ;
     RECT  10.248 60.396 10.368 60.432 ;
     RECT  10.392 60.396 10.512 60.432 ;
     RECT  10.536 60.396 10.656 60.432 ;
     RECT  10.68 60.396 10.8 60.432 ;
     RECT  10.824 60.396 10.944 60.432 ;
     RECT  10.968 60.396 11.088 60.432 ;
     RECT  11.112 60.396 11.232 60.432 ;
     RECT  11.256 60.396 11.376 60.432 ;
     RECT  11.4 60.396 11.52 60.432 ;
     RECT  11.544 60.396 11.664 60.432 ;
     RECT  11.688 60.396 11.808 60.432 ;
     RECT  11.832 60.396 11.952 60.432 ;
     RECT  11.976 60.396 12.096 60.432 ;
     RECT  12.12 60.396 12.24 60.432 ;
     RECT  12.264 60.396 12.384 60.432 ;
     RECT  12.408 60.396 12.528 60.432 ;
     RECT  12.552 60.396 12.672 60.432 ;
     RECT  12.696 60.396 12.816 60.432 ;
     RECT  12.84 60.396 12.96 60.432 ;
     RECT  12.984 60.396 13.104 60.432 ;
     RECT  13.128 60.396 13.248 60.432 ;
     RECT  13.272 60.396 13.392 60.432 ;
     RECT  13.416 60.396 13.536 60.432 ;
     RECT  13.56 60.396 13.68 60.432 ;
     RECT  13.704 60.396 13.824 60.432 ;
     RECT  13.848 60.396 13.968 60.432 ;
     RECT  13.992 60.396 14.112 60.432 ;
     RECT  14.136 60.396 14.256 60.432 ;
     RECT  14.28 60.396 14.4 60.432 ;
     RECT  14.424 60.396 14.544 60.432 ;
     RECT  14.568 60.396 14.688 60.432 ;
     RECT  14.712 60.396 14.832 60.432 ;
     RECT  14.856 60.396 14.976 60.432 ;
     RECT  15 60.396 15.12 60.432 ;
     RECT  15.144 60.396 15.264 60.432 ;
     RECT  15.288 60.396 15.408 60.432 ;
     RECT  15.432 60.396 15.552 60.432 ;
     RECT  15.576 60.396 15.696 60.432 ;
     RECT  15.72 60.396 15.84 60.432 ;
     RECT  15.864 60.396 15.984 60.432 ;
     RECT  16.008 60.396 16.128 60.432 ;
     RECT  16.152 60.396 16.272 60.432 ;
     RECT  16.296 60.396 16.416 60.432 ;
     RECT  16.44 60.396 16.56 60.432 ;
     RECT  16.584 60.396 16.704 60.432 ;
     RECT  16.728 60.396 16.848 60.432 ;
     RECT  16.872 60.396 16.992 60.432 ;
     RECT  17.016 60.396 17.136 60.432 ;
     RECT  17.16 60.396 17.28 60.432 ;
     RECT  17.304 60.396 17.424 60.432 ;
     RECT  17.448 60.396 17.568 60.432 ;
     RECT  17.592 60.396 17.712 60.432 ;
     RECT  17.736 60.396 17.856 60.432 ;
     RECT  17.88 60.396 18 60.432 ;
     RECT  18.024 60.396 18.144 60.432 ;
     RECT  18.168 60.396 18.288 60.432 ;
     RECT  18.312 60.396 18.432 60.432 ;
     RECT  18.456 60.396 18.576 60.432 ;
     RECT  18.6 60.396 18.72 60.432 ;
     RECT  18.744 60.396 18.864 60.432 ;
     RECT  18.888 60.396 19.008 60.432 ;
     RECT  19.032 60.396 19.152 60.432 ;
     RECT  19.176 60.396 19.296 60.432 ;
     RECT  19.32 60.396 19.44 60.432 ;
     RECT  19.464 60.396 19.584 60.432 ;
     RECT  19.608 60.396 19.728 60.432 ;
     RECT  19.752 60.396 19.872 60.432 ;
     RECT  19.896 60.396 20.016 60.432 ;
     RECT  20.04 60.396 20.16 60.432 ;
     RECT  20.184 60.396 20.304 60.432 ;
     RECT  20.328 60.396 20.448 60.432 ;
     RECT  20.472 60.396 20.592 60.432 ;
     RECT  20.616 60.396 20.736 60.432 ;
     RECT  20.76 60.396 20.88 60.432 ;
     RECT  20.904 60.396 21.024 60.432 ;
     RECT  21.048 60.396 21.168 60.432 ;
     RECT  21.192 60.396 21.312 60.432 ;
     RECT  21.336 60.396 21.456 60.432 ;
     RECT  21.48 60.396 21.6 60.432 ;
     RECT  21.624 60.396 21.744 60.432 ;
     RECT  21.768 60.396 21.888 60.432 ;
     RECT  21.912 60.396 22.032 60.432 ;
     RECT  22.056 60.396 22.176 60.432 ;
     RECT  22.2 60.396 22.32 60.432 ;
     RECT  22.344 60.396 22.464 60.432 ;
     RECT  22.488 60.396 22.608 60.432 ;
     RECT  22.632 60.396 22.752 60.432 ;
     RECT  22.776 60.396 22.896 60.432 ;
     RECT  22.92 60.396 23.04 60.432 ;
     RECT  23.064 60.396 23.184 60.432 ;
     RECT  23.208 60.396 23.328 60.432 ;
     RECT  23.352 60.396 23.472 60.432 ;
     RECT  23.496 60.396 23.616 60.432 ;
     RECT  23.64 60.396 23.76 60.432 ;
     RECT  23.784 60.396 23.904 60.432 ;
     RECT  23.928 60.396 24.048 60.432 ;
     RECT  24.072 60.396 24.192 60.432 ;
     RECT  24.216 60.396 24.336 60.432 ;
     RECT  24.36 60.396 24.48 60.432 ;
     RECT  24.504 60.396 24.624 60.432 ;
     RECT  24.648 60.396 24.768 60.432 ;
     RECT  24.792 60.396 24.912 60.432 ;
     RECT  24.936 60.396 25.056 60.432 ;
     RECT  25.08 60.396 25.2 60.432 ;
     RECT  25.224 60.396 25.344 60.432 ;
     RECT  25.368 60.396 25.488 60.432 ;
     RECT  25.512 60.396 25.632 60.432 ;
     RECT  25.656 60.396 25.776 60.432 ;
     RECT  25.8 60.396 25.92 60.432 ;
     RECT  25.944 60.396 26.064 60.432 ;
     RECT  26.088 60.396 26.208 60.432 ;
     RECT  26.232 60.396 26.352 60.432 ;
     RECT  26.376 60.396 26.496 60.432 ;
     RECT  26.52 60.396 26.64 60.432 ;
     RECT  26.664 60.396 26.784 60.432 ;
     RECT  26.808 60.396 26.928 60.432 ;
     RECT  26.952 60.396 27.072 60.432 ;
     RECT  27.096 60.396 27.216 60.432 ;
     RECT  27.24 60.396 27.36 60.432 ;
     RECT  27.384 60.396 27.504 60.432 ;
     RECT  27.528 60.396 27.648 60.432 ;
     RECT  27.672 60.396 27.792 60.432 ;
     RECT  27.816 60.396 27.936 60.432 ;
     RECT  27.96 60.396 28.08 60.432 ;
     RECT  28.104 60.396 28.224 60.432 ;
     RECT  28.248 60.396 28.368 60.432 ;
     RECT  28.392 60.396 28.512 60.432 ;
     RECT  28.536 60.396 28.656 60.432 ;
     RECT  28.68 60.396 28.8 60.432 ;
     RECT  28.824 60.396 28.944 60.432 ;
     RECT  28.968 60.396 29.088 60.432 ;
     RECT  29.112 60.396 29.232 60.432 ;
     RECT  29.256 60.396 29.376 60.432 ;
     RECT  29.4 60.396 29.52 60.432 ;
     RECT  29.544 60.396 29.664 60.432 ;
     RECT  29.688 60.396 29.808 60.432 ;
     RECT  29.832 60.396 29.952 60.432 ;
     RECT  29.976 60.396 30.096 60.432 ;
     RECT  30.12 60.396 30.24 60.432 ;
     RECT  30.264 60.396 30.384 60.432 ;
     RECT  30.408 60.396 30.528 60.432 ;
     RECT  30.552 60.396 30.672 60.432 ;
     RECT  30.696 60.396 30.816 60.432 ;
     RECT  32.112 58.645 50.424 60.396 ;
     RECT  32.136 60.396 32.256 60.432 ;
     RECT  32.28 60.396 32.4 60.432 ;
     RECT  32.424 60.396 32.544 60.432 ;
     RECT  32.568 60.396 32.688 60.432 ;
     RECT  32.712 60.396 32.832 60.432 ;
     RECT  32.856 60.396 32.976 60.432 ;
     RECT  33 60.396 33.12 60.432 ;
     RECT  33.144 60.396 33.264 60.432 ;
     RECT  33.288 60.396 33.408 60.432 ;
     RECT  33.432 60.396 33.552 60.432 ;
     RECT  33.576 60.396 33.696 60.432 ;
     RECT  33.72 60.396 33.84 60.432 ;
     RECT  33.864 60.396 33.984 60.432 ;
     RECT  34.008 60.396 34.128 60.432 ;
     RECT  34.152 60.396 34.272 60.432 ;
     RECT  34.296 60.396 34.416 60.432 ;
     RECT  34.44 60.396 34.56 60.432 ;
     RECT  34.584 60.396 34.704 60.432 ;
     RECT  34.728 60.396 34.848 60.432 ;
     RECT  34.872 60.396 34.992 60.432 ;
     RECT  35.016 60.396 35.136 60.432 ;
     RECT  35.16 60.396 35.28 60.432 ;
     RECT  35.304 60.396 35.424 60.432 ;
     RECT  35.448 60.396 35.568 60.432 ;
     RECT  35.592 60.396 35.712 60.432 ;
     RECT  35.736 60.396 35.856 60.432 ;
     RECT  35.88 60.396 36 60.432 ;
     RECT  36.024 60.396 36.144 60.432 ;
     RECT  36.168 60.396 36.288 60.432 ;
     RECT  36.312 60.396 36.432 60.432 ;
     RECT  36.456 60.396 36.576 60.432 ;
     RECT  36.6 60.396 36.72 60.432 ;
     RECT  36.744 60.396 36.864 60.432 ;
     RECT  36.888 60.396 37.008 60.432 ;
     RECT  37.032 60.396 37.152 60.432 ;
     RECT  37.176 60.396 37.296 60.432 ;
     RECT  37.32 60.396 37.44 60.432 ;
     RECT  37.464 60.396 37.584 60.432 ;
     RECT  37.608 60.396 37.728 60.432 ;
     RECT  37.752 60.396 37.872 60.432 ;
     RECT  37.896 60.396 38.016 60.432 ;
     RECT  38.04 60.396 38.16 60.432 ;
     RECT  38.184 60.396 38.304 60.432 ;
     RECT  38.328 60.396 38.448 60.432 ;
     RECT  38.472 60.396 38.592 60.432 ;
     RECT  38.616 60.396 38.736 60.432 ;
     RECT  38.76 60.396 38.88 60.432 ;
     RECT  38.904 60.396 39.024 60.432 ;
     RECT  39.048 60.396 39.168 60.432 ;
     RECT  39.192 60.396 39.312 60.432 ;
     RECT  39.336 60.396 39.456 60.432 ;
     RECT  39.48 60.396 39.6 60.432 ;
     RECT  39.624 60.396 39.744 60.432 ;
     RECT  39.768 60.396 39.888 60.432 ;
     RECT  39.912 60.396 40.032 60.432 ;
     RECT  40.056 60.396 40.176 60.432 ;
     RECT  40.2 60.396 40.32 60.432 ;
     RECT  40.344 60.396 40.464 60.432 ;
     RECT  40.488 60.396 40.608 60.432 ;
     RECT  40.632 60.396 40.752 60.432 ;
     RECT  40.776 60.396 40.896 60.432 ;
     RECT  40.92 60.396 41.04 60.432 ;
     RECT  41.064 60.396 41.184 60.432 ;
     RECT  41.208 60.396 41.328 60.432 ;
     RECT  41.352 60.396 41.472 60.432 ;
     RECT  41.496 60.396 41.616 60.432 ;
     RECT  41.64 60.396 41.76 60.432 ;
     RECT  41.784 60.396 41.904 60.432 ;
     RECT  41.928 60.396 42.048 60.432 ;
     RECT  42.072 60.396 42.192 60.432 ;
     RECT  42.216 60.396 42.336 60.432 ;
     RECT  42.36 60.396 42.48 60.432 ;
     RECT  42.504 60.396 42.624 60.432 ;
     RECT  42.648 60.396 42.768 60.432 ;
     RECT  42.792 60.396 42.912 60.432 ;
     RECT  42.936 60.396 43.056 60.432 ;
     RECT  43.08 60.396 43.2 60.432 ;
     RECT  43.224 60.396 43.344 60.432 ;
     RECT  43.368 60.396 43.488 60.432 ;
     RECT  43.512 60.396 43.632 60.432 ;
     RECT  43.656 60.396 43.776 60.432 ;
     RECT  43.8 60.396 43.92 60.432 ;
     RECT  43.944 60.396 44.064 60.432 ;
     RECT  44.088 60.396 44.208 60.432 ;
     RECT  44.232 60.396 44.352 60.432 ;
     RECT  44.376 60.396 44.496 60.432 ;
     RECT  44.52 60.396 44.64 60.432 ;
     RECT  44.664 60.396 44.784 60.432 ;
     RECT  44.808 60.396 44.928 60.432 ;
     RECT  44.952 60.396 45.072 60.432 ;
     RECT  45.096 60.396 45.216 60.432 ;
     RECT  45.24 60.396 45.36 60.432 ;
     RECT  45.384 60.396 45.504 60.432 ;
     RECT  45.528 60.396 45.648 60.432 ;
     RECT  45.672 60.396 45.792 60.432 ;
     RECT  45.816 60.396 45.936 60.432 ;
     RECT  45.96 60.396 46.08 60.432 ;
     RECT  46.104 60.396 46.224 60.432 ;
     RECT  46.248 60.396 46.368 60.432 ;
     RECT  46.392 60.396 46.512 60.432 ;
     RECT  46.536 60.396 46.656 60.432 ;
     RECT  46.68 60.396 46.8 60.432 ;
     RECT  46.824 60.396 46.944 60.432 ;
     RECT  46.968 60.396 47.088 60.432 ;
     RECT  47.112 60.396 47.232 60.432 ;
     RECT  47.256 60.396 47.376 60.432 ;
     RECT  47.4 60.396 47.52 60.432 ;
     RECT  47.544 60.396 47.664 60.432 ;
     RECT  47.688 60.396 47.808 60.432 ;
     RECT  47.832 60.396 47.952 60.432 ;
     RECT  47.976 60.396 48.096 60.432 ;
     RECT  48.12 60.396 48.24 60.432 ;
     RECT  48.264 60.396 48.384 60.432 ;
     RECT  48.408 60.396 48.528 60.432 ;
     RECT  48.552 60.396 48.672 60.432 ;
     RECT  48.696 60.396 48.816 60.432 ;
     RECT  48.84 60.396 48.96 60.432 ;
     RECT  48.984 60.396 49.104 60.432 ;
     RECT  49.128 60.396 49.248 60.432 ;
     RECT  49.272 60.396 49.392 60.432 ;
     RECT  49.416 60.396 49.536 60.432 ;
     RECT  49.56 60.396 49.68 60.432 ;
     RECT  49.704 60.396 49.824 60.432 ;
     RECT  49.848 60.396 49.968 60.432 ;
     RECT  49.992 60.396 50.112 60.432 ;
     RECT  50.136 60.396 50.256 60.432 ;
     RECT  50.28 60.396 50.4 60.432 ;
     RECT  53.28 59.845 55.032 60.396 ;
     RECT  53.304 60.396 53.424 60.432 ;
     RECT  53.448 60.396 53.568 60.432 ;
     RECT  53.592 60.396 53.712 60.432 ;
     RECT  53.736 60.396 53.856 60.432 ;
     RECT  53.88 60.396 54 60.432 ;
     RECT  54.024 60.396 54.144 60.432 ;
     RECT  54.168 60.396 54.288 60.432 ;
     RECT  54.312 60.396 54.432 60.432 ;
     RECT  54.456 60.396 54.576 60.432 ;
     RECT  54.6 60.396 54.72 60.432 ;
     RECT  54.744 60.396 54.864 60.432 ;
     RECT  54.888 60.396 55.008 60.432 ;
     RECT  6.24 1.139 6.336 1.187 ;
     RECT  6.24 1.187 6.768 1.763 ;
     RECT  6.24 1.763 7.344 2.245 ;
     RECT  19.32 1.763 20.304 2.291 ;
     RECT  10.68 1.859 11.808 2.291 ;
     RECT  35.256 1.859 36.432 3.635 ;
     RECT  25.656 1.955 26.64 2.291 ;
     RECT  6.264 2.245 7.344 2.867 ;
     RECT  17.016 2.291 18.384 5.077 ;
     RECT  19.176 2.291 20.304 5.125 ;
     RECT  24.504 2.291 26.64 2.771 ;
     RECT  37.032 2.291 38.16 5.747 ;
     RECT  44.52 2.291 45.6 4.933 ;
     RECT  38.76 2.339 39.744 2.915 ;
     RECT  48.984 2.339 50.256 3.011 ;
     RECT  24.504 2.771 25.512 3.349 ;
     RECT  13.656 2.867 14.688 4.981 ;
     RECT  20.328 2.915 21.6 5.653 ;
     RECT  38.76 2.915 39.984 3.251 ;
     RECT  38.76 3.251 40.2 4.837 ;
     RECT  24.504 3.349 25.488 5.747 ;
     RECT  16.008 3.443 16.992 4.885 ;
     RECT  35.208 3.635 36.432 5.077 ;
     RECT  47.304 4.547 48.384 4.931 ;
     RECT  11.832 4.595 12.816 5.171 ;
     RECT  38.904 4.837 40.2 12.563 ;
     RECT  47.256 4.931 48.384 5.747 ;
     RECT  17.016 5.077 18.288 5.411 ;
     RECT  35.352 5.077 36.432 5.747 ;
     RECT  13.656 5.123 15.12 5.267 ;
     RECT  12.672 5.171 12.816 5.605 ;
     RECT  13.608 5.267 15.12 5.747 ;
     RECT  17.016 5.411 18.384 5.507 ;
     RECT  46.104 5.507 47.232 5.747 ;
     RECT  19.176 5.603 20.304 6.227 ;
     RECT  24.312 5.747 25.488 11.653 ;
     RECT  20.328 5.795 21.6 6.131 ;
     RECT  44.52 6.419 45.6 6.995 ;
     RECT  24.456 11.653 25.488 12.563 ;
     RECT  24.312 12.563 25.488 12.803 ;
     RECT  18.912 12.757 20.16 17.603 ;
     RECT  8.112 13.045 9.168 13.621 ;
     RECT  6.072 14.533 7.584 15.491 ;
     RECT  24.312 14.773 25.344 14.963 ;
     RECT  24.312 14.963 25.536 15.971 ;
     RECT  24.312 15.971 24.408 16.885 ;
     RECT  2.712 16.501 4.224 17.123 ;
     RECT  18.912 17.603 19.512 18.133 ;
     RECT  49.464 19.237 50.784 19.861 ;
     RECT  49.464 19.861 50.736 20.867 ;
     RECT  49.464 20.867 50.784 21.155 ;
     RECT  6.504 21.301 7.8 22.547 ;
     RECT  51.312 22.213 52.704 23.843 ;
     RECT  52.728 23.797 54.144 23.843 ;
     RECT  42.216 23.893 43.248 24.947 ;
     RECT  43.272 26.629 44.736 27.635 ;
     RECT  6.504 30.325 7.8 55.237 ;
     RECT  29.976 32.869 31.008 33.971 ;
     RECT  24.312 33.539 25.128 35.029 ;
     RECT  32.856 33.925 34.272 38.483 ;
     RECT  24.312 35.029 25.632 36.133 ;
     RECT  32.856 38.483 34.8 39.443 ;
     RECT  48.504 38.629 49.584 38.675 ;
     RECT  49.608 38.629 51 39.061 ;
     RECT  49.848 39.061 51 40.115 ;
     RECT  34.368 39.443 34.8 39.877 ;
     RECT  30.216 47.653 31.344 48.131 ;
     RECT  40.512 47.891 41.856 53.509 ;
     RECT  24.312 49.667 24.792 50.677 ;
     RECT  24.312 50.677 25.488 52.019 ;
     RECT  25.512 51.973 26.784 52.019 ;
     RECT  40.512 53.509 41.808 53.653 ;
     RECT  40.512 55.139 41.808 56.003 ;
     RECT  12.024 55.237 13.2 56.195 ;
     RECT  6.504 55.955 7.8 58.117 ;
     RECT  35.112 58.117 36.144 58.549 ;
     RECT  55.032 58.117 56.4 58.343 ;
     RECT  30.84 58.165 32.256 58.645 ;
     RECT  30.84 58.645 32.112 60.348 ;
     RECT  30.888 60.348 32.064 60.432 ;
  END
END ot_static_cmd_target
END LIBRARY
